# Placeholder macro written by tools/chip_assembly/macros.py
# kind: analog_pma; S81 SerDes PMA TX half (modelled analog, ot_s81_pma_bm LAT 4 behaviour)
VERSION 5.7 ;
BUSBITCHARS "[]" ;
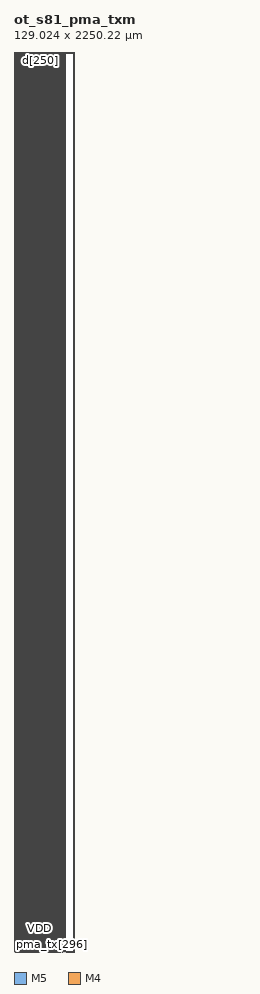
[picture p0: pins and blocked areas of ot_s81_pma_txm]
MACRO ot_s81_pma_txm
  FOREIGN ot_s81_pma_txm 0 0 ;
  SYMMETRY X Y R90 ;
  SIZE 129.024 BY 2250.216 ;
  CLASS BLOCK ;
  PIN ck
    DIRECTION INPUT ;
    USE SIGNAL ;
    SHAPE ABUTMENT ;
    PORT
      LAYER M5 ;
      RECT 5.472 2250.024 5.496 2250.216 ;
    END
  END ck
  PIN d_v
    DIRECTION INPUT ;
    USE SIGNAL ;
    SHAPE ABUTMENT ;
    PORT
      LAYER M5 ;
      RECT 9.984 2250.024 10.008 2250.216 ;
    END
  END d_v
  PIN d[0]
    DIRECTION INPUT ;
    USE SIGNAL ;
    SHAPE ABUTMENT ;
    PORT
      LAYER M5 ;
      RECT 14.496 2250.024 14.520 2250.216 ;
    END
  END d[0]
  PIN d[1]
    DIRECTION INPUT ;
    USE SIGNAL ;
    SHAPE ABUTMENT ;
    PORT
      LAYER M5 ;
      RECT 14.688 2250.024 14.712 2250.216 ;
    END
  END d[1]
  PIN d[2]
    DIRECTION INPUT ;
    USE SIGNAL ;
    SHAPE ABUTMENT ;
    PORT
      LAYER M5 ;
      RECT 14.880 2250.024 14.904 2250.216 ;
    END
  END d[2]
  PIN d[3]
    DIRECTION INPUT ;
    USE SIGNAL ;
    SHAPE ABUTMENT ;
    PORT
      LAYER M5 ;
      RECT 15.072 2250.024 15.096 2250.216 ;
    END
  END d[3]
  PIN d[4]
    DIRECTION INPUT ;
    USE SIGNAL ;
    SHAPE ABUTMENT ;
    PORT
      LAYER M5 ;
      RECT 15.264 2250.024 15.288 2250.216 ;
    END
  END d[4]
  PIN d[5]
    DIRECTION INPUT ;
    USE SIGNAL ;
    SHAPE ABUTMENT ;
    PORT
      LAYER M5 ;
      RECT 15.504 2250.024 15.528 2250.216 ;
    END
  END d[5]
  PIN d[6]
    DIRECTION INPUT ;
    USE SIGNAL ;
    SHAPE ABUTMENT ;
    PORT
      LAYER M5 ;
      RECT 15.696 2250.024 15.720 2250.216 ;
    END
  END d[6]
  PIN d[7]
    DIRECTION INPUT ;
    USE SIGNAL ;
    SHAPE ABUTMENT ;
    PORT
      LAYER M5 ;
      RECT 15.888 2250.024 15.912 2250.216 ;
    END
  END d[7]
  PIN d[8]
    DIRECTION INPUT ;
    USE SIGNAL ;
    SHAPE ABUTMENT ;
    PORT
      LAYER M5 ;
      RECT 16.080 2250.024 16.104 2250.216 ;
    END
  END d[8]
  PIN d[9]
    DIRECTION INPUT ;
    USE SIGNAL ;
    SHAPE ABUTMENT ;
    PORT
      LAYER M5 ;
      RECT 16.272 2250.024 16.296 2250.216 ;
    END
  END d[9]
  PIN d[10]
    DIRECTION INPUT ;
    USE SIGNAL ;
    SHAPE ABUTMENT ;
    PORT
      LAYER M5 ;
      RECT 16.512 2250.024 16.536 2250.216 ;
    END
  END d[10]
  PIN d[11]
    DIRECTION INPUT ;
    USE SIGNAL ;
    SHAPE ABUTMENT ;
    PORT
      LAYER M5 ;
      RECT 16.704 2250.024 16.728 2250.216 ;
    END
  END d[11]
  PIN d[12]
    DIRECTION INPUT ;
    USE SIGNAL ;
    SHAPE ABUTMENT ;
    PORT
      LAYER M5 ;
      RECT 16.896 2250.024 16.920 2250.216 ;
    END
  END d[12]
  PIN d[13]
    DIRECTION INPUT ;
    USE SIGNAL ;
    SHAPE ABUTMENT ;
    PORT
      LAYER M5 ;
      RECT 17.088 2250.024 17.112 2250.216 ;
    END
  END d[13]
  PIN d[14]
    DIRECTION INPUT ;
    USE SIGNAL ;
    SHAPE ABUTMENT ;
    PORT
      LAYER M5 ;
      RECT 17.280 2250.024 17.304 2250.216 ;
    END
  END d[14]
  PIN d[15]
    DIRECTION INPUT ;
    USE SIGNAL ;
    SHAPE ABUTMENT ;
    PORT
      LAYER M5 ;
      RECT 17.520 2250.024 17.544 2250.216 ;
    END
  END d[15]
  PIN d[16]
    DIRECTION INPUT ;
    USE SIGNAL ;
    SHAPE ABUTMENT ;
    PORT
      LAYER M5 ;
      RECT 17.712 2250.024 17.736 2250.216 ;
    END
  END d[16]
  PIN d[17]
    DIRECTION INPUT ;
    USE SIGNAL ;
    SHAPE ABUTMENT ;
    PORT
      LAYER M5 ;
      RECT 17.904 2250.024 17.928 2250.216 ;
    END
  END d[17]
  PIN d[18]
    DIRECTION INPUT ;
    USE SIGNAL ;
    SHAPE ABUTMENT ;
    PORT
      LAYER M5 ;
      RECT 18.096 2250.024 18.120 2250.216 ;
    END
  END d[18]
  PIN d[19]
    DIRECTION INPUT ;
    USE SIGNAL ;
    SHAPE ABUTMENT ;
    PORT
      LAYER M5 ;
      RECT 18.336 2250.024 18.360 2250.216 ;
    END
  END d[19]
  PIN d[20]
    DIRECTION INPUT ;
    USE SIGNAL ;
    SHAPE ABUTMENT ;
    PORT
      LAYER M5 ;
      RECT 18.528 2250.024 18.552 2250.216 ;
    END
  END d[20]
  PIN d[21]
    DIRECTION INPUT ;
    USE SIGNAL ;
    SHAPE ABUTMENT ;
    PORT
      LAYER M5 ;
      RECT 18.720 2250.024 18.744 2250.216 ;
    END
  END d[21]
  PIN d[22]
    DIRECTION INPUT ;
    USE SIGNAL ;
    SHAPE ABUTMENT ;
    PORT
      LAYER M5 ;
      RECT 18.912 2250.024 18.936 2250.216 ;
    END
  END d[22]
  PIN d[23]
    DIRECTION INPUT ;
    USE SIGNAL ;
    SHAPE ABUTMENT ;
    PORT
      LAYER M5 ;
      RECT 19.104 2250.024 19.128 2250.216 ;
    END
  END d[23]
  PIN d[24]
    DIRECTION INPUT ;
    USE SIGNAL ;
    SHAPE ABUTMENT ;
    PORT
      LAYER M5 ;
      RECT 19.344 2250.024 19.368 2250.216 ;
    END
  END d[24]
  PIN d[25]
    DIRECTION INPUT ;
    USE SIGNAL ;
    SHAPE ABUTMENT ;
    PORT
      LAYER M5 ;
      RECT 19.536 2250.024 19.560 2250.216 ;
    END
  END d[25]
  PIN d[26]
    DIRECTION INPUT ;
    USE SIGNAL ;
    SHAPE ABUTMENT ;
    PORT
      LAYER M5 ;
      RECT 19.728 2250.024 19.752 2250.216 ;
    END
  END d[26]
  PIN d[27]
    DIRECTION INPUT ;
    USE SIGNAL ;
    SHAPE ABUTMENT ;
    PORT
      LAYER M5 ;
      RECT 19.920 2250.024 19.944 2250.216 ;
    END
  END d[27]
  PIN d[28]
    DIRECTION INPUT ;
    USE SIGNAL ;
    SHAPE ABUTMENT ;
    PORT
      LAYER M5 ;
      RECT 20.112 2250.024 20.136 2250.216 ;
    END
  END d[28]
  PIN d[29]
    DIRECTION INPUT ;
    USE SIGNAL ;
    SHAPE ABUTMENT ;
    PORT
      LAYER M5 ;
      RECT 20.352 2250.024 20.376 2250.216 ;
    END
  END d[29]
  PIN d[30]
    DIRECTION INPUT ;
    USE SIGNAL ;
    SHAPE ABUTMENT ;
    PORT
      LAYER M5 ;
      RECT 20.544 2250.024 20.568 2250.216 ;
    END
  END d[30]
  PIN d[31]
    DIRECTION INPUT ;
    USE SIGNAL ;
    SHAPE ABUTMENT ;
    PORT
      LAYER M5 ;
      RECT 20.736 2250.024 20.760 2250.216 ;
    END
  END d[31]
  PIN d[32]
    DIRECTION INPUT ;
    USE SIGNAL ;
    SHAPE ABUTMENT ;
    PORT
      LAYER M5 ;
      RECT 20.928 2250.024 20.952 2250.216 ;
    END
  END d[32]
  PIN d[33]
    DIRECTION INPUT ;
    USE SIGNAL ;
    SHAPE ABUTMENT ;
    PORT
      LAYER M5 ;
      RECT 21.168 2250.024 21.192 2250.216 ;
    END
  END d[33]
  PIN d[34]
    DIRECTION INPUT ;
    USE SIGNAL ;
    SHAPE ABUTMENT ;
    PORT
      LAYER M5 ;
      RECT 21.360 2250.024 21.384 2250.216 ;
    END
  END d[34]
  PIN d[35]
    DIRECTION INPUT ;
    USE SIGNAL ;
    SHAPE ABUTMENT ;
    PORT
      LAYER M5 ;
      RECT 21.552 2250.024 21.576 2250.216 ;
    END
  END d[35]
  PIN d[36]
    DIRECTION INPUT ;
    USE SIGNAL ;
    SHAPE ABUTMENT ;
    PORT
      LAYER M5 ;
      RECT 21.744 2250.024 21.768 2250.216 ;
    END
  END d[36]
  PIN d[37]
    DIRECTION INPUT ;
    USE SIGNAL ;
    SHAPE ABUTMENT ;
    PORT
      LAYER M5 ;
      RECT 21.936 2250.024 21.960 2250.216 ;
    END
  END d[37]
  PIN d[38]
    DIRECTION INPUT ;
    USE SIGNAL ;
    SHAPE ABUTMENT ;
    PORT
      LAYER M5 ;
      RECT 22.176 2250.024 22.200 2250.216 ;
    END
  END d[38]
  PIN d[39]
    DIRECTION INPUT ;
    USE SIGNAL ;
    SHAPE ABUTMENT ;
    PORT
      LAYER M5 ;
      RECT 22.368 2250.024 22.392 2250.216 ;
    END
  END d[39]
  PIN d[40]
    DIRECTION INPUT ;
    USE SIGNAL ;
    SHAPE ABUTMENT ;
    PORT
      LAYER M5 ;
      RECT 22.560 2250.024 22.584 2250.216 ;
    END
  END d[40]
  PIN d[41]
    DIRECTION INPUT ;
    USE SIGNAL ;
    SHAPE ABUTMENT ;
    PORT
      LAYER M5 ;
      RECT 22.752 2250.024 22.776 2250.216 ;
    END
  END d[41]
  PIN d[42]
    DIRECTION INPUT ;
    USE SIGNAL ;
    SHAPE ABUTMENT ;
    PORT
      LAYER M5 ;
      RECT 22.944 2250.024 22.968 2250.216 ;
    END
  END d[42]
  PIN d[43]
    DIRECTION INPUT ;
    USE SIGNAL ;
    SHAPE ABUTMENT ;
    PORT
      LAYER M5 ;
      RECT 23.184 2250.024 23.208 2250.216 ;
    END
  END d[43]
  PIN d[44]
    DIRECTION INPUT ;
    USE SIGNAL ;
    SHAPE ABUTMENT ;
    PORT
      LAYER M5 ;
      RECT 23.376 2250.024 23.400 2250.216 ;
    END
  END d[44]
  PIN d[45]
    DIRECTION INPUT ;
    USE SIGNAL ;
    SHAPE ABUTMENT ;
    PORT
      LAYER M5 ;
      RECT 23.568 2250.024 23.592 2250.216 ;
    END
  END d[45]
  PIN d[46]
    DIRECTION INPUT ;
    USE SIGNAL ;
    SHAPE ABUTMENT ;
    PORT
      LAYER M5 ;
      RECT 23.760 2250.024 23.784 2250.216 ;
    END
  END d[46]
  PIN d[47]
    DIRECTION INPUT ;
    USE SIGNAL ;
    SHAPE ABUTMENT ;
    PORT
      LAYER M5 ;
      RECT 24.000 2250.024 24.024 2250.216 ;
    END
  END d[47]
  PIN d[48]
    DIRECTION INPUT ;
    USE SIGNAL ;
    SHAPE ABUTMENT ;
    PORT
      LAYER M5 ;
      RECT 24.192 2250.024 24.216 2250.216 ;
    END
  END d[48]
  PIN d[49]
    DIRECTION INPUT ;
    USE SIGNAL ;
    SHAPE ABUTMENT ;
    PORT
      LAYER M5 ;
      RECT 24.384 2250.024 24.408 2250.216 ;
    END
  END d[49]
  PIN d[50]
    DIRECTION INPUT ;
    USE SIGNAL ;
    SHAPE ABUTMENT ;
    PORT
      LAYER M5 ;
      RECT 24.576 2250.024 24.600 2250.216 ;
    END
  END d[50]
  PIN d[51]
    DIRECTION INPUT ;
    USE SIGNAL ;
    SHAPE ABUTMENT ;
    PORT
      LAYER M5 ;
      RECT 24.768 2250.024 24.792 2250.216 ;
    END
  END d[51]
  PIN d[52]
    DIRECTION INPUT ;
    USE SIGNAL ;
    SHAPE ABUTMENT ;
    PORT
      LAYER M5 ;
      RECT 25.008 2250.024 25.032 2250.216 ;
    END
  END d[52]
  PIN d[53]
    DIRECTION INPUT ;
    USE SIGNAL ;
    SHAPE ABUTMENT ;
    PORT
      LAYER M5 ;
      RECT 25.200 2250.024 25.224 2250.216 ;
    END
  END d[53]
  PIN d[54]
    DIRECTION INPUT ;
    USE SIGNAL ;
    SHAPE ABUTMENT ;
    PORT
      LAYER M5 ;
      RECT 25.392 2250.024 25.416 2250.216 ;
    END
  END d[54]
  PIN d[55]
    DIRECTION INPUT ;
    USE SIGNAL ;
    SHAPE ABUTMENT ;
    PORT
      LAYER M5 ;
      RECT 25.584 2250.024 25.608 2250.216 ;
    END
  END d[55]
  PIN d[56]
    DIRECTION INPUT ;
    USE SIGNAL ;
    SHAPE ABUTMENT ;
    PORT
      LAYER M5 ;
      RECT 25.776 2250.024 25.800 2250.216 ;
    END
  END d[56]
  PIN d[57]
    DIRECTION INPUT ;
    USE SIGNAL ;
    SHAPE ABUTMENT ;
    PORT
      LAYER M5 ;
      RECT 26.016 2250.024 26.040 2250.216 ;
    END
  END d[57]
  PIN d[58]
    DIRECTION INPUT ;
    USE SIGNAL ;
    SHAPE ABUTMENT ;
    PORT
      LAYER M5 ;
      RECT 26.208 2250.024 26.232 2250.216 ;
    END
  END d[58]
  PIN d[59]
    DIRECTION INPUT ;
    USE SIGNAL ;
    SHAPE ABUTMENT ;
    PORT
      LAYER M5 ;
      RECT 26.400 2250.024 26.424 2250.216 ;
    END
  END d[59]
  PIN d[60]
    DIRECTION INPUT ;
    USE SIGNAL ;
    SHAPE ABUTMENT ;
    PORT
      LAYER M5 ;
      RECT 26.592 2250.024 26.616 2250.216 ;
    END
  END d[60]
  PIN d[61]
    DIRECTION INPUT ;
    USE SIGNAL ;
    SHAPE ABUTMENT ;
    PORT
      LAYER M5 ;
      RECT 26.832 2250.024 26.856 2250.216 ;
    END
  END d[61]
  PIN d[62]
    DIRECTION INPUT ;
    USE SIGNAL ;
    SHAPE ABUTMENT ;
    PORT
      LAYER M5 ;
      RECT 27.024 2250.024 27.048 2250.216 ;
    END
  END d[62]
  PIN d[63]
    DIRECTION INPUT ;
    USE SIGNAL ;
    SHAPE ABUTMENT ;
    PORT
      LAYER M5 ;
      RECT 27.216 2250.024 27.240 2250.216 ;
    END
  END d[63]
  PIN d[64]
    DIRECTION INPUT ;
    USE SIGNAL ;
    SHAPE ABUTMENT ;
    PORT
      LAYER M5 ;
      RECT 27.408 2250.024 27.432 2250.216 ;
    END
  END d[64]
  PIN d[65]
    DIRECTION INPUT ;
    USE SIGNAL ;
    SHAPE ABUTMENT ;
    PORT
      LAYER M5 ;
      RECT 27.600 2250.024 27.624 2250.216 ;
    END
  END d[65]
  PIN d[66]
    DIRECTION INPUT ;
    USE SIGNAL ;
    SHAPE ABUTMENT ;
    PORT
      LAYER M5 ;
      RECT 27.840 2250.024 27.864 2250.216 ;
    END
  END d[66]
  PIN d[67]
    DIRECTION INPUT ;
    USE SIGNAL ;
    SHAPE ABUTMENT ;
    PORT
      LAYER M5 ;
      RECT 28.032 2250.024 28.056 2250.216 ;
    END
  END d[67]
  PIN d[68]
    DIRECTION INPUT ;
    USE SIGNAL ;
    SHAPE ABUTMENT ;
    PORT
      LAYER M5 ;
      RECT 28.224 2250.024 28.248 2250.216 ;
    END
  END d[68]
  PIN d[69]
    DIRECTION INPUT ;
    USE SIGNAL ;
    SHAPE ABUTMENT ;
    PORT
      LAYER M5 ;
      RECT 28.416 2250.024 28.440 2250.216 ;
    END
  END d[69]
  PIN d[70]
    DIRECTION INPUT ;
    USE SIGNAL ;
    SHAPE ABUTMENT ;
    PORT
      LAYER M5 ;
      RECT 28.608 2250.024 28.632 2250.216 ;
    END
  END d[70]
  PIN d[71]
    DIRECTION INPUT ;
    USE SIGNAL ;
    SHAPE ABUTMENT ;
    PORT
      LAYER M5 ;
      RECT 28.848 2250.024 28.872 2250.216 ;
    END
  END d[71]
  PIN d[72]
    DIRECTION INPUT ;
    USE SIGNAL ;
    SHAPE ABUTMENT ;
    PORT
      LAYER M5 ;
      RECT 29.040 2250.024 29.064 2250.216 ;
    END
  END d[72]
  PIN d[73]
    DIRECTION INPUT ;
    USE SIGNAL ;
    SHAPE ABUTMENT ;
    PORT
      LAYER M5 ;
      RECT 29.232 2250.024 29.256 2250.216 ;
    END
  END d[73]
  PIN d[74]
    DIRECTION INPUT ;
    USE SIGNAL ;
    SHAPE ABUTMENT ;
    PORT
      LAYER M5 ;
      RECT 29.424 2250.024 29.448 2250.216 ;
    END
  END d[74]
  PIN d[75]
    DIRECTION INPUT ;
    USE SIGNAL ;
    SHAPE ABUTMENT ;
    PORT
      LAYER M5 ;
      RECT 29.616 2250.024 29.640 2250.216 ;
    END
  END d[75]
  PIN d[76]
    DIRECTION INPUT ;
    USE SIGNAL ;
    SHAPE ABUTMENT ;
    PORT
      LAYER M5 ;
      RECT 29.856 2250.024 29.880 2250.216 ;
    END
  END d[76]
  PIN d[77]
    DIRECTION INPUT ;
    USE SIGNAL ;
    SHAPE ABUTMENT ;
    PORT
      LAYER M5 ;
      RECT 30.048 2250.024 30.072 2250.216 ;
    END
  END d[77]
  PIN d[78]
    DIRECTION INPUT ;
    USE SIGNAL ;
    SHAPE ABUTMENT ;
    PORT
      LAYER M5 ;
      RECT 30.240 2250.024 30.264 2250.216 ;
    END
  END d[78]
  PIN d[79]
    DIRECTION INPUT ;
    USE SIGNAL ;
    SHAPE ABUTMENT ;
    PORT
      LAYER M5 ;
      RECT 30.432 2250.024 30.456 2250.216 ;
    END
  END d[79]
  PIN d[80]
    DIRECTION INPUT ;
    USE SIGNAL ;
    SHAPE ABUTMENT ;
    PORT
      LAYER M5 ;
      RECT 30.672 2250.024 30.696 2250.216 ;
    END
  END d[80]
  PIN d[81]
    DIRECTION INPUT ;
    USE SIGNAL ;
    SHAPE ABUTMENT ;
    PORT
      LAYER M5 ;
      RECT 30.864 2250.024 30.888 2250.216 ;
    END
  END d[81]
  PIN d[82]
    DIRECTION INPUT ;
    USE SIGNAL ;
    SHAPE ABUTMENT ;
    PORT
      LAYER M5 ;
      RECT 31.056 2250.024 31.080 2250.216 ;
    END
  END d[82]
  PIN d[83]
    DIRECTION INPUT ;
    USE SIGNAL ;
    SHAPE ABUTMENT ;
    PORT
      LAYER M5 ;
      RECT 31.248 2250.024 31.272 2250.216 ;
    END
  END d[83]
  PIN d[84]
    DIRECTION INPUT ;
    USE SIGNAL ;
    SHAPE ABUTMENT ;
    PORT
      LAYER M5 ;
      RECT 31.440 2250.024 31.464 2250.216 ;
    END
  END d[84]
  PIN d[85]
    DIRECTION INPUT ;
    USE SIGNAL ;
    SHAPE ABUTMENT ;
    PORT
      LAYER M5 ;
      RECT 31.680 2250.024 31.704 2250.216 ;
    END
  END d[85]
  PIN d[86]
    DIRECTION INPUT ;
    USE SIGNAL ;
    SHAPE ABUTMENT ;
    PORT
      LAYER M5 ;
      RECT 31.872 2250.024 31.896 2250.216 ;
    END
  END d[86]
  PIN d[87]
    DIRECTION INPUT ;
    USE SIGNAL ;
    SHAPE ABUTMENT ;
    PORT
      LAYER M5 ;
      RECT 32.064 2250.024 32.088 2250.216 ;
    END
  END d[87]
  PIN d[88]
    DIRECTION INPUT ;
    USE SIGNAL ;
    SHAPE ABUTMENT ;
    PORT
      LAYER M5 ;
      RECT 32.256 2250.024 32.280 2250.216 ;
    END
  END d[88]
  PIN d[89]
    DIRECTION INPUT ;
    USE SIGNAL ;
    SHAPE ABUTMENT ;
    PORT
      LAYER M5 ;
      RECT 32.448 2250.024 32.472 2250.216 ;
    END
  END d[89]
  PIN d[90]
    DIRECTION INPUT ;
    USE SIGNAL ;
    SHAPE ABUTMENT ;
    PORT
      LAYER M5 ;
      RECT 32.688 2250.024 32.712 2250.216 ;
    END
  END d[90]
  PIN d[91]
    DIRECTION INPUT ;
    USE SIGNAL ;
    SHAPE ABUTMENT ;
    PORT
      LAYER M5 ;
      RECT 32.880 2250.024 32.904 2250.216 ;
    END
  END d[91]
  PIN d[92]
    DIRECTION INPUT ;
    USE SIGNAL ;
    SHAPE ABUTMENT ;
    PORT
      LAYER M5 ;
      RECT 33.072 2250.024 33.096 2250.216 ;
    END
  END d[92]
  PIN d[93]
    DIRECTION INPUT ;
    USE SIGNAL ;
    SHAPE ABUTMENT ;
    PORT
      LAYER M5 ;
      RECT 33.264 2250.024 33.288 2250.216 ;
    END
  END d[93]
  PIN d[94]
    DIRECTION INPUT ;
    USE SIGNAL ;
    SHAPE ABUTMENT ;
    PORT
      LAYER M5 ;
      RECT 33.504 2250.024 33.528 2250.216 ;
    END
  END d[94]
  PIN d[95]
    DIRECTION INPUT ;
    USE SIGNAL ;
    SHAPE ABUTMENT ;
    PORT
      LAYER M5 ;
      RECT 33.696 2250.024 33.720 2250.216 ;
    END
  END d[95]
  PIN d[96]
    DIRECTION INPUT ;
    USE SIGNAL ;
    SHAPE ABUTMENT ;
    PORT
      LAYER M5 ;
      RECT 33.888 2250.024 33.912 2250.216 ;
    END
  END d[96]
  PIN d[97]
    DIRECTION INPUT ;
    USE SIGNAL ;
    SHAPE ABUTMENT ;
    PORT
      LAYER M5 ;
      RECT 34.080 2250.024 34.104 2250.216 ;
    END
  END d[97]
  PIN d[98]
    DIRECTION INPUT ;
    USE SIGNAL ;
    SHAPE ABUTMENT ;
    PORT
      LAYER M5 ;
      RECT 34.272 2250.024 34.296 2250.216 ;
    END
  END d[98]
  PIN d[99]
    DIRECTION INPUT ;
    USE SIGNAL ;
    SHAPE ABUTMENT ;
    PORT
      LAYER M5 ;
      RECT 34.512 2250.024 34.536 2250.216 ;
    END
  END d[99]
  PIN d[100]
    DIRECTION INPUT ;
    USE SIGNAL ;
    SHAPE ABUTMENT ;
    PORT
      LAYER M5 ;
      RECT 34.704 2250.024 34.728 2250.216 ;
    END
  END d[100]
  PIN d[101]
    DIRECTION INPUT ;
    USE SIGNAL ;
    SHAPE ABUTMENT ;
    PORT
      LAYER M5 ;
      RECT 34.896 2250.024 34.920 2250.216 ;
    END
  END d[101]
  PIN d[102]
    DIRECTION INPUT ;
    USE SIGNAL ;
    SHAPE ABUTMENT ;
    PORT
      LAYER M5 ;
      RECT 35.088 2250.024 35.112 2250.216 ;
    END
  END d[102]
  PIN d[103]
    DIRECTION INPUT ;
    USE SIGNAL ;
    SHAPE ABUTMENT ;
    PORT
      LAYER M5 ;
      RECT 35.280 2250.024 35.304 2250.216 ;
    END
  END d[103]
  PIN d[104]
    DIRECTION INPUT ;
    USE SIGNAL ;
    SHAPE ABUTMENT ;
    PORT
      LAYER M5 ;
      RECT 35.520 2250.024 35.544 2250.216 ;
    END
  END d[104]
  PIN d[105]
    DIRECTION INPUT ;
    USE SIGNAL ;
    SHAPE ABUTMENT ;
    PORT
      LAYER M5 ;
      RECT 35.712 2250.024 35.736 2250.216 ;
    END
  END d[105]
  PIN d[106]
    DIRECTION INPUT ;
    USE SIGNAL ;
    SHAPE ABUTMENT ;
    PORT
      LAYER M5 ;
      RECT 35.904 2250.024 35.928 2250.216 ;
    END
  END d[106]
  PIN d[107]
    DIRECTION INPUT ;
    USE SIGNAL ;
    SHAPE ABUTMENT ;
    PORT
      LAYER M5 ;
      RECT 36.096 2250.024 36.120 2250.216 ;
    END
  END d[107]
  PIN d[108]
    DIRECTION INPUT ;
    USE SIGNAL ;
    SHAPE ABUTMENT ;
    PORT
      LAYER M5 ;
      RECT 36.336 2250.024 36.360 2250.216 ;
    END
  END d[108]
  PIN d[109]
    DIRECTION INPUT ;
    USE SIGNAL ;
    SHAPE ABUTMENT ;
    PORT
      LAYER M5 ;
      RECT 36.528 2250.024 36.552 2250.216 ;
    END
  END d[109]
  PIN d[110]
    DIRECTION INPUT ;
    USE SIGNAL ;
    SHAPE ABUTMENT ;
    PORT
      LAYER M5 ;
      RECT 36.720 2250.024 36.744 2250.216 ;
    END
  END d[110]
  PIN d[111]
    DIRECTION INPUT ;
    USE SIGNAL ;
    SHAPE ABUTMENT ;
    PORT
      LAYER M5 ;
      RECT 36.912 2250.024 36.936 2250.216 ;
    END
  END d[111]
  PIN d[112]
    DIRECTION INPUT ;
    USE SIGNAL ;
    SHAPE ABUTMENT ;
    PORT
      LAYER M5 ;
      RECT 37.104 2250.024 37.128 2250.216 ;
    END
  END d[112]
  PIN d[113]
    DIRECTION INPUT ;
    USE SIGNAL ;
    SHAPE ABUTMENT ;
    PORT
      LAYER M5 ;
      RECT 37.344 2250.024 37.368 2250.216 ;
    END
  END d[113]
  PIN d[114]
    DIRECTION INPUT ;
    USE SIGNAL ;
    SHAPE ABUTMENT ;
    PORT
      LAYER M5 ;
      RECT 37.536 2250.024 37.560 2250.216 ;
    END
  END d[114]
  PIN d[115]
    DIRECTION INPUT ;
    USE SIGNAL ;
    SHAPE ABUTMENT ;
    PORT
      LAYER M5 ;
      RECT 37.728 2250.024 37.752 2250.216 ;
    END
  END d[115]
  PIN d[116]
    DIRECTION INPUT ;
    USE SIGNAL ;
    SHAPE ABUTMENT ;
    PORT
      LAYER M5 ;
      RECT 37.920 2250.024 37.944 2250.216 ;
    END
  END d[116]
  PIN d[117]
    DIRECTION INPUT ;
    USE SIGNAL ;
    SHAPE ABUTMENT ;
    PORT
      LAYER M5 ;
      RECT 38.112 2250.024 38.136 2250.216 ;
    END
  END d[117]
  PIN d[118]
    DIRECTION INPUT ;
    USE SIGNAL ;
    SHAPE ABUTMENT ;
    PORT
      LAYER M5 ;
      RECT 38.352 2250.024 38.376 2250.216 ;
    END
  END d[118]
  PIN d[119]
    DIRECTION INPUT ;
    USE SIGNAL ;
    SHAPE ABUTMENT ;
    PORT
      LAYER M5 ;
      RECT 38.544 2250.024 38.568 2250.216 ;
    END
  END d[119]
  PIN d[120]
    DIRECTION INPUT ;
    USE SIGNAL ;
    SHAPE ABUTMENT ;
    PORT
      LAYER M5 ;
      RECT 38.736 2250.024 38.760 2250.216 ;
    END
  END d[120]
  PIN d[121]
    DIRECTION INPUT ;
    USE SIGNAL ;
    SHAPE ABUTMENT ;
    PORT
      LAYER M5 ;
      RECT 38.928 2250.024 38.952 2250.216 ;
    END
  END d[121]
  PIN d[122]
    DIRECTION INPUT ;
    USE SIGNAL ;
    SHAPE ABUTMENT ;
    PORT
      LAYER M5 ;
      RECT 39.168 2250.024 39.192 2250.216 ;
    END
  END d[122]
  PIN d[123]
    DIRECTION INPUT ;
    USE SIGNAL ;
    SHAPE ABUTMENT ;
    PORT
      LAYER M5 ;
      RECT 39.360 2250.024 39.384 2250.216 ;
    END
  END d[123]
  PIN d[124]
    DIRECTION INPUT ;
    USE SIGNAL ;
    SHAPE ABUTMENT ;
    PORT
      LAYER M5 ;
      RECT 39.552 2250.024 39.576 2250.216 ;
    END
  END d[124]
  PIN d[125]
    DIRECTION INPUT ;
    USE SIGNAL ;
    SHAPE ABUTMENT ;
    PORT
      LAYER M5 ;
      RECT 39.744 2250.024 39.768 2250.216 ;
    END
  END d[125]
  PIN d[126]
    DIRECTION INPUT ;
    USE SIGNAL ;
    SHAPE ABUTMENT ;
    PORT
      LAYER M5 ;
      RECT 39.936 2250.024 39.960 2250.216 ;
    END
  END d[126]
  PIN d[127]
    DIRECTION INPUT ;
    USE SIGNAL ;
    SHAPE ABUTMENT ;
    PORT
      LAYER M5 ;
      RECT 40.176 2250.024 40.200 2250.216 ;
    END
  END d[127]
  PIN d[128]
    DIRECTION INPUT ;
    USE SIGNAL ;
    SHAPE ABUTMENT ;
    PORT
      LAYER M5 ;
      RECT 40.368 2250.024 40.392 2250.216 ;
    END
  END d[128]
  PIN d[129]
    DIRECTION INPUT ;
    USE SIGNAL ;
    SHAPE ABUTMENT ;
    PORT
      LAYER M5 ;
      RECT 40.560 2250.024 40.584 2250.216 ;
    END
  END d[129]
  PIN d[130]
    DIRECTION INPUT ;
    USE SIGNAL ;
    SHAPE ABUTMENT ;
    PORT
      LAYER M5 ;
      RECT 40.752 2250.024 40.776 2250.216 ;
    END
  END d[130]
  PIN d[131]
    DIRECTION INPUT ;
    USE SIGNAL ;
    SHAPE ABUTMENT ;
    PORT
      LAYER M5 ;
      RECT 40.944 2250.024 40.968 2250.216 ;
    END
  END d[131]
  PIN d[132]
    DIRECTION INPUT ;
    USE SIGNAL ;
    SHAPE ABUTMENT ;
    PORT
      LAYER M5 ;
      RECT 41.184 2250.024 41.208 2250.216 ;
    END
  END d[132]
  PIN d[133]
    DIRECTION INPUT ;
    USE SIGNAL ;
    SHAPE ABUTMENT ;
    PORT
      LAYER M5 ;
      RECT 41.376 2250.024 41.400 2250.216 ;
    END
  END d[133]
  PIN d[134]
    DIRECTION INPUT ;
    USE SIGNAL ;
    SHAPE ABUTMENT ;
    PORT
      LAYER M5 ;
      RECT 41.568 2250.024 41.592 2250.216 ;
    END
  END d[134]
  PIN d[135]
    DIRECTION INPUT ;
    USE SIGNAL ;
    SHAPE ABUTMENT ;
    PORT
      LAYER M5 ;
      RECT 41.760 2250.024 41.784 2250.216 ;
    END
  END d[135]
  PIN d[136]
    DIRECTION INPUT ;
    USE SIGNAL ;
    SHAPE ABUTMENT ;
    PORT
      LAYER M5 ;
      RECT 42.000 2250.024 42.024 2250.216 ;
    END
  END d[136]
  PIN d[137]
    DIRECTION INPUT ;
    USE SIGNAL ;
    SHAPE ABUTMENT ;
    PORT
      LAYER M5 ;
      RECT 42.192 2250.024 42.216 2250.216 ;
    END
  END d[137]
  PIN d[138]
    DIRECTION INPUT ;
    USE SIGNAL ;
    SHAPE ABUTMENT ;
    PORT
      LAYER M5 ;
      RECT 42.384 2250.024 42.408 2250.216 ;
    END
  END d[138]
  PIN d[139]
    DIRECTION INPUT ;
    USE SIGNAL ;
    SHAPE ABUTMENT ;
    PORT
      LAYER M5 ;
      RECT 42.576 2250.024 42.600 2250.216 ;
    END
  END d[139]
  PIN d[140]
    DIRECTION INPUT ;
    USE SIGNAL ;
    SHAPE ABUTMENT ;
    PORT
      LAYER M5 ;
      RECT 42.768 2250.024 42.792 2250.216 ;
    END
  END d[140]
  PIN d[141]
    DIRECTION INPUT ;
    USE SIGNAL ;
    SHAPE ABUTMENT ;
    PORT
      LAYER M5 ;
      RECT 43.008 2250.024 43.032 2250.216 ;
    END
  END d[141]
  PIN d[142]
    DIRECTION INPUT ;
    USE SIGNAL ;
    SHAPE ABUTMENT ;
    PORT
      LAYER M5 ;
      RECT 43.200 2250.024 43.224 2250.216 ;
    END
  END d[142]
  PIN d[143]
    DIRECTION INPUT ;
    USE SIGNAL ;
    SHAPE ABUTMENT ;
    PORT
      LAYER M5 ;
      RECT 43.392 2250.024 43.416 2250.216 ;
    END
  END d[143]
  PIN d[144]
    DIRECTION INPUT ;
    USE SIGNAL ;
    SHAPE ABUTMENT ;
    PORT
      LAYER M5 ;
      RECT 43.584 2250.024 43.608 2250.216 ;
    END
  END d[144]
  PIN d[145]
    DIRECTION INPUT ;
    USE SIGNAL ;
    SHAPE ABUTMENT ;
    PORT
      LAYER M5 ;
      RECT 43.776 2250.024 43.800 2250.216 ;
    END
  END d[145]
  PIN d[146]
    DIRECTION INPUT ;
    USE SIGNAL ;
    SHAPE ABUTMENT ;
    PORT
      LAYER M5 ;
      RECT 44.016 2250.024 44.040 2250.216 ;
    END
  END d[146]
  PIN d[147]
    DIRECTION INPUT ;
    USE SIGNAL ;
    SHAPE ABUTMENT ;
    PORT
      LAYER M5 ;
      RECT 44.208 2250.024 44.232 2250.216 ;
    END
  END d[147]
  PIN d[148]
    DIRECTION INPUT ;
    USE SIGNAL ;
    SHAPE ABUTMENT ;
    PORT
      LAYER M5 ;
      RECT 44.400 2250.024 44.424 2250.216 ;
    END
  END d[148]
  PIN d[149]
    DIRECTION INPUT ;
    USE SIGNAL ;
    SHAPE ABUTMENT ;
    PORT
      LAYER M5 ;
      RECT 44.592 2250.024 44.616 2250.216 ;
    END
  END d[149]
  PIN d[150]
    DIRECTION INPUT ;
    USE SIGNAL ;
    SHAPE ABUTMENT ;
    PORT
      LAYER M5 ;
      RECT 44.784 2250.024 44.808 2250.216 ;
    END
  END d[150]
  PIN d[151]
    DIRECTION INPUT ;
    USE SIGNAL ;
    SHAPE ABUTMENT ;
    PORT
      LAYER M5 ;
      RECT 45.024 2250.024 45.048 2250.216 ;
    END
  END d[151]
  PIN d[152]
    DIRECTION INPUT ;
    USE SIGNAL ;
    SHAPE ABUTMENT ;
    PORT
      LAYER M5 ;
      RECT 45.216 2250.024 45.240 2250.216 ;
    END
  END d[152]
  PIN d[153]
    DIRECTION INPUT ;
    USE SIGNAL ;
    SHAPE ABUTMENT ;
    PORT
      LAYER M5 ;
      RECT 45.408 2250.024 45.432 2250.216 ;
    END
  END d[153]
  PIN d[154]
    DIRECTION INPUT ;
    USE SIGNAL ;
    SHAPE ABUTMENT ;
    PORT
      LAYER M5 ;
      RECT 45.600 2250.024 45.624 2250.216 ;
    END
  END d[154]
  PIN d[155]
    DIRECTION INPUT ;
    USE SIGNAL ;
    SHAPE ABUTMENT ;
    PORT
      LAYER M5 ;
      RECT 45.840 2250.024 45.864 2250.216 ;
    END
  END d[155]
  PIN d[156]
    DIRECTION INPUT ;
    USE SIGNAL ;
    SHAPE ABUTMENT ;
    PORT
      LAYER M5 ;
      RECT 46.032 2250.024 46.056 2250.216 ;
    END
  END d[156]
  PIN d[157]
    DIRECTION INPUT ;
    USE SIGNAL ;
    SHAPE ABUTMENT ;
    PORT
      LAYER M5 ;
      RECT 46.224 2250.024 46.248 2250.216 ;
    END
  END d[157]
  PIN d[158]
    DIRECTION INPUT ;
    USE SIGNAL ;
    SHAPE ABUTMENT ;
    PORT
      LAYER M5 ;
      RECT 46.416 2250.024 46.440 2250.216 ;
    END
  END d[158]
  PIN d[159]
    DIRECTION INPUT ;
    USE SIGNAL ;
    SHAPE ABUTMENT ;
    PORT
      LAYER M5 ;
      RECT 46.608 2250.024 46.632 2250.216 ;
    END
  END d[159]
  PIN d[160]
    DIRECTION INPUT ;
    USE SIGNAL ;
    SHAPE ABUTMENT ;
    PORT
      LAYER M5 ;
      RECT 46.848 2250.024 46.872 2250.216 ;
    END
  END d[160]
  PIN d[161]
    DIRECTION INPUT ;
    USE SIGNAL ;
    SHAPE ABUTMENT ;
    PORT
      LAYER M5 ;
      RECT 47.040 2250.024 47.064 2250.216 ;
    END
  END d[161]
  PIN d[162]
    DIRECTION INPUT ;
    USE SIGNAL ;
    SHAPE ABUTMENT ;
    PORT
      LAYER M5 ;
      RECT 47.232 2250.024 47.256 2250.216 ;
    END
  END d[162]
  PIN d[163]
    DIRECTION INPUT ;
    USE SIGNAL ;
    SHAPE ABUTMENT ;
    PORT
      LAYER M5 ;
      RECT 47.424 2250.024 47.448 2250.216 ;
    END
  END d[163]
  PIN d[164]
    DIRECTION INPUT ;
    USE SIGNAL ;
    SHAPE ABUTMENT ;
    PORT
      LAYER M5 ;
      RECT 47.616 2250.024 47.640 2250.216 ;
    END
  END d[164]
  PIN d[165]
    DIRECTION INPUT ;
    USE SIGNAL ;
    SHAPE ABUTMENT ;
    PORT
      LAYER M5 ;
      RECT 47.856 2250.024 47.880 2250.216 ;
    END
  END d[165]
  PIN d[166]
    DIRECTION INPUT ;
    USE SIGNAL ;
    SHAPE ABUTMENT ;
    PORT
      LAYER M5 ;
      RECT 48.048 2250.024 48.072 2250.216 ;
    END
  END d[166]
  PIN d[167]
    DIRECTION INPUT ;
    USE SIGNAL ;
    SHAPE ABUTMENT ;
    PORT
      LAYER M5 ;
      RECT 48.240 2250.024 48.264 2250.216 ;
    END
  END d[167]
  PIN d[168]
    DIRECTION INPUT ;
    USE SIGNAL ;
    SHAPE ABUTMENT ;
    PORT
      LAYER M5 ;
      RECT 48.432 2250.024 48.456 2250.216 ;
    END
  END d[168]
  PIN d[169]
    DIRECTION INPUT ;
    USE SIGNAL ;
    SHAPE ABUTMENT ;
    PORT
      LAYER M5 ;
      RECT 48.672 2250.024 48.696 2250.216 ;
    END
  END d[169]
  PIN d[170]
    DIRECTION INPUT ;
    USE SIGNAL ;
    SHAPE ABUTMENT ;
    PORT
      LAYER M5 ;
      RECT 48.864 2250.024 48.888 2250.216 ;
    END
  END d[170]
  PIN d[171]
    DIRECTION INPUT ;
    USE SIGNAL ;
    SHAPE ABUTMENT ;
    PORT
      LAYER M5 ;
      RECT 49.056 2250.024 49.080 2250.216 ;
    END
  END d[171]
  PIN d[172]
    DIRECTION INPUT ;
    USE SIGNAL ;
    SHAPE ABUTMENT ;
    PORT
      LAYER M5 ;
      RECT 49.248 2250.024 49.272 2250.216 ;
    END
  END d[172]
  PIN d[173]
    DIRECTION INPUT ;
    USE SIGNAL ;
    SHAPE ABUTMENT ;
    PORT
      LAYER M5 ;
      RECT 49.440 2250.024 49.464 2250.216 ;
    END
  END d[173]
  PIN d[174]
    DIRECTION INPUT ;
    USE SIGNAL ;
    SHAPE ABUTMENT ;
    PORT
      LAYER M5 ;
      RECT 49.680 2250.024 49.704 2250.216 ;
    END
  END d[174]
  PIN d[175]
    DIRECTION INPUT ;
    USE SIGNAL ;
    SHAPE ABUTMENT ;
    PORT
      LAYER M5 ;
      RECT 49.872 2250.024 49.896 2250.216 ;
    END
  END d[175]
  PIN d[176]
    DIRECTION INPUT ;
    USE SIGNAL ;
    SHAPE ABUTMENT ;
    PORT
      LAYER M5 ;
      RECT 50.064 2250.024 50.088 2250.216 ;
    END
  END d[176]
  PIN d[177]
    DIRECTION INPUT ;
    USE SIGNAL ;
    SHAPE ABUTMENT ;
    PORT
      LAYER M5 ;
      RECT 50.256 2250.024 50.280 2250.216 ;
    END
  END d[177]
  PIN d[178]
    DIRECTION INPUT ;
    USE SIGNAL ;
    SHAPE ABUTMENT ;
    PORT
      LAYER M5 ;
      RECT 50.448 2250.024 50.472 2250.216 ;
    END
  END d[178]
  PIN d[179]
    DIRECTION INPUT ;
    USE SIGNAL ;
    SHAPE ABUTMENT ;
    PORT
      LAYER M5 ;
      RECT 50.688 2250.024 50.712 2250.216 ;
    END
  END d[179]
  PIN d[180]
    DIRECTION INPUT ;
    USE SIGNAL ;
    SHAPE ABUTMENT ;
    PORT
      LAYER M5 ;
      RECT 50.880 2250.024 50.904 2250.216 ;
    END
  END d[180]
  PIN d[181]
    DIRECTION INPUT ;
    USE SIGNAL ;
    SHAPE ABUTMENT ;
    PORT
      LAYER M5 ;
      RECT 51.072 2250.024 51.096 2250.216 ;
    END
  END d[181]
  PIN d[182]
    DIRECTION INPUT ;
    USE SIGNAL ;
    SHAPE ABUTMENT ;
    PORT
      LAYER M5 ;
      RECT 51.264 2250.024 51.288 2250.216 ;
    END
  END d[182]
  PIN d[183]
    DIRECTION INPUT ;
    USE SIGNAL ;
    SHAPE ABUTMENT ;
    PORT
      LAYER M5 ;
      RECT 51.504 2250.024 51.528 2250.216 ;
    END
  END d[183]
  PIN d[184]
    DIRECTION INPUT ;
    USE SIGNAL ;
    SHAPE ABUTMENT ;
    PORT
      LAYER M5 ;
      RECT 51.696 2250.024 51.720 2250.216 ;
    END
  END d[184]
  PIN d[185]
    DIRECTION INPUT ;
    USE SIGNAL ;
    SHAPE ABUTMENT ;
    PORT
      LAYER M5 ;
      RECT 51.888 2250.024 51.912 2250.216 ;
    END
  END d[185]
  PIN d[186]
    DIRECTION INPUT ;
    USE SIGNAL ;
    SHAPE ABUTMENT ;
    PORT
      LAYER M5 ;
      RECT 52.080 2250.024 52.104 2250.216 ;
    END
  END d[186]
  PIN d[187]
    DIRECTION INPUT ;
    USE SIGNAL ;
    SHAPE ABUTMENT ;
    PORT
      LAYER M5 ;
      RECT 52.272 2250.024 52.296 2250.216 ;
    END
  END d[187]
  PIN d[188]
    DIRECTION INPUT ;
    USE SIGNAL ;
    SHAPE ABUTMENT ;
    PORT
      LAYER M5 ;
      RECT 52.512 2250.024 52.536 2250.216 ;
    END
  END d[188]
  PIN d[189]
    DIRECTION INPUT ;
    USE SIGNAL ;
    SHAPE ABUTMENT ;
    PORT
      LAYER M5 ;
      RECT 52.704 2250.024 52.728 2250.216 ;
    END
  END d[189]
  PIN d[190]
    DIRECTION INPUT ;
    USE SIGNAL ;
    SHAPE ABUTMENT ;
    PORT
      LAYER M5 ;
      RECT 52.896 2250.024 52.920 2250.216 ;
    END
  END d[190]
  PIN d[191]
    DIRECTION INPUT ;
    USE SIGNAL ;
    SHAPE ABUTMENT ;
    PORT
      LAYER M5 ;
      RECT 53.088 2250.024 53.112 2250.216 ;
    END
  END d[191]
  PIN d[192]
    DIRECTION INPUT ;
    USE SIGNAL ;
    SHAPE ABUTMENT ;
    PORT
      LAYER M5 ;
      RECT 53.280 2250.024 53.304 2250.216 ;
    END
  END d[192]
  PIN d[193]
    DIRECTION INPUT ;
    USE SIGNAL ;
    SHAPE ABUTMENT ;
    PORT
      LAYER M5 ;
      RECT 53.520 2250.024 53.544 2250.216 ;
    END
  END d[193]
  PIN d[194]
    DIRECTION INPUT ;
    USE SIGNAL ;
    SHAPE ABUTMENT ;
    PORT
      LAYER M5 ;
      RECT 53.712 2250.024 53.736 2250.216 ;
    END
  END d[194]
  PIN d[195]
    DIRECTION INPUT ;
    USE SIGNAL ;
    SHAPE ABUTMENT ;
    PORT
      LAYER M5 ;
      RECT 53.904 2250.024 53.928 2250.216 ;
    END
  END d[195]
  PIN d[196]
    DIRECTION INPUT ;
    USE SIGNAL ;
    SHAPE ABUTMENT ;
    PORT
      LAYER M5 ;
      RECT 54.096 2250.024 54.120 2250.216 ;
    END
  END d[196]
  PIN d[197]
    DIRECTION INPUT ;
    USE SIGNAL ;
    SHAPE ABUTMENT ;
    PORT
      LAYER M5 ;
      RECT 54.336 2250.024 54.360 2250.216 ;
    END
  END d[197]
  PIN d[198]
    DIRECTION INPUT ;
    USE SIGNAL ;
    SHAPE ABUTMENT ;
    PORT
      LAYER M5 ;
      RECT 54.528 2250.024 54.552 2250.216 ;
    END
  END d[198]
  PIN d[199]
    DIRECTION INPUT ;
    USE SIGNAL ;
    SHAPE ABUTMENT ;
    PORT
      LAYER M5 ;
      RECT 54.720 2250.024 54.744 2250.216 ;
    END
  END d[199]
  PIN d[200]
    DIRECTION INPUT ;
    USE SIGNAL ;
    SHAPE ABUTMENT ;
    PORT
      LAYER M5 ;
      RECT 54.912 2250.024 54.936 2250.216 ;
    END
  END d[200]
  PIN d[201]
    DIRECTION INPUT ;
    USE SIGNAL ;
    SHAPE ABUTMENT ;
    PORT
      LAYER M5 ;
      RECT 55.104 2250.024 55.128 2250.216 ;
    END
  END d[201]
  PIN d[202]
    DIRECTION INPUT ;
    USE SIGNAL ;
    SHAPE ABUTMENT ;
    PORT
      LAYER M5 ;
      RECT 55.344 2250.024 55.368 2250.216 ;
    END
  END d[202]
  PIN d[203]
    DIRECTION INPUT ;
    USE SIGNAL ;
    SHAPE ABUTMENT ;
    PORT
      LAYER M5 ;
      RECT 55.536 2250.024 55.560 2250.216 ;
    END
  END d[203]
  PIN d[204]
    DIRECTION INPUT ;
    USE SIGNAL ;
    SHAPE ABUTMENT ;
    PORT
      LAYER M5 ;
      RECT 55.728 2250.024 55.752 2250.216 ;
    END
  END d[204]
  PIN d[205]
    DIRECTION INPUT ;
    USE SIGNAL ;
    SHAPE ABUTMENT ;
    PORT
      LAYER M5 ;
      RECT 55.920 2250.024 55.944 2250.216 ;
    END
  END d[205]
  PIN d[206]
    DIRECTION INPUT ;
    USE SIGNAL ;
    SHAPE ABUTMENT ;
    PORT
      LAYER M5 ;
      RECT 56.112 2250.024 56.136 2250.216 ;
    END
  END d[206]
  PIN d[207]
    DIRECTION INPUT ;
    USE SIGNAL ;
    SHAPE ABUTMENT ;
    PORT
      LAYER M5 ;
      RECT 56.352 2250.024 56.376 2250.216 ;
    END
  END d[207]
  PIN d[208]
    DIRECTION INPUT ;
    USE SIGNAL ;
    SHAPE ABUTMENT ;
    PORT
      LAYER M5 ;
      RECT 56.544 2250.024 56.568 2250.216 ;
    END
  END d[208]
  PIN d[209]
    DIRECTION INPUT ;
    USE SIGNAL ;
    SHAPE ABUTMENT ;
    PORT
      LAYER M5 ;
      RECT 56.736 2250.024 56.760 2250.216 ;
    END
  END d[209]
  PIN d[210]
    DIRECTION INPUT ;
    USE SIGNAL ;
    SHAPE ABUTMENT ;
    PORT
      LAYER M5 ;
      RECT 56.928 2250.024 56.952 2250.216 ;
    END
  END d[210]
  PIN d[211]
    DIRECTION INPUT ;
    USE SIGNAL ;
    SHAPE ABUTMENT ;
    PORT
      LAYER M5 ;
      RECT 57.120 2250.024 57.144 2250.216 ;
    END
  END d[211]
  PIN d[212]
    DIRECTION INPUT ;
    USE SIGNAL ;
    SHAPE ABUTMENT ;
    PORT
      LAYER M5 ;
      RECT 57.360 2250.024 57.384 2250.216 ;
    END
  END d[212]
  PIN d[213]
    DIRECTION INPUT ;
    USE SIGNAL ;
    SHAPE ABUTMENT ;
    PORT
      LAYER M5 ;
      RECT 57.552 2250.024 57.576 2250.216 ;
    END
  END d[213]
  PIN d[214]
    DIRECTION INPUT ;
    USE SIGNAL ;
    SHAPE ABUTMENT ;
    PORT
      LAYER M5 ;
      RECT 57.744 2250.024 57.768 2250.216 ;
    END
  END d[214]
  PIN d[215]
    DIRECTION INPUT ;
    USE SIGNAL ;
    SHAPE ABUTMENT ;
    PORT
      LAYER M5 ;
      RECT 57.936 2250.024 57.960 2250.216 ;
    END
  END d[215]
  PIN d[216]
    DIRECTION INPUT ;
    USE SIGNAL ;
    SHAPE ABUTMENT ;
    PORT
      LAYER M5 ;
      RECT 58.176 2250.024 58.200 2250.216 ;
    END
  END d[216]
  PIN d[217]
    DIRECTION INPUT ;
    USE SIGNAL ;
    SHAPE ABUTMENT ;
    PORT
      LAYER M5 ;
      RECT 58.368 2250.024 58.392 2250.216 ;
    END
  END d[217]
  PIN d[218]
    DIRECTION INPUT ;
    USE SIGNAL ;
    SHAPE ABUTMENT ;
    PORT
      LAYER M5 ;
      RECT 58.560 2250.024 58.584 2250.216 ;
    END
  END d[218]
  PIN d[219]
    DIRECTION INPUT ;
    USE SIGNAL ;
    SHAPE ABUTMENT ;
    PORT
      LAYER M5 ;
      RECT 58.752 2250.024 58.776 2250.216 ;
    END
  END d[219]
  PIN d[220]
    DIRECTION INPUT ;
    USE SIGNAL ;
    SHAPE ABUTMENT ;
    PORT
      LAYER M5 ;
      RECT 58.944 2250.024 58.968 2250.216 ;
    END
  END d[220]
  PIN d[221]
    DIRECTION INPUT ;
    USE SIGNAL ;
    SHAPE ABUTMENT ;
    PORT
      LAYER M5 ;
      RECT 59.184 2250.024 59.208 2250.216 ;
    END
  END d[221]
  PIN d[222]
    DIRECTION INPUT ;
    USE SIGNAL ;
    SHAPE ABUTMENT ;
    PORT
      LAYER M5 ;
      RECT 59.376 2250.024 59.400 2250.216 ;
    END
  END d[222]
  PIN d[223]
    DIRECTION INPUT ;
    USE SIGNAL ;
    SHAPE ABUTMENT ;
    PORT
      LAYER M5 ;
      RECT 59.568 2250.024 59.592 2250.216 ;
    END
  END d[223]
  PIN d[224]
    DIRECTION INPUT ;
    USE SIGNAL ;
    SHAPE ABUTMENT ;
    PORT
      LAYER M5 ;
      RECT 59.760 2250.024 59.784 2250.216 ;
    END
  END d[224]
  PIN d[225]
    DIRECTION INPUT ;
    USE SIGNAL ;
    SHAPE ABUTMENT ;
    PORT
      LAYER M5 ;
      RECT 59.952 2250.024 59.976 2250.216 ;
    END
  END d[225]
  PIN d[226]
    DIRECTION INPUT ;
    USE SIGNAL ;
    SHAPE ABUTMENT ;
    PORT
      LAYER M5 ;
      RECT 60.192 2250.024 60.216 2250.216 ;
    END
  END d[226]
  PIN d[227]
    DIRECTION INPUT ;
    USE SIGNAL ;
    SHAPE ABUTMENT ;
    PORT
      LAYER M5 ;
      RECT 60.384 2250.024 60.408 2250.216 ;
    END
  END d[227]
  PIN d[228]
    DIRECTION INPUT ;
    USE SIGNAL ;
    SHAPE ABUTMENT ;
    PORT
      LAYER M5 ;
      RECT 60.576 2250.024 60.600 2250.216 ;
    END
  END d[228]
  PIN d[229]
    DIRECTION INPUT ;
    USE SIGNAL ;
    SHAPE ABUTMENT ;
    PORT
      LAYER M5 ;
      RECT 60.768 2250.024 60.792 2250.216 ;
    END
  END d[229]
  PIN d[230]
    DIRECTION INPUT ;
    USE SIGNAL ;
    SHAPE ABUTMENT ;
    PORT
      LAYER M5 ;
      RECT 61.008 2250.024 61.032 2250.216 ;
    END
  END d[230]
  PIN d[231]
    DIRECTION INPUT ;
    USE SIGNAL ;
    SHAPE ABUTMENT ;
    PORT
      LAYER M5 ;
      RECT 61.200 2250.024 61.224 2250.216 ;
    END
  END d[231]
  PIN d[232]
    DIRECTION INPUT ;
    USE SIGNAL ;
    SHAPE ABUTMENT ;
    PORT
      LAYER M5 ;
      RECT 61.392 2250.024 61.416 2250.216 ;
    END
  END d[232]
  PIN d[233]
    DIRECTION INPUT ;
    USE SIGNAL ;
    SHAPE ABUTMENT ;
    PORT
      LAYER M5 ;
      RECT 61.584 2250.024 61.608 2250.216 ;
    END
  END d[233]
  PIN d[234]
    DIRECTION INPUT ;
    USE SIGNAL ;
    SHAPE ABUTMENT ;
    PORT
      LAYER M5 ;
      RECT 61.776 2250.024 61.800 2250.216 ;
    END
  END d[234]
  PIN d[235]
    DIRECTION INPUT ;
    USE SIGNAL ;
    SHAPE ABUTMENT ;
    PORT
      LAYER M5 ;
      RECT 62.016 2250.024 62.040 2250.216 ;
    END
  END d[235]
  PIN d[236]
    DIRECTION INPUT ;
    USE SIGNAL ;
    SHAPE ABUTMENT ;
    PORT
      LAYER M5 ;
      RECT 62.208 2250.024 62.232 2250.216 ;
    END
  END d[236]
  PIN d[237]
    DIRECTION INPUT ;
    USE SIGNAL ;
    SHAPE ABUTMENT ;
    PORT
      LAYER M5 ;
      RECT 62.400 2250.024 62.424 2250.216 ;
    END
  END d[237]
  PIN d[238]
    DIRECTION INPUT ;
    USE SIGNAL ;
    SHAPE ABUTMENT ;
    PORT
      LAYER M5 ;
      RECT 62.592 2250.024 62.616 2250.216 ;
    END
  END d[238]
  PIN d[239]
    DIRECTION INPUT ;
    USE SIGNAL ;
    SHAPE ABUTMENT ;
    PORT
      LAYER M5 ;
      RECT 62.784 2250.024 62.808 2250.216 ;
    END
  END d[239]
  PIN d[240]
    DIRECTION INPUT ;
    USE SIGNAL ;
    SHAPE ABUTMENT ;
    PORT
      LAYER M5 ;
      RECT 63.024 2250.024 63.048 2250.216 ;
    END
  END d[240]
  PIN d[241]
    DIRECTION INPUT ;
    USE SIGNAL ;
    SHAPE ABUTMENT ;
    PORT
      LAYER M5 ;
      RECT 63.216 2250.024 63.240 2250.216 ;
    END
  END d[241]
  PIN d[242]
    DIRECTION INPUT ;
    USE SIGNAL ;
    SHAPE ABUTMENT ;
    PORT
      LAYER M5 ;
      RECT 63.408 2250.024 63.432 2250.216 ;
    END
  END d[242]
  PIN d[243]
    DIRECTION INPUT ;
    USE SIGNAL ;
    SHAPE ABUTMENT ;
    PORT
      LAYER M5 ;
      RECT 63.600 2250.024 63.624 2250.216 ;
    END
  END d[243]
  PIN d[244]
    DIRECTION INPUT ;
    USE SIGNAL ;
    SHAPE ABUTMENT ;
    PORT
      LAYER M5 ;
      RECT 63.840 2250.024 63.864 2250.216 ;
    END
  END d[244]
  PIN d[245]
    DIRECTION INPUT ;
    USE SIGNAL ;
    SHAPE ABUTMENT ;
    PORT
      LAYER M5 ;
      RECT 64.032 2250.024 64.056 2250.216 ;
    END
  END d[245]
  PIN d[246]
    DIRECTION INPUT ;
    USE SIGNAL ;
    SHAPE ABUTMENT ;
    PORT
      LAYER M5 ;
      RECT 64.224 2250.024 64.248 2250.216 ;
    END
  END d[246]
  PIN d[247]
    DIRECTION INPUT ;
    USE SIGNAL ;
    SHAPE ABUTMENT ;
    PORT
      LAYER M5 ;
      RECT 64.416 2250.024 64.440 2250.216 ;
    END
  END d[247]
  PIN d[248]
    DIRECTION INPUT ;
    USE SIGNAL ;
    SHAPE ABUTMENT ;
    PORT
      LAYER M5 ;
      RECT 64.608 2250.024 64.632 2250.216 ;
    END
  END d[248]
  PIN d[249]
    DIRECTION INPUT ;
    USE SIGNAL ;
    SHAPE ABUTMENT ;
    PORT
      LAYER M5 ;
      RECT 64.848 2250.024 64.872 2250.216 ;
    END
  END d[249]
  PIN d[250]
    DIRECTION INPUT ;
    USE SIGNAL ;
    SHAPE ABUTMENT ;
    PORT
      LAYER M5 ;
      RECT 65.040 2250.024 65.064 2250.216 ;
    END
  END d[250]
  PIN d[251]
    DIRECTION INPUT ;
    USE SIGNAL ;
    SHAPE ABUTMENT ;
    PORT
      LAYER M5 ;
      RECT 65.232 2250.024 65.256 2250.216 ;
    END
  END d[251]
  PIN d[252]
    DIRECTION INPUT ;
    USE SIGNAL ;
    SHAPE ABUTMENT ;
    PORT
      LAYER M5 ;
      RECT 65.424 2250.024 65.448 2250.216 ;
    END
  END d[252]
  PIN d[253]
    DIRECTION INPUT ;
    USE SIGNAL ;
    SHAPE ABUTMENT ;
    PORT
      LAYER M5 ;
      RECT 65.616 2250.024 65.640 2250.216 ;
    END
  END d[253]
  PIN d[254]
    DIRECTION INPUT ;
    USE SIGNAL ;
    SHAPE ABUTMENT ;
    PORT
      LAYER M5 ;
      RECT 65.856 2250.024 65.880 2250.216 ;
    END
  END d[254]
  PIN d[255]
    DIRECTION INPUT ;
    USE SIGNAL ;
    SHAPE ABUTMENT ;
    PORT
      LAYER M5 ;
      RECT 66.048 2250.024 66.072 2250.216 ;
    END
  END d[255]
  PIN d[256]
    DIRECTION INPUT ;
    USE SIGNAL ;
    SHAPE ABUTMENT ;
    PORT
      LAYER M5 ;
      RECT 66.240 2250.024 66.264 2250.216 ;
    END
  END d[256]
  PIN d[257]
    DIRECTION INPUT ;
    USE SIGNAL ;
    SHAPE ABUTMENT ;
    PORT
      LAYER M5 ;
      RECT 66.432 2250.024 66.456 2250.216 ;
    END
  END d[257]
  PIN d[258]
    DIRECTION INPUT ;
    USE SIGNAL ;
    SHAPE ABUTMENT ;
    PORT
      LAYER M5 ;
      RECT 66.672 2250.024 66.696 2250.216 ;
    END
  END d[258]
  PIN d[259]
    DIRECTION INPUT ;
    USE SIGNAL ;
    SHAPE ABUTMENT ;
    PORT
      LAYER M5 ;
      RECT 66.864 2250.024 66.888 2250.216 ;
    END
  END d[259]
  PIN d[260]
    DIRECTION INPUT ;
    USE SIGNAL ;
    SHAPE ABUTMENT ;
    PORT
      LAYER M5 ;
      RECT 67.056 2250.024 67.080 2250.216 ;
    END
  END d[260]
  PIN d[261]
    DIRECTION INPUT ;
    USE SIGNAL ;
    SHAPE ABUTMENT ;
    PORT
      LAYER M5 ;
      RECT 67.248 2250.024 67.272 2250.216 ;
    END
  END d[261]
  PIN d[262]
    DIRECTION INPUT ;
    USE SIGNAL ;
    SHAPE ABUTMENT ;
    PORT
      LAYER M5 ;
      RECT 67.440 2250.024 67.464 2250.216 ;
    END
  END d[262]
  PIN d[263]
    DIRECTION INPUT ;
    USE SIGNAL ;
    SHAPE ABUTMENT ;
    PORT
      LAYER M5 ;
      RECT 67.680 2250.024 67.704 2250.216 ;
    END
  END d[263]
  PIN d[264]
    DIRECTION INPUT ;
    USE SIGNAL ;
    SHAPE ABUTMENT ;
    PORT
      LAYER M5 ;
      RECT 67.872 2250.024 67.896 2250.216 ;
    END
  END d[264]
  PIN d[265]
    DIRECTION INPUT ;
    USE SIGNAL ;
    SHAPE ABUTMENT ;
    PORT
      LAYER M5 ;
      RECT 68.064 2250.024 68.088 2250.216 ;
    END
  END d[265]
  PIN d[266]
    DIRECTION INPUT ;
    USE SIGNAL ;
    SHAPE ABUTMENT ;
    PORT
      LAYER M5 ;
      RECT 68.256 2250.024 68.280 2250.216 ;
    END
  END d[266]
  PIN d[267]
    DIRECTION INPUT ;
    USE SIGNAL ;
    SHAPE ABUTMENT ;
    PORT
      LAYER M5 ;
      RECT 68.448 2250.024 68.472 2250.216 ;
    END
  END d[267]
  PIN d[268]
    DIRECTION INPUT ;
    USE SIGNAL ;
    SHAPE ABUTMENT ;
    PORT
      LAYER M5 ;
      RECT 68.688 2250.024 68.712 2250.216 ;
    END
  END d[268]
  PIN d[269]
    DIRECTION INPUT ;
    USE SIGNAL ;
    SHAPE ABUTMENT ;
    PORT
      LAYER M5 ;
      RECT 68.880 2250.024 68.904 2250.216 ;
    END
  END d[269]
  PIN d[270]
    DIRECTION INPUT ;
    USE SIGNAL ;
    SHAPE ABUTMENT ;
    PORT
      LAYER M5 ;
      RECT 69.072 2250.024 69.096 2250.216 ;
    END
  END d[270]
  PIN d[271]
    DIRECTION INPUT ;
    USE SIGNAL ;
    SHAPE ABUTMENT ;
    PORT
      LAYER M5 ;
      RECT 69.264 2250.024 69.288 2250.216 ;
    END
  END d[271]
  PIN d[272]
    DIRECTION INPUT ;
    USE SIGNAL ;
    SHAPE ABUTMENT ;
    PORT
      LAYER M5 ;
      RECT 69.504 2250.024 69.528 2250.216 ;
    END
  END d[272]
  PIN d[273]
    DIRECTION INPUT ;
    USE SIGNAL ;
    SHAPE ABUTMENT ;
    PORT
      LAYER M5 ;
      RECT 69.696 2250.024 69.720 2250.216 ;
    END
  END d[273]
  PIN d[274]
    DIRECTION INPUT ;
    USE SIGNAL ;
    SHAPE ABUTMENT ;
    PORT
      LAYER M5 ;
      RECT 69.888 2250.024 69.912 2250.216 ;
    END
  END d[274]
  PIN d[275]
    DIRECTION INPUT ;
    USE SIGNAL ;
    SHAPE ABUTMENT ;
    PORT
      LAYER M5 ;
      RECT 70.080 2250.024 70.104 2250.216 ;
    END
  END d[275]
  PIN d[276]
    DIRECTION INPUT ;
    USE SIGNAL ;
    SHAPE ABUTMENT ;
    PORT
      LAYER M5 ;
      RECT 70.272 2250.024 70.296 2250.216 ;
    END
  END d[276]
  PIN d[277]
    DIRECTION INPUT ;
    USE SIGNAL ;
    SHAPE ABUTMENT ;
    PORT
      LAYER M5 ;
      RECT 70.512 2250.024 70.536 2250.216 ;
    END
  END d[277]
  PIN d[278]
    DIRECTION INPUT ;
    USE SIGNAL ;
    SHAPE ABUTMENT ;
    PORT
      LAYER M5 ;
      RECT 70.704 2250.024 70.728 2250.216 ;
    END
  END d[278]
  PIN d[279]
    DIRECTION INPUT ;
    USE SIGNAL ;
    SHAPE ABUTMENT ;
    PORT
      LAYER M5 ;
      RECT 70.896 2250.024 70.920 2250.216 ;
    END
  END d[279]
  PIN d[280]
    DIRECTION INPUT ;
    USE SIGNAL ;
    SHAPE ABUTMENT ;
    PORT
      LAYER M5 ;
      RECT 71.088 2250.024 71.112 2250.216 ;
    END
  END d[280]
  PIN d[281]
    DIRECTION INPUT ;
    USE SIGNAL ;
    SHAPE ABUTMENT ;
    PORT
      LAYER M5 ;
      RECT 71.280 2250.024 71.304 2250.216 ;
    END
  END d[281]
  PIN d[282]
    DIRECTION INPUT ;
    USE SIGNAL ;
    SHAPE ABUTMENT ;
    PORT
      LAYER M5 ;
      RECT 71.520 2250.024 71.544 2250.216 ;
    END
  END d[282]
  PIN d[283]
    DIRECTION INPUT ;
    USE SIGNAL ;
    SHAPE ABUTMENT ;
    PORT
      LAYER M5 ;
      RECT 71.712 2250.024 71.736 2250.216 ;
    END
  END d[283]
  PIN d[284]
    DIRECTION INPUT ;
    USE SIGNAL ;
    SHAPE ABUTMENT ;
    PORT
      LAYER M5 ;
      RECT 71.904 2250.024 71.928 2250.216 ;
    END
  END d[284]
  PIN d[285]
    DIRECTION INPUT ;
    USE SIGNAL ;
    SHAPE ABUTMENT ;
    PORT
      LAYER M5 ;
      RECT 72.096 2250.024 72.120 2250.216 ;
    END
  END d[285]
  PIN d[286]
    DIRECTION INPUT ;
    USE SIGNAL ;
    SHAPE ABUTMENT ;
    PORT
      LAYER M5 ;
      RECT 72.288 2250.024 72.312 2250.216 ;
    END
  END d[286]
  PIN d[287]
    DIRECTION INPUT ;
    USE SIGNAL ;
    SHAPE ABUTMENT ;
    PORT
      LAYER M5 ;
      RECT 72.528 2250.024 72.552 2250.216 ;
    END
  END d[287]
  PIN d[288]
    DIRECTION INPUT ;
    USE SIGNAL ;
    SHAPE ABUTMENT ;
    PORT
      LAYER M5 ;
      RECT 72.720 2250.024 72.744 2250.216 ;
    END
  END d[288]
  PIN d[289]
    DIRECTION INPUT ;
    USE SIGNAL ;
    SHAPE ABUTMENT ;
    PORT
      LAYER M5 ;
      RECT 72.912 2250.024 72.936 2250.216 ;
    END
  END d[289]
  PIN d[290]
    DIRECTION INPUT ;
    USE SIGNAL ;
    SHAPE ABUTMENT ;
    PORT
      LAYER M5 ;
      RECT 73.104 2250.024 73.128 2250.216 ;
    END
  END d[290]
  PIN d[291]
    DIRECTION INPUT ;
    USE SIGNAL ;
    SHAPE ABUTMENT ;
    PORT
      LAYER M5 ;
      RECT 73.344 2250.024 73.368 2250.216 ;
    END
  END d[291]
  PIN d[292]
    DIRECTION INPUT ;
    USE SIGNAL ;
    SHAPE ABUTMENT ;
    PORT
      LAYER M5 ;
      RECT 73.536 2250.024 73.560 2250.216 ;
    END
  END d[292]
  PIN d[293]
    DIRECTION INPUT ;
    USE SIGNAL ;
    SHAPE ABUTMENT ;
    PORT
      LAYER M5 ;
      RECT 73.728 2250.024 73.752 2250.216 ;
    END
  END d[293]
  PIN d[294]
    DIRECTION INPUT ;
    USE SIGNAL ;
    SHAPE ABUTMENT ;
    PORT
      LAYER M5 ;
      RECT 73.920 2250.024 73.944 2250.216 ;
    END
  END d[294]
  PIN d[295]
    DIRECTION INPUT ;
    USE SIGNAL ;
    SHAPE ABUTMENT ;
    PORT
      LAYER M5 ;
      RECT 74.112 2250.024 74.136 2250.216 ;
    END
  END d[295]
  PIN d[296]
    DIRECTION INPUT ;
    USE SIGNAL ;
    SHAPE ABUTMENT ;
    PORT
      LAYER M5 ;
      RECT 74.352 2250.024 74.376 2250.216 ;
    END
  END d[296]
  PIN d[297]
    DIRECTION INPUT ;
    USE SIGNAL ;
    SHAPE ABUTMENT ;
    PORT
      LAYER M5 ;
      RECT 74.544 2250.024 74.568 2250.216 ;
    END
  END d[297]
  PIN d[298]
    DIRECTION INPUT ;
    USE SIGNAL ;
    SHAPE ABUTMENT ;
    PORT
      LAYER M5 ;
      RECT 74.736 2250.024 74.760 2250.216 ;
    END
  END d[298]
  PIN d[299]
    DIRECTION INPUT ;
    USE SIGNAL ;
    SHAPE ABUTMENT ;
    PORT
      LAYER M5 ;
      RECT 74.928 2250.024 74.952 2250.216 ;
    END
  END d[299]
  PIN d[300]
    DIRECTION INPUT ;
    USE SIGNAL ;
    SHAPE ABUTMENT ;
    PORT
      LAYER M5 ;
      RECT 75.120 2250.024 75.144 2250.216 ;
    END
  END d[300]
  PIN d[301]
    DIRECTION INPUT ;
    USE SIGNAL ;
    SHAPE ABUTMENT ;
    PORT
      LAYER M5 ;
      RECT 75.360 2250.024 75.384 2250.216 ;
    END
  END d[301]
  PIN d[302]
    DIRECTION INPUT ;
    USE SIGNAL ;
    SHAPE ABUTMENT ;
    PORT
      LAYER M5 ;
      RECT 75.552 2250.024 75.576 2250.216 ;
    END
  END d[302]
  PIN d[303]
    DIRECTION INPUT ;
    USE SIGNAL ;
    SHAPE ABUTMENT ;
    PORT
      LAYER M5 ;
      RECT 75.744 2250.024 75.768 2250.216 ;
    END
  END d[303]
  PIN d[304]
    DIRECTION INPUT ;
    USE SIGNAL ;
    SHAPE ABUTMENT ;
    PORT
      LAYER M5 ;
      RECT 75.936 2250.024 75.960 2250.216 ;
    END
  END d[304]
  PIN d[305]
    DIRECTION INPUT ;
    USE SIGNAL ;
    SHAPE ABUTMENT ;
    PORT
      LAYER M5 ;
      RECT 76.176 2250.024 76.200 2250.216 ;
    END
  END d[305]
  PIN d[306]
    DIRECTION INPUT ;
    USE SIGNAL ;
    SHAPE ABUTMENT ;
    PORT
      LAYER M5 ;
      RECT 76.368 2250.024 76.392 2250.216 ;
    END
  END d[306]
  PIN d[307]
    DIRECTION INPUT ;
    USE SIGNAL ;
    SHAPE ABUTMENT ;
    PORT
      LAYER M5 ;
      RECT 76.560 2250.024 76.584 2250.216 ;
    END
  END d[307]
  PIN d[308]
    DIRECTION INPUT ;
    USE SIGNAL ;
    SHAPE ABUTMENT ;
    PORT
      LAYER M5 ;
      RECT 76.752 2250.024 76.776 2250.216 ;
    END
  END d[308]
  PIN d[309]
    DIRECTION INPUT ;
    USE SIGNAL ;
    SHAPE ABUTMENT ;
    PORT
      LAYER M5 ;
      RECT 76.944 2250.024 76.968 2250.216 ;
    END
  END d[309]
  PIN d[310]
    DIRECTION INPUT ;
    USE SIGNAL ;
    SHAPE ABUTMENT ;
    PORT
      LAYER M5 ;
      RECT 77.184 2250.024 77.208 2250.216 ;
    END
  END d[310]
  PIN d[311]
    DIRECTION INPUT ;
    USE SIGNAL ;
    SHAPE ABUTMENT ;
    PORT
      LAYER M5 ;
      RECT 77.376 2250.024 77.400 2250.216 ;
    END
  END d[311]
  PIN d[312]
    DIRECTION INPUT ;
    USE SIGNAL ;
    SHAPE ABUTMENT ;
    PORT
      LAYER M5 ;
      RECT 77.568 2250.024 77.592 2250.216 ;
    END
  END d[312]
  PIN d[313]
    DIRECTION INPUT ;
    USE SIGNAL ;
    SHAPE ABUTMENT ;
    PORT
      LAYER M5 ;
      RECT 77.760 2250.024 77.784 2250.216 ;
    END
  END d[313]
  PIN d[314]
    DIRECTION INPUT ;
    USE SIGNAL ;
    SHAPE ABUTMENT ;
    PORT
      LAYER M5 ;
      RECT 77.952 2250.024 77.976 2250.216 ;
    END
  END d[314]
  PIN d[315]
    DIRECTION INPUT ;
    USE SIGNAL ;
    SHAPE ABUTMENT ;
    PORT
      LAYER M5 ;
      RECT 78.192 2250.024 78.216 2250.216 ;
    END
  END d[315]
  PIN d[316]
    DIRECTION INPUT ;
    USE SIGNAL ;
    SHAPE ABUTMENT ;
    PORT
      LAYER M5 ;
      RECT 78.384 2250.024 78.408 2250.216 ;
    END
  END d[316]
  PIN d[317]
    DIRECTION INPUT ;
    USE SIGNAL ;
    SHAPE ABUTMENT ;
    PORT
      LAYER M5 ;
      RECT 78.576 2250.024 78.600 2250.216 ;
    END
  END d[317]
  PIN d[318]
    DIRECTION INPUT ;
    USE SIGNAL ;
    SHAPE ABUTMENT ;
    PORT
      LAYER M5 ;
      RECT 78.768 2250.024 78.792 2250.216 ;
    END
  END d[318]
  PIN d[319]
    DIRECTION INPUT ;
    USE SIGNAL ;
    SHAPE ABUTMENT ;
    PORT
      LAYER M5 ;
      RECT 79.008 2250.024 79.032 2250.216 ;
    END
  END d[319]
  PIN d[320]
    DIRECTION INPUT ;
    USE SIGNAL ;
    SHAPE ABUTMENT ;
    PORT
      LAYER M5 ;
      RECT 79.200 2250.024 79.224 2250.216 ;
    END
  END d[320]
  PIN d[321]
    DIRECTION INPUT ;
    USE SIGNAL ;
    SHAPE ABUTMENT ;
    PORT
      LAYER M5 ;
      RECT 79.392 2250.024 79.416 2250.216 ;
    END
  END d[321]
  PIN d[322]
    DIRECTION INPUT ;
    USE SIGNAL ;
    SHAPE ABUTMENT ;
    PORT
      LAYER M5 ;
      RECT 79.584 2250.024 79.608 2250.216 ;
    END
  END d[322]
  PIN d[323]
    DIRECTION INPUT ;
    USE SIGNAL ;
    SHAPE ABUTMENT ;
    PORT
      LAYER M5 ;
      RECT 79.776 2250.024 79.800 2250.216 ;
    END
  END d[323]
  PIN d[324]
    DIRECTION INPUT ;
    USE SIGNAL ;
    SHAPE ABUTMENT ;
    PORT
      LAYER M5 ;
      RECT 80.016 2250.024 80.040 2250.216 ;
    END
  END d[324]
  PIN d[325]
    DIRECTION INPUT ;
    USE SIGNAL ;
    SHAPE ABUTMENT ;
    PORT
      LAYER M5 ;
      RECT 80.208 2250.024 80.232 2250.216 ;
    END
  END d[325]
  PIN d[326]
    DIRECTION INPUT ;
    USE SIGNAL ;
    SHAPE ABUTMENT ;
    PORT
      LAYER M5 ;
      RECT 80.400 2250.024 80.424 2250.216 ;
    END
  END d[326]
  PIN d[327]
    DIRECTION INPUT ;
    USE SIGNAL ;
    SHAPE ABUTMENT ;
    PORT
      LAYER M5 ;
      RECT 80.592 2250.024 80.616 2250.216 ;
    END
  END d[327]
  PIN d[328]
    DIRECTION INPUT ;
    USE SIGNAL ;
    SHAPE ABUTMENT ;
    PORT
      LAYER M5 ;
      RECT 80.784 2250.024 80.808 2250.216 ;
    END
  END d[328]
  PIN d[329]
    DIRECTION INPUT ;
    USE SIGNAL ;
    SHAPE ABUTMENT ;
    PORT
      LAYER M5 ;
      RECT 81.024 2250.024 81.048 2250.216 ;
    END
  END d[329]
  PIN d[330]
    DIRECTION INPUT ;
    USE SIGNAL ;
    SHAPE ABUTMENT ;
    PORT
      LAYER M5 ;
      RECT 81.216 2250.024 81.240 2250.216 ;
    END
  END d[330]
  PIN d[331]
    DIRECTION INPUT ;
    USE SIGNAL ;
    SHAPE ABUTMENT ;
    PORT
      LAYER M5 ;
      RECT 81.408 2250.024 81.432 2250.216 ;
    END
  END d[331]
  PIN d[332]
    DIRECTION INPUT ;
    USE SIGNAL ;
    SHAPE ABUTMENT ;
    PORT
      LAYER M5 ;
      RECT 81.600 2250.024 81.624 2250.216 ;
    END
  END d[332]
  PIN d[333]
    DIRECTION INPUT ;
    USE SIGNAL ;
    SHAPE ABUTMENT ;
    PORT
      LAYER M5 ;
      RECT 81.840 2250.024 81.864 2250.216 ;
    END
  END d[333]
  PIN d[334]
    DIRECTION INPUT ;
    USE SIGNAL ;
    SHAPE ABUTMENT ;
    PORT
      LAYER M5 ;
      RECT 82.032 2250.024 82.056 2250.216 ;
    END
  END d[334]
  PIN d[335]
    DIRECTION INPUT ;
    USE SIGNAL ;
    SHAPE ABUTMENT ;
    PORT
      LAYER M5 ;
      RECT 82.224 2250.024 82.248 2250.216 ;
    END
  END d[335]
  PIN d[336]
    DIRECTION INPUT ;
    USE SIGNAL ;
    SHAPE ABUTMENT ;
    PORT
      LAYER M5 ;
      RECT 82.416 2250.024 82.440 2250.216 ;
    END
  END d[336]
  PIN d[337]
    DIRECTION INPUT ;
    USE SIGNAL ;
    SHAPE ABUTMENT ;
    PORT
      LAYER M5 ;
      RECT 82.608 2250.024 82.632 2250.216 ;
    END
  END d[337]
  PIN d[338]
    DIRECTION INPUT ;
    USE SIGNAL ;
    SHAPE ABUTMENT ;
    PORT
      LAYER M5 ;
      RECT 82.848 2250.024 82.872 2250.216 ;
    END
  END d[338]
  PIN d[339]
    DIRECTION INPUT ;
    USE SIGNAL ;
    SHAPE ABUTMENT ;
    PORT
      LAYER M5 ;
      RECT 83.040 2250.024 83.064 2250.216 ;
    END
  END d[339]
  PIN d[340]
    DIRECTION INPUT ;
    USE SIGNAL ;
    SHAPE ABUTMENT ;
    PORT
      LAYER M5 ;
      RECT 83.232 2250.024 83.256 2250.216 ;
    END
  END d[340]
  PIN d[341]
    DIRECTION INPUT ;
    USE SIGNAL ;
    SHAPE ABUTMENT ;
    PORT
      LAYER M5 ;
      RECT 83.424 2250.024 83.448 2250.216 ;
    END
  END d[341]
  PIN d[342]
    DIRECTION INPUT ;
    USE SIGNAL ;
    SHAPE ABUTMENT ;
    PORT
      LAYER M5 ;
      RECT 83.616 2250.024 83.640 2250.216 ;
    END
  END d[342]
  PIN d[343]
    DIRECTION INPUT ;
    USE SIGNAL ;
    SHAPE ABUTMENT ;
    PORT
      LAYER M5 ;
      RECT 83.856 2250.024 83.880 2250.216 ;
    END
  END d[343]
  PIN d[344]
    DIRECTION INPUT ;
    USE SIGNAL ;
    SHAPE ABUTMENT ;
    PORT
      LAYER M5 ;
      RECT 84.048 2250.024 84.072 2250.216 ;
    END
  END d[344]
  PIN d[345]
    DIRECTION INPUT ;
    USE SIGNAL ;
    SHAPE ABUTMENT ;
    PORT
      LAYER M5 ;
      RECT 84.240 2250.024 84.264 2250.216 ;
    END
  END d[345]
  PIN d[346]
    DIRECTION INPUT ;
    USE SIGNAL ;
    SHAPE ABUTMENT ;
    PORT
      LAYER M5 ;
      RECT 84.432 2250.024 84.456 2250.216 ;
    END
  END d[346]
  PIN d[347]
    DIRECTION INPUT ;
    USE SIGNAL ;
    SHAPE ABUTMENT ;
    PORT
      LAYER M5 ;
      RECT 84.624 2250.024 84.648 2250.216 ;
    END
  END d[347]
  PIN d[348]
    DIRECTION INPUT ;
    USE SIGNAL ;
    SHAPE ABUTMENT ;
    PORT
      LAYER M5 ;
      RECT 84.864 2250.024 84.888 2250.216 ;
    END
  END d[348]
  PIN d[349]
    DIRECTION INPUT ;
    USE SIGNAL ;
    SHAPE ABUTMENT ;
    PORT
      LAYER M5 ;
      RECT 85.056 2250.024 85.080 2250.216 ;
    END
  END d[349]
  PIN d[350]
    DIRECTION INPUT ;
    USE SIGNAL ;
    SHAPE ABUTMENT ;
    PORT
      LAYER M5 ;
      RECT 85.248 2250.024 85.272 2250.216 ;
    END
  END d[350]
  PIN d[351]
    DIRECTION INPUT ;
    USE SIGNAL ;
    SHAPE ABUTMENT ;
    PORT
      LAYER M5 ;
      RECT 85.440 2250.024 85.464 2250.216 ;
    END
  END d[351]
  PIN d[352]
    DIRECTION INPUT ;
    USE SIGNAL ;
    SHAPE ABUTMENT ;
    PORT
      LAYER M5 ;
      RECT 85.680 2250.024 85.704 2250.216 ;
    END
  END d[352]
  PIN d[353]
    DIRECTION INPUT ;
    USE SIGNAL ;
    SHAPE ABUTMENT ;
    PORT
      LAYER M5 ;
      RECT 85.872 2250.024 85.896 2250.216 ;
    END
  END d[353]
  PIN d[354]
    DIRECTION INPUT ;
    USE SIGNAL ;
    SHAPE ABUTMENT ;
    PORT
      LAYER M5 ;
      RECT 86.064 2250.024 86.088 2250.216 ;
    END
  END d[354]
  PIN d[355]
    DIRECTION INPUT ;
    USE SIGNAL ;
    SHAPE ABUTMENT ;
    PORT
      LAYER M5 ;
      RECT 86.256 2250.024 86.280 2250.216 ;
    END
  END d[355]
  PIN d[356]
    DIRECTION INPUT ;
    USE SIGNAL ;
    SHAPE ABUTMENT ;
    PORT
      LAYER M5 ;
      RECT 86.448 2250.024 86.472 2250.216 ;
    END
  END d[356]
  PIN d[357]
    DIRECTION INPUT ;
    USE SIGNAL ;
    SHAPE ABUTMENT ;
    PORT
      LAYER M5 ;
      RECT 86.688 2250.024 86.712 2250.216 ;
    END
  END d[357]
  PIN d[358]
    DIRECTION INPUT ;
    USE SIGNAL ;
    SHAPE ABUTMENT ;
    PORT
      LAYER M5 ;
      RECT 86.880 2250.024 86.904 2250.216 ;
    END
  END d[358]
  PIN d[359]
    DIRECTION INPUT ;
    USE SIGNAL ;
    SHAPE ABUTMENT ;
    PORT
      LAYER M5 ;
      RECT 87.072 2250.024 87.096 2250.216 ;
    END
  END d[359]
  PIN d[360]
    DIRECTION INPUT ;
    USE SIGNAL ;
    SHAPE ABUTMENT ;
    PORT
      LAYER M5 ;
      RECT 87.264 2250.024 87.288 2250.216 ;
    END
  END d[360]
  PIN d[361]
    DIRECTION INPUT ;
    USE SIGNAL ;
    SHAPE ABUTMENT ;
    PORT
      LAYER M5 ;
      RECT 87.456 2250.024 87.480 2250.216 ;
    END
  END d[361]
  PIN d[362]
    DIRECTION INPUT ;
    USE SIGNAL ;
    SHAPE ABUTMENT ;
    PORT
      LAYER M5 ;
      RECT 87.696 2250.024 87.720 2250.216 ;
    END
  END d[362]
  PIN d[363]
    DIRECTION INPUT ;
    USE SIGNAL ;
    SHAPE ABUTMENT ;
    PORT
      LAYER M5 ;
      RECT 87.888 2250.024 87.912 2250.216 ;
    END
  END d[363]
  PIN d[364]
    DIRECTION INPUT ;
    USE SIGNAL ;
    SHAPE ABUTMENT ;
    PORT
      LAYER M5 ;
      RECT 88.080 2250.024 88.104 2250.216 ;
    END
  END d[364]
  PIN d[365]
    DIRECTION INPUT ;
    USE SIGNAL ;
    SHAPE ABUTMENT ;
    PORT
      LAYER M5 ;
      RECT 88.272 2250.024 88.296 2250.216 ;
    END
  END d[365]
  PIN d[366]
    DIRECTION INPUT ;
    USE SIGNAL ;
    SHAPE ABUTMENT ;
    PORT
      LAYER M5 ;
      RECT 88.512 2250.024 88.536 2250.216 ;
    END
  END d[366]
  PIN d[367]
    DIRECTION INPUT ;
    USE SIGNAL ;
    SHAPE ABUTMENT ;
    PORT
      LAYER M5 ;
      RECT 88.704 2250.024 88.728 2250.216 ;
    END
  END d[367]
  PIN d[368]
    DIRECTION INPUT ;
    USE SIGNAL ;
    SHAPE ABUTMENT ;
    PORT
      LAYER M5 ;
      RECT 88.896 2250.024 88.920 2250.216 ;
    END
  END d[368]
  PIN d[369]
    DIRECTION INPUT ;
    USE SIGNAL ;
    SHAPE ABUTMENT ;
    PORT
      LAYER M5 ;
      RECT 89.088 2250.024 89.112 2250.216 ;
    END
  END d[369]
  PIN d[370]
    DIRECTION INPUT ;
    USE SIGNAL ;
    SHAPE ABUTMENT ;
    PORT
      LAYER M5 ;
      RECT 89.280 2250.024 89.304 2250.216 ;
    END
  END d[370]
  PIN d[371]
    DIRECTION INPUT ;
    USE SIGNAL ;
    SHAPE ABUTMENT ;
    PORT
      LAYER M5 ;
      RECT 89.520 2250.024 89.544 2250.216 ;
    END
  END d[371]
  PIN d[372]
    DIRECTION INPUT ;
    USE SIGNAL ;
    SHAPE ABUTMENT ;
    PORT
      LAYER M5 ;
      RECT 89.712 2250.024 89.736 2250.216 ;
    END
  END d[372]
  PIN d[373]
    DIRECTION INPUT ;
    USE SIGNAL ;
    SHAPE ABUTMENT ;
    PORT
      LAYER M5 ;
      RECT 89.904 2250.024 89.928 2250.216 ;
    END
  END d[373]
  PIN d[374]
    DIRECTION INPUT ;
    USE SIGNAL ;
    SHAPE ABUTMENT ;
    PORT
      LAYER M5 ;
      RECT 90.096 2250.024 90.120 2250.216 ;
    END
  END d[374]
  PIN d[375]
    DIRECTION INPUT ;
    USE SIGNAL ;
    SHAPE ABUTMENT ;
    PORT
      LAYER M5 ;
      RECT 90.288 2250.024 90.312 2250.216 ;
    END
  END d[375]
  PIN d[376]
    DIRECTION INPUT ;
    USE SIGNAL ;
    SHAPE ABUTMENT ;
    PORT
      LAYER M5 ;
      RECT 90.528 2250.024 90.552 2250.216 ;
    END
  END d[376]
  PIN d[377]
    DIRECTION INPUT ;
    USE SIGNAL ;
    SHAPE ABUTMENT ;
    PORT
      LAYER M5 ;
      RECT 90.720 2250.024 90.744 2250.216 ;
    END
  END d[377]
  PIN d[378]
    DIRECTION INPUT ;
    USE SIGNAL ;
    SHAPE ABUTMENT ;
    PORT
      LAYER M5 ;
      RECT 90.912 2250.024 90.936 2250.216 ;
    END
  END d[378]
  PIN d[379]
    DIRECTION INPUT ;
    USE SIGNAL ;
    SHAPE ABUTMENT ;
    PORT
      LAYER M5 ;
      RECT 91.104 2250.024 91.128 2250.216 ;
    END
  END d[379]
  PIN d[380]
    DIRECTION INPUT ;
    USE SIGNAL ;
    SHAPE ABUTMENT ;
    PORT
      LAYER M5 ;
      RECT 91.344 2250.024 91.368 2250.216 ;
    END
  END d[380]
  PIN d[381]
    DIRECTION INPUT ;
    USE SIGNAL ;
    SHAPE ABUTMENT ;
    PORT
      LAYER M5 ;
      RECT 91.536 2250.024 91.560 2250.216 ;
    END
  END d[381]
  PIN d[382]
    DIRECTION INPUT ;
    USE SIGNAL ;
    SHAPE ABUTMENT ;
    PORT
      LAYER M5 ;
      RECT 91.728 2250.024 91.752 2250.216 ;
    END
  END d[382]
  PIN d[383]
    DIRECTION INPUT ;
    USE SIGNAL ;
    SHAPE ABUTMENT ;
    PORT
      LAYER M5 ;
      RECT 91.920 2250.024 91.944 2250.216 ;
    END
  END d[383]
  PIN d[384]
    DIRECTION INPUT ;
    USE SIGNAL ;
    SHAPE ABUTMENT ;
    PORT
      LAYER M5 ;
      RECT 92.112 2250.024 92.136 2250.216 ;
    END
  END d[384]
  PIN d[385]
    DIRECTION INPUT ;
    USE SIGNAL ;
    SHAPE ABUTMENT ;
    PORT
      LAYER M5 ;
      RECT 92.352 2250.024 92.376 2250.216 ;
    END
  END d[385]
  PIN d[386]
    DIRECTION INPUT ;
    USE SIGNAL ;
    SHAPE ABUTMENT ;
    PORT
      LAYER M5 ;
      RECT 92.544 2250.024 92.568 2250.216 ;
    END
  END d[386]
  PIN d[387]
    DIRECTION INPUT ;
    USE SIGNAL ;
    SHAPE ABUTMENT ;
    PORT
      LAYER M5 ;
      RECT 92.736 2250.024 92.760 2250.216 ;
    END
  END d[387]
  PIN d[388]
    DIRECTION INPUT ;
    USE SIGNAL ;
    SHAPE ABUTMENT ;
    PORT
      LAYER M5 ;
      RECT 92.928 2250.024 92.952 2250.216 ;
    END
  END d[388]
  PIN d[389]
    DIRECTION INPUT ;
    USE SIGNAL ;
    SHAPE ABUTMENT ;
    PORT
      LAYER M5 ;
      RECT 93.120 2250.024 93.144 2250.216 ;
    END
  END d[389]
  PIN d[390]
    DIRECTION INPUT ;
    USE SIGNAL ;
    SHAPE ABUTMENT ;
    PORT
      LAYER M5 ;
      RECT 93.360 2250.024 93.384 2250.216 ;
    END
  END d[390]
  PIN d[391]
    DIRECTION INPUT ;
    USE SIGNAL ;
    SHAPE ABUTMENT ;
    PORT
      LAYER M5 ;
      RECT 93.552 2250.024 93.576 2250.216 ;
    END
  END d[391]
  PIN d[392]
    DIRECTION INPUT ;
    USE SIGNAL ;
    SHAPE ABUTMENT ;
    PORT
      LAYER M5 ;
      RECT 93.744 2250.024 93.768 2250.216 ;
    END
  END d[392]
  PIN d[393]
    DIRECTION INPUT ;
    USE SIGNAL ;
    SHAPE ABUTMENT ;
    PORT
      LAYER M5 ;
      RECT 93.936 2250.024 93.960 2250.216 ;
    END
  END d[393]
  PIN d[394]
    DIRECTION INPUT ;
    USE SIGNAL ;
    SHAPE ABUTMENT ;
    PORT
      LAYER M5 ;
      RECT 94.176 2250.024 94.200 2250.216 ;
    END
  END d[394]
  PIN d[395]
    DIRECTION INPUT ;
    USE SIGNAL ;
    SHAPE ABUTMENT ;
    PORT
      LAYER M5 ;
      RECT 94.368 2250.024 94.392 2250.216 ;
    END
  END d[395]
  PIN d[396]
    DIRECTION INPUT ;
    USE SIGNAL ;
    SHAPE ABUTMENT ;
    PORT
      LAYER M5 ;
      RECT 94.560 2250.024 94.584 2250.216 ;
    END
  END d[396]
  PIN d[397]
    DIRECTION INPUT ;
    USE SIGNAL ;
    SHAPE ABUTMENT ;
    PORT
      LAYER M5 ;
      RECT 94.752 2250.024 94.776 2250.216 ;
    END
  END d[397]
  PIN d[398]
    DIRECTION INPUT ;
    USE SIGNAL ;
    SHAPE ABUTMENT ;
    PORT
      LAYER M5 ;
      RECT 94.944 2250.024 94.968 2250.216 ;
    END
  END d[398]
  PIN d[399]
    DIRECTION INPUT ;
    USE SIGNAL ;
    SHAPE ABUTMENT ;
    PORT
      LAYER M5 ;
      RECT 95.184 2250.024 95.208 2250.216 ;
    END
  END d[399]
  PIN d[400]
    DIRECTION INPUT ;
    USE SIGNAL ;
    SHAPE ABUTMENT ;
    PORT
      LAYER M5 ;
      RECT 95.376 2250.024 95.400 2250.216 ;
    END
  END d[400]
  PIN d[401]
    DIRECTION INPUT ;
    USE SIGNAL ;
    SHAPE ABUTMENT ;
    PORT
      LAYER M5 ;
      RECT 95.568 2250.024 95.592 2250.216 ;
    END
  END d[401]
  PIN d[402]
    DIRECTION INPUT ;
    USE SIGNAL ;
    SHAPE ABUTMENT ;
    PORT
      LAYER M5 ;
      RECT 95.760 2250.024 95.784 2250.216 ;
    END
  END d[402]
  PIN d[403]
    DIRECTION INPUT ;
    USE SIGNAL ;
    SHAPE ABUTMENT ;
    PORT
      LAYER M5 ;
      RECT 95.952 2250.024 95.976 2250.216 ;
    END
  END d[403]
  PIN d[404]
    DIRECTION INPUT ;
    USE SIGNAL ;
    SHAPE ABUTMENT ;
    PORT
      LAYER M5 ;
      RECT 96.192 2250.024 96.216 2250.216 ;
    END
  END d[404]
  PIN d[405]
    DIRECTION INPUT ;
    USE SIGNAL ;
    SHAPE ABUTMENT ;
    PORT
      LAYER M5 ;
      RECT 96.384 2250.024 96.408 2250.216 ;
    END
  END d[405]
  PIN d[406]
    DIRECTION INPUT ;
    USE SIGNAL ;
    SHAPE ABUTMENT ;
    PORT
      LAYER M5 ;
      RECT 96.576 2250.024 96.600 2250.216 ;
    END
  END d[406]
  PIN d[407]
    DIRECTION INPUT ;
    USE SIGNAL ;
    SHAPE ABUTMENT ;
    PORT
      LAYER M5 ;
      RECT 96.768 2250.024 96.792 2250.216 ;
    END
  END d[407]
  PIN d[408]
    DIRECTION INPUT ;
    USE SIGNAL ;
    SHAPE ABUTMENT ;
    PORT
      LAYER M5 ;
      RECT 96.960 2250.024 96.984 2250.216 ;
    END
  END d[408]
  PIN d[409]
    DIRECTION INPUT ;
    USE SIGNAL ;
    SHAPE ABUTMENT ;
    PORT
      LAYER M5 ;
      RECT 97.200 2250.024 97.224 2250.216 ;
    END
  END d[409]
  PIN d[410]
    DIRECTION INPUT ;
    USE SIGNAL ;
    SHAPE ABUTMENT ;
    PORT
      LAYER M5 ;
      RECT 97.392 2250.024 97.416 2250.216 ;
    END
  END d[410]
  PIN d[411]
    DIRECTION INPUT ;
    USE SIGNAL ;
    SHAPE ABUTMENT ;
    PORT
      LAYER M5 ;
      RECT 97.584 2250.024 97.608 2250.216 ;
    END
  END d[411]
  PIN d[412]
    DIRECTION INPUT ;
    USE SIGNAL ;
    SHAPE ABUTMENT ;
    PORT
      LAYER M5 ;
      RECT 97.776 2250.024 97.800 2250.216 ;
    END
  END d[412]
  PIN d[413]
    DIRECTION INPUT ;
    USE SIGNAL ;
    SHAPE ABUTMENT ;
    PORT
      LAYER M5 ;
      RECT 98.016 2250.024 98.040 2250.216 ;
    END
  END d[413]
  PIN d[414]
    DIRECTION INPUT ;
    USE SIGNAL ;
    SHAPE ABUTMENT ;
    PORT
      LAYER M5 ;
      RECT 98.208 2250.024 98.232 2250.216 ;
    END
  END d[414]
  PIN d[415]
    DIRECTION INPUT ;
    USE SIGNAL ;
    SHAPE ABUTMENT ;
    PORT
      LAYER M5 ;
      RECT 98.400 2250.024 98.424 2250.216 ;
    END
  END d[415]
  PIN d[416]
    DIRECTION INPUT ;
    USE SIGNAL ;
    SHAPE ABUTMENT ;
    PORT
      LAYER M5 ;
      RECT 98.592 2250.024 98.616 2250.216 ;
    END
  END d[416]
  PIN d[417]
    DIRECTION INPUT ;
    USE SIGNAL ;
    SHAPE ABUTMENT ;
    PORT
      LAYER M5 ;
      RECT 98.784 2250.024 98.808 2250.216 ;
    END
  END d[417]
  PIN d[418]
    DIRECTION INPUT ;
    USE SIGNAL ;
    SHAPE ABUTMENT ;
    PORT
      LAYER M5 ;
      RECT 99.024 2250.024 99.048 2250.216 ;
    END
  END d[418]
  PIN d[419]
    DIRECTION INPUT ;
    USE SIGNAL ;
    SHAPE ABUTMENT ;
    PORT
      LAYER M5 ;
      RECT 99.216 2250.024 99.240 2250.216 ;
    END
  END d[419]
  PIN d[420]
    DIRECTION INPUT ;
    USE SIGNAL ;
    SHAPE ABUTMENT ;
    PORT
      LAYER M5 ;
      RECT 99.408 2250.024 99.432 2250.216 ;
    END
  END d[420]
  PIN d[421]
    DIRECTION INPUT ;
    USE SIGNAL ;
    SHAPE ABUTMENT ;
    PORT
      LAYER M5 ;
      RECT 99.600 2250.024 99.624 2250.216 ;
    END
  END d[421]
  PIN d[422]
    DIRECTION INPUT ;
    USE SIGNAL ;
    SHAPE ABUTMENT ;
    PORT
      LAYER M5 ;
      RECT 99.792 2250.024 99.816 2250.216 ;
    END
  END d[422]
  PIN d[423]
    DIRECTION INPUT ;
    USE SIGNAL ;
    SHAPE ABUTMENT ;
    PORT
      LAYER M5 ;
      RECT 100.032 2250.024 100.056 2250.216 ;
    END
  END d[423]
  PIN d[424]
    DIRECTION INPUT ;
    USE SIGNAL ;
    SHAPE ABUTMENT ;
    PORT
      LAYER M5 ;
      RECT 100.224 2250.024 100.248 2250.216 ;
    END
  END d[424]
  PIN d[425]
    DIRECTION INPUT ;
    USE SIGNAL ;
    SHAPE ABUTMENT ;
    PORT
      LAYER M5 ;
      RECT 100.416 2250.024 100.440 2250.216 ;
    END
  END d[425]
  PIN d[426]
    DIRECTION INPUT ;
    USE SIGNAL ;
    SHAPE ABUTMENT ;
    PORT
      LAYER M5 ;
      RECT 100.608 2250.024 100.632 2250.216 ;
    END
  END d[426]
  PIN d[427]
    DIRECTION INPUT ;
    USE SIGNAL ;
    SHAPE ABUTMENT ;
    PORT
      LAYER M5 ;
      RECT 100.848 2250.024 100.872 2250.216 ;
    END
  END d[427]
  PIN d[428]
    DIRECTION INPUT ;
    USE SIGNAL ;
    SHAPE ABUTMENT ;
    PORT
      LAYER M5 ;
      RECT 101.040 2250.024 101.064 2250.216 ;
    END
  END d[428]
  PIN d[429]
    DIRECTION INPUT ;
    USE SIGNAL ;
    SHAPE ABUTMENT ;
    PORT
      LAYER M5 ;
      RECT 101.232 2250.024 101.256 2250.216 ;
    END
  END d[429]
  PIN d[430]
    DIRECTION INPUT ;
    USE SIGNAL ;
    SHAPE ABUTMENT ;
    PORT
      LAYER M5 ;
      RECT 101.424 2250.024 101.448 2250.216 ;
    END
  END d[430]
  PIN d[431]
    DIRECTION INPUT ;
    USE SIGNAL ;
    SHAPE ABUTMENT ;
    PORT
      LAYER M5 ;
      RECT 101.616 2250.024 101.640 2250.216 ;
    END
  END d[431]
  PIN d[432]
    DIRECTION INPUT ;
    USE SIGNAL ;
    SHAPE ABUTMENT ;
    PORT
      LAYER M5 ;
      RECT 101.856 2250.024 101.880 2250.216 ;
    END
  END d[432]
  PIN d[433]
    DIRECTION INPUT ;
    USE SIGNAL ;
    SHAPE ABUTMENT ;
    PORT
      LAYER M5 ;
      RECT 102.048 2250.024 102.072 2250.216 ;
    END
  END d[433]
  PIN d[434]
    DIRECTION INPUT ;
    USE SIGNAL ;
    SHAPE ABUTMENT ;
    PORT
      LAYER M5 ;
      RECT 102.240 2250.024 102.264 2250.216 ;
    END
  END d[434]
  PIN d[435]
    DIRECTION INPUT ;
    USE SIGNAL ;
    SHAPE ABUTMENT ;
    PORT
      LAYER M5 ;
      RECT 102.432 2250.024 102.456 2250.216 ;
    END
  END d[435]
  PIN d[436]
    DIRECTION INPUT ;
    USE SIGNAL ;
    SHAPE ABUTMENT ;
    PORT
      LAYER M5 ;
      RECT 102.624 2250.024 102.648 2250.216 ;
    END
  END d[436]
  PIN d[437]
    DIRECTION INPUT ;
    USE SIGNAL ;
    SHAPE ABUTMENT ;
    PORT
      LAYER M5 ;
      RECT 102.864 2250.024 102.888 2250.216 ;
    END
  END d[437]
  PIN d[438]
    DIRECTION INPUT ;
    USE SIGNAL ;
    SHAPE ABUTMENT ;
    PORT
      LAYER M5 ;
      RECT 103.056 2250.024 103.080 2250.216 ;
    END
  END d[438]
  PIN d[439]
    DIRECTION INPUT ;
    USE SIGNAL ;
    SHAPE ABUTMENT ;
    PORT
      LAYER M5 ;
      RECT 103.248 2250.024 103.272 2250.216 ;
    END
  END d[439]
  PIN d[440]
    DIRECTION INPUT ;
    USE SIGNAL ;
    SHAPE ABUTMENT ;
    PORT
      LAYER M5 ;
      RECT 103.440 2250.024 103.464 2250.216 ;
    END
  END d[440]
  PIN d[441]
    DIRECTION INPUT ;
    USE SIGNAL ;
    SHAPE ABUTMENT ;
    PORT
      LAYER M5 ;
      RECT 103.680 2250.024 103.704 2250.216 ;
    END
  END d[441]
  PIN d[442]
    DIRECTION INPUT ;
    USE SIGNAL ;
    SHAPE ABUTMENT ;
    PORT
      LAYER M5 ;
      RECT 103.872 2250.024 103.896 2250.216 ;
    END
  END d[442]
  PIN d[443]
    DIRECTION INPUT ;
    USE SIGNAL ;
    SHAPE ABUTMENT ;
    PORT
      LAYER M5 ;
      RECT 104.064 2250.024 104.088 2250.216 ;
    END
  END d[443]
  PIN d[444]
    DIRECTION INPUT ;
    USE SIGNAL ;
    SHAPE ABUTMENT ;
    PORT
      LAYER M5 ;
      RECT 104.256 2250.024 104.280 2250.216 ;
    END
  END d[444]
  PIN d[445]
    DIRECTION INPUT ;
    USE SIGNAL ;
    SHAPE ABUTMENT ;
    PORT
      LAYER M5 ;
      RECT 104.448 2250.024 104.472 2250.216 ;
    END
  END d[445]
  PIN d[446]
    DIRECTION INPUT ;
    USE SIGNAL ;
    SHAPE ABUTMENT ;
    PORT
      LAYER M5 ;
      RECT 104.688 2250.024 104.712 2250.216 ;
    END
  END d[446]
  PIN d[447]
    DIRECTION INPUT ;
    USE SIGNAL ;
    SHAPE ABUTMENT ;
    PORT
      LAYER M5 ;
      RECT 104.880 2250.024 104.904 2250.216 ;
    END
  END d[447]
  PIN d[448]
    DIRECTION INPUT ;
    USE SIGNAL ;
    SHAPE ABUTMENT ;
    PORT
      LAYER M5 ;
      RECT 105.072 2250.024 105.096 2250.216 ;
    END
  END d[448]
  PIN d[449]
    DIRECTION INPUT ;
    USE SIGNAL ;
    SHAPE ABUTMENT ;
    PORT
      LAYER M5 ;
      RECT 105.264 2250.024 105.288 2250.216 ;
    END
  END d[449]
  PIN d[450]
    DIRECTION INPUT ;
    USE SIGNAL ;
    SHAPE ABUTMENT ;
    PORT
      LAYER M5 ;
      RECT 105.456 2250.024 105.480 2250.216 ;
    END
  END d[450]
  PIN d[451]
    DIRECTION INPUT ;
    USE SIGNAL ;
    SHAPE ABUTMENT ;
    PORT
      LAYER M5 ;
      RECT 105.696 2250.024 105.720 2250.216 ;
    END
  END d[451]
  PIN d[452]
    DIRECTION INPUT ;
    USE SIGNAL ;
    SHAPE ABUTMENT ;
    PORT
      LAYER M5 ;
      RECT 105.888 2250.024 105.912 2250.216 ;
    END
  END d[452]
  PIN d[453]
    DIRECTION INPUT ;
    USE SIGNAL ;
    SHAPE ABUTMENT ;
    PORT
      LAYER M5 ;
      RECT 106.080 2250.024 106.104 2250.216 ;
    END
  END d[453]
  PIN d[454]
    DIRECTION INPUT ;
    USE SIGNAL ;
    SHAPE ABUTMENT ;
    PORT
      LAYER M5 ;
      RECT 106.272 2250.024 106.296 2250.216 ;
    END
  END d[454]
  PIN d[455]
    DIRECTION INPUT ;
    USE SIGNAL ;
    SHAPE ABUTMENT ;
    PORT
      LAYER M5 ;
      RECT 106.512 2250.024 106.536 2250.216 ;
    END
  END d[455]
  PIN d[456]
    DIRECTION INPUT ;
    USE SIGNAL ;
    SHAPE ABUTMENT ;
    PORT
      LAYER M5 ;
      RECT 106.704 2250.024 106.728 2250.216 ;
    END
  END d[456]
  PIN d[457]
    DIRECTION INPUT ;
    USE SIGNAL ;
    SHAPE ABUTMENT ;
    PORT
      LAYER M5 ;
      RECT 106.896 2250.024 106.920 2250.216 ;
    END
  END d[457]
  PIN d[458]
    DIRECTION INPUT ;
    USE SIGNAL ;
    SHAPE ABUTMENT ;
    PORT
      LAYER M5 ;
      RECT 107.088 2250.024 107.112 2250.216 ;
    END
  END d[458]
  PIN d[459]
    DIRECTION INPUT ;
    USE SIGNAL ;
    SHAPE ABUTMENT ;
    PORT
      LAYER M5 ;
      RECT 107.280 2250.024 107.304 2250.216 ;
    END
  END d[459]
  PIN d[460]
    DIRECTION INPUT ;
    USE SIGNAL ;
    SHAPE ABUTMENT ;
    PORT
      LAYER M5 ;
      RECT 107.520 2250.024 107.544 2250.216 ;
    END
  END d[460]
  PIN d[461]
    DIRECTION INPUT ;
    USE SIGNAL ;
    SHAPE ABUTMENT ;
    PORT
      LAYER M5 ;
      RECT 107.712 2250.024 107.736 2250.216 ;
    END
  END d[461]
  PIN d[462]
    DIRECTION INPUT ;
    USE SIGNAL ;
    SHAPE ABUTMENT ;
    PORT
      LAYER M5 ;
      RECT 107.904 2250.024 107.928 2250.216 ;
    END
  END d[462]
  PIN d[463]
    DIRECTION INPUT ;
    USE SIGNAL ;
    SHAPE ABUTMENT ;
    PORT
      LAYER M5 ;
      RECT 108.096 2250.024 108.120 2250.216 ;
    END
  END d[463]
  PIN d[464]
    DIRECTION INPUT ;
    USE SIGNAL ;
    SHAPE ABUTMENT ;
    PORT
      LAYER M5 ;
      RECT 108.288 2250.024 108.312 2250.216 ;
    END
  END d[464]
  PIN d[465]
    DIRECTION INPUT ;
    USE SIGNAL ;
    SHAPE ABUTMENT ;
    PORT
      LAYER M5 ;
      RECT 108.528 2250.024 108.552 2250.216 ;
    END
  END d[465]
  PIN d[466]
    DIRECTION INPUT ;
    USE SIGNAL ;
    SHAPE ABUTMENT ;
    PORT
      LAYER M5 ;
      RECT 108.720 2250.024 108.744 2250.216 ;
    END
  END d[466]
  PIN d[467]
    DIRECTION INPUT ;
    USE SIGNAL ;
    SHAPE ABUTMENT ;
    PORT
      LAYER M5 ;
      RECT 108.912 2250.024 108.936 2250.216 ;
    END
  END d[467]
  PIN d[468]
    DIRECTION INPUT ;
    USE SIGNAL ;
    SHAPE ABUTMENT ;
    PORT
      LAYER M5 ;
      RECT 109.104 2250.024 109.128 2250.216 ;
    END
  END d[468]
  PIN d[469]
    DIRECTION INPUT ;
    USE SIGNAL ;
    SHAPE ABUTMENT ;
    PORT
      LAYER M5 ;
      RECT 109.344 2250.024 109.368 2250.216 ;
    END
  END d[469]
  PIN d[470]
    DIRECTION INPUT ;
    USE SIGNAL ;
    SHAPE ABUTMENT ;
    PORT
      LAYER M5 ;
      RECT 109.536 2250.024 109.560 2250.216 ;
    END
  END d[470]
  PIN d[471]
    DIRECTION INPUT ;
    USE SIGNAL ;
    SHAPE ABUTMENT ;
    PORT
      LAYER M5 ;
      RECT 109.728 2250.024 109.752 2250.216 ;
    END
  END d[471]
  PIN d[472]
    DIRECTION INPUT ;
    USE SIGNAL ;
    SHAPE ABUTMENT ;
    PORT
      LAYER M5 ;
      RECT 109.920 2250.024 109.944 2250.216 ;
    END
  END d[472]
  PIN d[473]
    DIRECTION INPUT ;
    USE SIGNAL ;
    SHAPE ABUTMENT ;
    PORT
      LAYER M5 ;
      RECT 110.112 2250.024 110.136 2250.216 ;
    END
  END d[473]
  PIN d[474]
    DIRECTION INPUT ;
    USE SIGNAL ;
    SHAPE ABUTMENT ;
    PORT
      LAYER M5 ;
      RECT 110.352 2250.024 110.376 2250.216 ;
    END
  END d[474]
  PIN d[475]
    DIRECTION INPUT ;
    USE SIGNAL ;
    SHAPE ABUTMENT ;
    PORT
      LAYER M5 ;
      RECT 110.544 2250.024 110.568 2250.216 ;
    END
  END d[475]
  PIN d[476]
    DIRECTION INPUT ;
    USE SIGNAL ;
    SHAPE ABUTMENT ;
    PORT
      LAYER M5 ;
      RECT 110.736 2250.024 110.760 2250.216 ;
    END
  END d[476]
  PIN d[477]
    DIRECTION INPUT ;
    USE SIGNAL ;
    SHAPE ABUTMENT ;
    PORT
      LAYER M5 ;
      RECT 110.928 2250.024 110.952 2250.216 ;
    END
  END d[477]
  PIN d[478]
    DIRECTION INPUT ;
    USE SIGNAL ;
    SHAPE ABUTMENT ;
    PORT
      LAYER M5 ;
      RECT 111.120 2250.024 111.144 2250.216 ;
    END
  END d[478]
  PIN d[479]
    DIRECTION INPUT ;
    USE SIGNAL ;
    SHAPE ABUTMENT ;
    PORT
      LAYER M5 ;
      RECT 111.360 2250.024 111.384 2250.216 ;
    END
  END d[479]
  PIN d[480]
    DIRECTION INPUT ;
    USE SIGNAL ;
    SHAPE ABUTMENT ;
    PORT
      LAYER M5 ;
      RECT 111.552 2250.024 111.576 2250.216 ;
    END
  END d[480]
  PIN d[481]
    DIRECTION INPUT ;
    USE SIGNAL ;
    SHAPE ABUTMENT ;
    PORT
      LAYER M5 ;
      RECT 111.744 2250.024 111.768 2250.216 ;
    END
  END d[481]
  PIN d[482]
    DIRECTION INPUT ;
    USE SIGNAL ;
    SHAPE ABUTMENT ;
    PORT
      LAYER M5 ;
      RECT 111.936 2250.024 111.960 2250.216 ;
    END
  END d[482]
  PIN d[483]
    DIRECTION INPUT ;
    USE SIGNAL ;
    SHAPE ABUTMENT ;
    PORT
      LAYER M5 ;
      RECT 112.128 2250.024 112.152 2250.216 ;
    END
  END d[483]
  PIN d[484]
    DIRECTION INPUT ;
    USE SIGNAL ;
    SHAPE ABUTMENT ;
    PORT
      LAYER M5 ;
      RECT 112.368 2250.024 112.392 2250.216 ;
    END
  END d[484]
  PIN d[485]
    DIRECTION INPUT ;
    USE SIGNAL ;
    SHAPE ABUTMENT ;
    PORT
      LAYER M5 ;
      RECT 112.560 2250.024 112.584 2250.216 ;
    END
  END d[485]
  PIN d[486]
    DIRECTION INPUT ;
    USE SIGNAL ;
    SHAPE ABUTMENT ;
    PORT
      LAYER M5 ;
      RECT 112.752 2250.024 112.776 2250.216 ;
    END
  END d[486]
  PIN d[487]
    DIRECTION INPUT ;
    USE SIGNAL ;
    SHAPE ABUTMENT ;
    PORT
      LAYER M5 ;
      RECT 112.944 2250.024 112.968 2250.216 ;
    END
  END d[487]
  PIN d[488]
    DIRECTION INPUT ;
    USE SIGNAL ;
    SHAPE ABUTMENT ;
    PORT
      LAYER M5 ;
      RECT 113.184 2250.024 113.208 2250.216 ;
    END
  END d[488]
  PIN d[489]
    DIRECTION INPUT ;
    USE SIGNAL ;
    SHAPE ABUTMENT ;
    PORT
      LAYER M5 ;
      RECT 113.376 2250.024 113.400 2250.216 ;
    END
  END d[489]
  PIN d[490]
    DIRECTION INPUT ;
    USE SIGNAL ;
    SHAPE ABUTMENT ;
    PORT
      LAYER M5 ;
      RECT 113.568 2250.024 113.592 2250.216 ;
    END
  END d[490]
  PIN d[491]
    DIRECTION INPUT ;
    USE SIGNAL ;
    SHAPE ABUTMENT ;
    PORT
      LAYER M5 ;
      RECT 113.760 2250.024 113.784 2250.216 ;
    END
  END d[491]
  PIN d[492]
    DIRECTION INPUT ;
    USE SIGNAL ;
    SHAPE ABUTMENT ;
    PORT
      LAYER M5 ;
      RECT 113.952 2250.024 113.976 2250.216 ;
    END
  END d[492]
  PIN d[493]
    DIRECTION INPUT ;
    USE SIGNAL ;
    SHAPE ABUTMENT ;
    PORT
      LAYER M5 ;
      RECT 114.192 2250.024 114.216 2250.216 ;
    END
  END d[493]
  PIN d[494]
    DIRECTION INPUT ;
    USE SIGNAL ;
    SHAPE ABUTMENT ;
    PORT
      LAYER M5 ;
      RECT 114.384 2250.024 114.408 2250.216 ;
    END
  END d[494]
  PIN d[495]
    DIRECTION INPUT ;
    USE SIGNAL ;
    SHAPE ABUTMENT ;
    PORT
      LAYER M5 ;
      RECT 114.576 2250.024 114.600 2250.216 ;
    END
  END d[495]
  PIN d[496]
    DIRECTION INPUT ;
    USE SIGNAL ;
    SHAPE ABUTMENT ;
    PORT
      LAYER M5 ;
      RECT 114.768 2250.024 114.792 2250.216 ;
    END
  END d[496]
  PIN d[497]
    DIRECTION INPUT ;
    USE SIGNAL ;
    SHAPE ABUTMENT ;
    PORT
      LAYER M5 ;
      RECT 114.960 2250.024 114.984 2250.216 ;
    END
  END d[497]
  PIN d[498]
    DIRECTION INPUT ;
    USE SIGNAL ;
    SHAPE ABUTMENT ;
    PORT
      LAYER M5 ;
      RECT 115.200 2250.024 115.224 2250.216 ;
    END
  END d[498]
  PIN d[499]
    DIRECTION INPUT ;
    USE SIGNAL ;
    SHAPE ABUTMENT ;
    PORT
      LAYER M5 ;
      RECT 115.392 2250.024 115.416 2250.216 ;
    END
  END d[499]
  PIN d[500]
    DIRECTION INPUT ;
    USE SIGNAL ;
    SHAPE ABUTMENT ;
    PORT
      LAYER M5 ;
      RECT 115.584 2250.024 115.608 2250.216 ;
    END
  END d[500]
  PIN d[501]
    DIRECTION INPUT ;
    USE SIGNAL ;
    SHAPE ABUTMENT ;
    PORT
      LAYER M5 ;
      RECT 115.776 2250.024 115.800 2250.216 ;
    END
  END d[501]
  PIN d[502]
    DIRECTION INPUT ;
    USE SIGNAL ;
    SHAPE ABUTMENT ;
    PORT
      LAYER M5 ;
      RECT 116.016 2250.024 116.040 2250.216 ;
    END
  END d[502]
  PIN d[503]
    DIRECTION INPUT ;
    USE SIGNAL ;
    SHAPE ABUTMENT ;
    PORT
      LAYER M5 ;
      RECT 116.208 2250.024 116.232 2250.216 ;
    END
  END d[503]
  PIN d[504]
    DIRECTION INPUT ;
    USE SIGNAL ;
    SHAPE ABUTMENT ;
    PORT
      LAYER M5 ;
      RECT 116.400 2250.024 116.424 2250.216 ;
    END
  END d[504]
  PIN d[505]
    DIRECTION INPUT ;
    USE SIGNAL ;
    SHAPE ABUTMENT ;
    PORT
      LAYER M5 ;
      RECT 116.592 2250.024 116.616 2250.216 ;
    END
  END d[505]
  PIN d[506]
    DIRECTION INPUT ;
    USE SIGNAL ;
    SHAPE ABUTMENT ;
    PORT
      LAYER M5 ;
      RECT 116.784 2250.024 116.808 2250.216 ;
    END
  END d[506]
  PIN d[507]
    DIRECTION INPUT ;
    USE SIGNAL ;
    SHAPE ABUTMENT ;
    PORT
      LAYER M5 ;
      RECT 117.024 2250.024 117.048 2250.216 ;
    END
  END d[507]
  PIN d[508]
    DIRECTION INPUT ;
    USE SIGNAL ;
    SHAPE ABUTMENT ;
    PORT
      LAYER M5 ;
      RECT 117.216 2250.024 117.240 2250.216 ;
    END
  END d[508]
  PIN d[509]
    DIRECTION INPUT ;
    USE SIGNAL ;
    SHAPE ABUTMENT ;
    PORT
      LAYER M5 ;
      RECT 117.408 2250.024 117.432 2250.216 ;
    END
  END d[509]
  PIN d[510]
    DIRECTION INPUT ;
    USE SIGNAL ;
    SHAPE ABUTMENT ;
    PORT
      LAYER M5 ;
      RECT 117.600 2250.024 117.624 2250.216 ;
    END
  END d[510]
  PIN d[511]
    DIRECTION INPUT ;
    USE SIGNAL ;
    SHAPE ABUTMENT ;
    PORT
      LAYER M5 ;
      RECT 117.792 2250.024 117.816 2250.216 ;
    END
  END d[511]
  PIN d[512]
    DIRECTION INPUT ;
    USE SIGNAL ;
    SHAPE ABUTMENT ;
    PORT
      LAYER M5 ;
      RECT 118.032 2250.024 118.056 2250.216 ;
    END
  END d[512]
  PIN d[513]
    DIRECTION INPUT ;
    USE SIGNAL ;
    SHAPE ABUTMENT ;
    PORT
      LAYER M5 ;
      RECT 118.224 2250.024 118.248 2250.216 ;
    END
  END d[513]
  PIN d[514]
    DIRECTION INPUT ;
    USE SIGNAL ;
    SHAPE ABUTMENT ;
    PORT
      LAYER M5 ;
      RECT 118.416 2250.024 118.440 2250.216 ;
    END
  END d[514]
  PIN d[515]
    DIRECTION INPUT ;
    USE SIGNAL ;
    SHAPE ABUTMENT ;
    PORT
      LAYER M5 ;
      RECT 118.608 2250.024 118.632 2250.216 ;
    END
  END d[515]
  PIN d[516]
    DIRECTION INPUT ;
    USE SIGNAL ;
    SHAPE ABUTMENT ;
    PORT
      LAYER M5 ;
      RECT 118.848 2250.024 118.872 2250.216 ;
    END
  END d[516]
  PIN d[517]
    DIRECTION INPUT ;
    USE SIGNAL ;
    SHAPE ABUTMENT ;
    PORT
      LAYER M5 ;
      RECT 119.040 2250.024 119.064 2250.216 ;
    END
  END d[517]
  PIN d[518]
    DIRECTION INPUT ;
    USE SIGNAL ;
    SHAPE ABUTMENT ;
    PORT
      LAYER M5 ;
      RECT 119.232 2250.024 119.256 2250.216 ;
    END
  END d[518]
  PIN d[519]
    DIRECTION INPUT ;
    USE SIGNAL ;
    SHAPE ABUTMENT ;
    PORT
      LAYER M5 ;
      RECT 119.424 2250.024 119.448 2250.216 ;
    END
  END d[519]
  PIN d[520]
    DIRECTION INPUT ;
    USE SIGNAL ;
    SHAPE ABUTMENT ;
    PORT
      LAYER M5 ;
      RECT 119.616 2250.024 119.640 2250.216 ;
    END
  END d[520]
  PIN d[521]
    DIRECTION INPUT ;
    USE SIGNAL ;
    SHAPE ABUTMENT ;
    PORT
      LAYER M5 ;
      RECT 119.856 2250.024 119.880 2250.216 ;
    END
  END d[521]
  PIN d[522]
    DIRECTION INPUT ;
    USE SIGNAL ;
    SHAPE ABUTMENT ;
    PORT
      LAYER M5 ;
      RECT 120.048 2250.024 120.072 2250.216 ;
    END
  END d[522]
  PIN d[523]
    DIRECTION INPUT ;
    USE SIGNAL ;
    SHAPE ABUTMENT ;
    PORT
      LAYER M5 ;
      RECT 120.240 2250.024 120.264 2250.216 ;
    END
  END d[523]
  PIN d[524]
    DIRECTION INPUT ;
    USE SIGNAL ;
    SHAPE ABUTMENT ;
    PORT
      LAYER M5 ;
      RECT 120.432 2250.024 120.456 2250.216 ;
    END
  END d[524]
  PIN d[525]
    DIRECTION INPUT ;
    USE SIGNAL ;
    SHAPE ABUTMENT ;
    PORT
      LAYER M5 ;
      RECT 120.624 2250.024 120.648 2250.216 ;
    END
  END d[525]
  PIN d[526]
    DIRECTION INPUT ;
    USE SIGNAL ;
    SHAPE ABUTMENT ;
    PORT
      LAYER M5 ;
      RECT 120.864 2250.024 120.888 2250.216 ;
    END
  END d[526]
  PIN d[527]
    DIRECTION INPUT ;
    USE SIGNAL ;
    SHAPE ABUTMENT ;
    PORT
      LAYER M5 ;
      RECT 121.056 2250.024 121.080 2250.216 ;
    END
  END d[527]
  PIN d[528]
    DIRECTION INPUT ;
    USE SIGNAL ;
    SHAPE ABUTMENT ;
    PORT
      LAYER M5 ;
      RECT 121.248 2250.024 121.272 2250.216 ;
    END
  END d[528]
  PIN d[529]
    DIRECTION INPUT ;
    USE SIGNAL ;
    SHAPE ABUTMENT ;
    PORT
      LAYER M5 ;
      RECT 121.440 2250.024 121.464 2250.216 ;
    END
  END d[529]
  PIN d[530]
    DIRECTION INPUT ;
    USE SIGNAL ;
    SHAPE ABUTMENT ;
    PORT
      LAYER M5 ;
      RECT 121.680 2250.024 121.704 2250.216 ;
    END
  END d[530]
  PIN d[531]
    DIRECTION INPUT ;
    USE SIGNAL ;
    SHAPE ABUTMENT ;
    PORT
      LAYER M5 ;
      RECT 121.872 2250.024 121.896 2250.216 ;
    END
  END d[531]
  PIN d[532]
    DIRECTION INPUT ;
    USE SIGNAL ;
    SHAPE ABUTMENT ;
    PORT
      LAYER M5 ;
      RECT 122.064 2250.024 122.088 2250.216 ;
    END
  END d[532]
  PIN d[533]
    DIRECTION INPUT ;
    USE SIGNAL ;
    SHAPE ABUTMENT ;
    PORT
      LAYER M5 ;
      RECT 122.256 2250.024 122.280 2250.216 ;
    END
  END d[533]
  PIN d[534]
    DIRECTION INPUT ;
    USE SIGNAL ;
    SHAPE ABUTMENT ;
    PORT
      LAYER M5 ;
      RECT 122.448 2250.024 122.472 2250.216 ;
    END
  END d[534]
  PIN d[535]
    DIRECTION INPUT ;
    USE SIGNAL ;
    SHAPE ABUTMENT ;
    PORT
      LAYER M5 ;
      RECT 122.688 2250.024 122.712 2250.216 ;
    END
  END d[535]
  PIN d[536]
    DIRECTION INPUT ;
    USE SIGNAL ;
    SHAPE ABUTMENT ;
    PORT
      LAYER M5 ;
      RECT 122.880 2250.024 122.904 2250.216 ;
    END
  END d[536]
  PIN d[537]
    DIRECTION INPUT ;
    USE SIGNAL ;
    SHAPE ABUTMENT ;
    PORT
      LAYER M5 ;
      RECT 123.072 2250.024 123.096 2250.216 ;
    END
  END d[537]
  PIN d[538]
    DIRECTION INPUT ;
    USE SIGNAL ;
    SHAPE ABUTMENT ;
    PORT
      LAYER M5 ;
      RECT 123.264 2250.024 123.288 2250.216 ;
    END
  END d[538]
  PIN d[539]
    DIRECTION INPUT ;
    USE SIGNAL ;
    SHAPE ABUTMENT ;
    PORT
      LAYER M5 ;
      RECT 123.456 2250.024 123.480 2250.216 ;
    END
  END d[539]
  PIN d[540]
    DIRECTION INPUT ;
    USE SIGNAL ;
    SHAPE ABUTMENT ;
    PORT
      LAYER M5 ;
      RECT 123.696 2250.024 123.720 2250.216 ;
    END
  END d[540]
  PIN d[541]
    DIRECTION INPUT ;
    USE SIGNAL ;
    SHAPE ABUTMENT ;
    PORT
      LAYER M5 ;
      RECT 123.888 2250.024 123.912 2250.216 ;
    END
  END d[541]
  PIN d[542]
    DIRECTION INPUT ;
    USE SIGNAL ;
    SHAPE ABUTMENT ;
    PORT
      LAYER M5 ;
      RECT 124.080 2250.024 124.104 2250.216 ;
    END
  END d[542]
  PIN d[543]
    DIRECTION INPUT ;
    USE SIGNAL ;
    SHAPE ABUTMENT ;
    PORT
      LAYER M5 ;
      RECT 124.272 2250.024 124.296 2250.216 ;
    END
  END d[543]
  PIN pma_tx[0]
    DIRECTION OUTPUT ;
    USE SIGNAL ;
    SHAPE ABUTMENT ;
    PORT
      LAYER M5 ;
      RECT 4.512 0.000 4.536 0.192 ;
    END
  END pma_tx[0]
  PIN pma_tx[1]
    DIRECTION OUTPUT ;
    USE SIGNAL ;
    SHAPE ABUTMENT ;
    PORT
      LAYER M5 ;
      RECT 4.704 0.000 4.728 0.192 ;
    END
  END pma_tx[1]
  PIN pma_tx[2]
    DIRECTION OUTPUT ;
    USE SIGNAL ;
    SHAPE ABUTMENT ;
    PORT
      LAYER M5 ;
      RECT 4.896 0.000 4.920 0.192 ;
    END
  END pma_tx[2]
  PIN pma_tx[3]
    DIRECTION OUTPUT ;
    USE SIGNAL ;
    SHAPE ABUTMENT ;
    PORT
      LAYER M5 ;
      RECT 5.088 0.000 5.112 0.192 ;
    END
  END pma_tx[3]
  PIN pma_tx[4]
    DIRECTION OUTPUT ;
    USE SIGNAL ;
    SHAPE ABUTMENT ;
    PORT
      LAYER M5 ;
      RECT 5.328 0.000 5.352 0.192 ;
    END
  END pma_tx[4]
  PIN pma_tx[5]
    DIRECTION OUTPUT ;
    USE SIGNAL ;
    SHAPE ABUTMENT ;
    PORT
      LAYER M5 ;
      RECT 5.520 0.000 5.544 0.192 ;
    END
  END pma_tx[5]
  PIN pma_tx[6]
    DIRECTION OUTPUT ;
    USE SIGNAL ;
    SHAPE ABUTMENT ;
    PORT
      LAYER M5 ;
      RECT 5.712 0.000 5.736 0.192 ;
    END
  END pma_tx[6]
  PIN pma_tx[7]
    DIRECTION OUTPUT ;
    USE SIGNAL ;
    SHAPE ABUTMENT ;
    PORT
      LAYER M5 ;
      RECT 5.952 0.000 5.976 0.192 ;
    END
  END pma_tx[7]
  PIN pma_tx[8]
    DIRECTION OUTPUT ;
    USE SIGNAL ;
    SHAPE ABUTMENT ;
    PORT
      LAYER M5 ;
      RECT 6.144 0.000 6.168 0.192 ;
    END
  END pma_tx[8]
  PIN pma_tx[9]
    DIRECTION OUTPUT ;
    USE SIGNAL ;
    SHAPE ABUTMENT ;
    PORT
      LAYER M5 ;
      RECT 6.336 0.000 6.360 0.192 ;
    END
  END pma_tx[9]
  PIN pma_tx[10]
    DIRECTION OUTPUT ;
    USE SIGNAL ;
    SHAPE ABUTMENT ;
    PORT
      LAYER M5 ;
      RECT 6.528 0.000 6.552 0.192 ;
    END
  END pma_tx[10]
  PIN pma_tx[11]
    DIRECTION OUTPUT ;
    USE SIGNAL ;
    SHAPE ABUTMENT ;
    PORT
      LAYER M5 ;
      RECT 6.768 0.000 6.792 0.192 ;
    END
  END pma_tx[11]
  PIN pma_tx[12]
    DIRECTION OUTPUT ;
    USE SIGNAL ;
    SHAPE ABUTMENT ;
    PORT
      LAYER M5 ;
      RECT 6.960 0.000 6.984 0.192 ;
    END
  END pma_tx[12]
  PIN pma_tx[13]
    DIRECTION OUTPUT ;
    USE SIGNAL ;
    SHAPE ABUTMENT ;
    PORT
      LAYER M5 ;
      RECT 7.152 0.000 7.176 0.192 ;
    END
  END pma_tx[13]
  PIN pma_tx[14]
    DIRECTION OUTPUT ;
    USE SIGNAL ;
    SHAPE ABUTMENT ;
    PORT
      LAYER M5 ;
      RECT 7.392 0.000 7.416 0.192 ;
    END
  END pma_tx[14]
  PIN pma_tx[15]
    DIRECTION OUTPUT ;
    USE SIGNAL ;
    SHAPE ABUTMENT ;
    PORT
      LAYER M5 ;
      RECT 7.584 0.000 7.608 0.192 ;
    END
  END pma_tx[15]
  PIN pma_tx[16]
    DIRECTION OUTPUT ;
    USE SIGNAL ;
    SHAPE ABUTMENT ;
    PORT
      LAYER M5 ;
      RECT 7.776 0.000 7.800 0.192 ;
    END
  END pma_tx[16]
  PIN pma_tx[17]
    DIRECTION OUTPUT ;
    USE SIGNAL ;
    SHAPE ABUTMENT ;
    PORT
      LAYER M5 ;
      RECT 7.968 0.000 7.992 0.192 ;
    END
  END pma_tx[17]
  PIN pma_tx[18]
    DIRECTION OUTPUT ;
    USE SIGNAL ;
    SHAPE ABUTMENT ;
    PORT
      LAYER M5 ;
      RECT 8.208 0.000 8.232 0.192 ;
    END
  END pma_tx[18]
  PIN pma_tx[19]
    DIRECTION OUTPUT ;
    USE SIGNAL ;
    SHAPE ABUTMENT ;
    PORT
      LAYER M5 ;
      RECT 8.400 0.000 8.424 0.192 ;
    END
  END pma_tx[19]
  PIN pma_tx[20]
    DIRECTION OUTPUT ;
    USE SIGNAL ;
    SHAPE ABUTMENT ;
    PORT
      LAYER M5 ;
      RECT 8.592 0.000 8.616 0.192 ;
    END
  END pma_tx[20]
  PIN pma_tx[21]
    DIRECTION OUTPUT ;
    USE SIGNAL ;
    SHAPE ABUTMENT ;
    PORT
      LAYER M5 ;
      RECT 8.832 0.000 8.856 0.192 ;
    END
  END pma_tx[21]
  PIN pma_tx[22]
    DIRECTION OUTPUT ;
    USE SIGNAL ;
    SHAPE ABUTMENT ;
    PORT
      LAYER M5 ;
      RECT 9.024 0.000 9.048 0.192 ;
    END
  END pma_tx[22]
  PIN pma_tx[23]
    DIRECTION OUTPUT ;
    USE SIGNAL ;
    SHAPE ABUTMENT ;
    PORT
      LAYER M5 ;
      RECT 9.216 0.000 9.240 0.192 ;
    END
  END pma_tx[23]
  PIN pma_tx[24]
    DIRECTION OUTPUT ;
    USE SIGNAL ;
    SHAPE ABUTMENT ;
    PORT
      LAYER M5 ;
      RECT 9.408 0.000 9.432 0.192 ;
    END
  END pma_tx[24]
  PIN pma_tx[25]
    DIRECTION OUTPUT ;
    USE SIGNAL ;
    SHAPE ABUTMENT ;
    PORT
      LAYER M5 ;
      RECT 9.648 0.000 9.672 0.192 ;
    END
  END pma_tx[25]
  PIN pma_tx[26]
    DIRECTION OUTPUT ;
    USE SIGNAL ;
    SHAPE ABUTMENT ;
    PORT
      LAYER M5 ;
      RECT 9.840 0.000 9.864 0.192 ;
    END
  END pma_tx[26]
  PIN pma_tx[27]
    DIRECTION OUTPUT ;
    USE SIGNAL ;
    SHAPE ABUTMENT ;
    PORT
      LAYER M5 ;
      RECT 10.032 0.000 10.056 0.192 ;
    END
  END pma_tx[27]
  PIN pma_tx[28]
    DIRECTION OUTPUT ;
    USE SIGNAL ;
    SHAPE ABUTMENT ;
    PORT
      LAYER M5 ;
      RECT 10.272 0.000 10.296 0.192 ;
    END
  END pma_tx[28]
  PIN pma_tx[29]
    DIRECTION OUTPUT ;
    USE SIGNAL ;
    SHAPE ABUTMENT ;
    PORT
      LAYER M5 ;
      RECT 10.464 0.000 10.488 0.192 ;
    END
  END pma_tx[29]
  PIN pma_tx[30]
    DIRECTION OUTPUT ;
    USE SIGNAL ;
    SHAPE ABUTMENT ;
    PORT
      LAYER M5 ;
      RECT 10.656 0.000 10.680 0.192 ;
    END
  END pma_tx[30]
  PIN pma_tx[31]
    DIRECTION OUTPUT ;
    USE SIGNAL ;
    SHAPE ABUTMENT ;
    PORT
      LAYER M5 ;
      RECT 10.848 0.000 10.872 0.192 ;
    END
  END pma_tx[31]
  PIN pma_tx[32]
    DIRECTION OUTPUT ;
    USE SIGNAL ;
    SHAPE ABUTMENT ;
    PORT
      LAYER M5 ;
      RECT 11.088 0.000 11.112 0.192 ;
    END
  END pma_tx[32]
  PIN pma_tx[33]
    DIRECTION OUTPUT ;
    USE SIGNAL ;
    SHAPE ABUTMENT ;
    PORT
      LAYER M5 ;
      RECT 11.280 0.000 11.304 0.192 ;
    END
  END pma_tx[33]
  PIN pma_tx[34]
    DIRECTION OUTPUT ;
    USE SIGNAL ;
    SHAPE ABUTMENT ;
    PORT
      LAYER M5 ;
      RECT 11.472 0.000 11.496 0.192 ;
    END
  END pma_tx[34]
  PIN pma_tx[35]
    DIRECTION OUTPUT ;
    USE SIGNAL ;
    SHAPE ABUTMENT ;
    PORT
      LAYER M5 ;
      RECT 11.712 0.000 11.736 0.192 ;
    END
  END pma_tx[35]
  PIN pma_tx[36]
    DIRECTION OUTPUT ;
    USE SIGNAL ;
    SHAPE ABUTMENT ;
    PORT
      LAYER M5 ;
      RECT 11.904 0.000 11.928 0.192 ;
    END
  END pma_tx[36]
  PIN pma_tx[37]
    DIRECTION OUTPUT ;
    USE SIGNAL ;
    SHAPE ABUTMENT ;
    PORT
      LAYER M5 ;
      RECT 12.096 0.000 12.120 0.192 ;
    END
  END pma_tx[37]
  PIN pma_tx[38]
    DIRECTION OUTPUT ;
    USE SIGNAL ;
    SHAPE ABUTMENT ;
    PORT
      LAYER M5 ;
      RECT 12.288 0.000 12.312 0.192 ;
    END
  END pma_tx[38]
  PIN pma_tx[39]
    DIRECTION OUTPUT ;
    USE SIGNAL ;
    SHAPE ABUTMENT ;
    PORT
      LAYER M5 ;
      RECT 12.528 0.000 12.552 0.192 ;
    END
  END pma_tx[39]
  PIN pma_tx[40]
    DIRECTION OUTPUT ;
    USE SIGNAL ;
    SHAPE ABUTMENT ;
    PORT
      LAYER M5 ;
      RECT 12.720 0.000 12.744 0.192 ;
    END
  END pma_tx[40]
  PIN pma_tx[41]
    DIRECTION OUTPUT ;
    USE SIGNAL ;
    SHAPE ABUTMENT ;
    PORT
      LAYER M5 ;
      RECT 12.912 0.000 12.936 0.192 ;
    END
  END pma_tx[41]
  PIN pma_tx[42]
    DIRECTION OUTPUT ;
    USE SIGNAL ;
    SHAPE ABUTMENT ;
    PORT
      LAYER M5 ;
      RECT 13.152 0.000 13.176 0.192 ;
    END
  END pma_tx[42]
  PIN pma_tx[43]
    DIRECTION OUTPUT ;
    USE SIGNAL ;
    SHAPE ABUTMENT ;
    PORT
      LAYER M5 ;
      RECT 13.344 0.000 13.368 0.192 ;
    END
  END pma_tx[43]
  PIN pma_tx[44]
    DIRECTION OUTPUT ;
    USE SIGNAL ;
    SHAPE ABUTMENT ;
    PORT
      LAYER M5 ;
      RECT 13.536 0.000 13.560 0.192 ;
    END
  END pma_tx[44]
  PIN pma_tx[45]
    DIRECTION OUTPUT ;
    USE SIGNAL ;
    SHAPE ABUTMENT ;
    PORT
      LAYER M5 ;
      RECT 13.728 0.000 13.752 0.192 ;
    END
  END pma_tx[45]
  PIN pma_tx[46]
    DIRECTION OUTPUT ;
    USE SIGNAL ;
    SHAPE ABUTMENT ;
    PORT
      LAYER M5 ;
      RECT 13.968 0.000 13.992 0.192 ;
    END
  END pma_tx[46]
  PIN pma_tx[47]
    DIRECTION OUTPUT ;
    USE SIGNAL ;
    SHAPE ABUTMENT ;
    PORT
      LAYER M5 ;
      RECT 14.160 0.000 14.184 0.192 ;
    END
  END pma_tx[47]
  PIN pma_tx[48]
    DIRECTION OUTPUT ;
    USE SIGNAL ;
    SHAPE ABUTMENT ;
    PORT
      LAYER M5 ;
      RECT 14.352 0.000 14.376 0.192 ;
    END
  END pma_tx[48]
  PIN pma_tx[49]
    DIRECTION OUTPUT ;
    USE SIGNAL ;
    SHAPE ABUTMENT ;
    PORT
      LAYER M5 ;
      RECT 14.592 0.000 14.616 0.192 ;
    END
  END pma_tx[49]
  PIN pma_tx[50]
    DIRECTION OUTPUT ;
    USE SIGNAL ;
    SHAPE ABUTMENT ;
    PORT
      LAYER M5 ;
      RECT 14.784 0.000 14.808 0.192 ;
    END
  END pma_tx[50]
  PIN pma_tx[51]
    DIRECTION OUTPUT ;
    USE SIGNAL ;
    SHAPE ABUTMENT ;
    PORT
      LAYER M5 ;
      RECT 14.976 0.000 15.000 0.192 ;
    END
  END pma_tx[51]
  PIN pma_tx[52]
    DIRECTION OUTPUT ;
    USE SIGNAL ;
    SHAPE ABUTMENT ;
    PORT
      LAYER M5 ;
      RECT 15.216 0.000 15.240 0.192 ;
    END
  END pma_tx[52]
  PIN pma_tx[53]
    DIRECTION OUTPUT ;
    USE SIGNAL ;
    SHAPE ABUTMENT ;
    PORT
      LAYER M5 ;
      RECT 15.408 0.000 15.432 0.192 ;
    END
  END pma_tx[53]
  PIN pma_tx[54]
    DIRECTION OUTPUT ;
    USE SIGNAL ;
    SHAPE ABUTMENT ;
    PORT
      LAYER M5 ;
      RECT 15.600 0.000 15.624 0.192 ;
    END
  END pma_tx[54]
  PIN pma_tx[55]
    DIRECTION OUTPUT ;
    USE SIGNAL ;
    SHAPE ABUTMENT ;
    PORT
      LAYER M5 ;
      RECT 15.792 0.000 15.816 0.192 ;
    END
  END pma_tx[55]
  PIN pma_tx[56]
    DIRECTION OUTPUT ;
    USE SIGNAL ;
    SHAPE ABUTMENT ;
    PORT
      LAYER M5 ;
      RECT 16.032 0.000 16.056 0.192 ;
    END
  END pma_tx[56]
  PIN pma_tx[57]
    DIRECTION OUTPUT ;
    USE SIGNAL ;
    SHAPE ABUTMENT ;
    PORT
      LAYER M5 ;
      RECT 16.224 0.000 16.248 0.192 ;
    END
  END pma_tx[57]
  PIN pma_tx[58]
    DIRECTION OUTPUT ;
    USE SIGNAL ;
    SHAPE ABUTMENT ;
    PORT
      LAYER M5 ;
      RECT 16.416 0.000 16.440 0.192 ;
    END
  END pma_tx[58]
  PIN pma_tx[59]
    DIRECTION OUTPUT ;
    USE SIGNAL ;
    SHAPE ABUTMENT ;
    PORT
      LAYER M5 ;
      RECT 16.656 0.000 16.680 0.192 ;
    END
  END pma_tx[59]
  PIN pma_tx[60]
    DIRECTION OUTPUT ;
    USE SIGNAL ;
    SHAPE ABUTMENT ;
    PORT
      LAYER M5 ;
      RECT 16.848 0.000 16.872 0.192 ;
    END
  END pma_tx[60]
  PIN pma_tx[61]
    DIRECTION OUTPUT ;
    USE SIGNAL ;
    SHAPE ABUTMENT ;
    PORT
      LAYER M5 ;
      RECT 17.040 0.000 17.064 0.192 ;
    END
  END pma_tx[61]
  PIN pma_tx[62]
    DIRECTION OUTPUT ;
    USE SIGNAL ;
    SHAPE ABUTMENT ;
    PORT
      LAYER M5 ;
      RECT 17.232 0.000 17.256 0.192 ;
    END
  END pma_tx[62]
  PIN pma_tx[63]
    DIRECTION OUTPUT ;
    USE SIGNAL ;
    SHAPE ABUTMENT ;
    PORT
      LAYER M5 ;
      RECT 17.472 0.000 17.496 0.192 ;
    END
  END pma_tx[63]
  PIN pma_tx[64]
    DIRECTION OUTPUT ;
    USE SIGNAL ;
    SHAPE ABUTMENT ;
    PORT
      LAYER M5 ;
      RECT 17.664 0.000 17.688 0.192 ;
    END
  END pma_tx[64]
  PIN pma_tx[65]
    DIRECTION OUTPUT ;
    USE SIGNAL ;
    SHAPE ABUTMENT ;
    PORT
      LAYER M5 ;
      RECT 17.856 0.000 17.880 0.192 ;
    END
  END pma_tx[65]
  PIN pma_tx[66]
    DIRECTION OUTPUT ;
    USE SIGNAL ;
    SHAPE ABUTMENT ;
    PORT
      LAYER M5 ;
      RECT 18.096 0.000 18.120 0.192 ;
    END
  END pma_tx[66]
  PIN pma_tx[67]
    DIRECTION OUTPUT ;
    USE SIGNAL ;
    SHAPE ABUTMENT ;
    PORT
      LAYER M5 ;
      RECT 18.288 0.000 18.312 0.192 ;
    END
  END pma_tx[67]
  PIN pma_tx[68]
    DIRECTION OUTPUT ;
    USE SIGNAL ;
    SHAPE ABUTMENT ;
    PORT
      LAYER M5 ;
      RECT 18.480 0.000 18.504 0.192 ;
    END
  END pma_tx[68]
  PIN pma_tx[69]
    DIRECTION OUTPUT ;
    USE SIGNAL ;
    SHAPE ABUTMENT ;
    PORT
      LAYER M5 ;
      RECT 18.672 0.000 18.696 0.192 ;
    END
  END pma_tx[69]
  PIN pma_tx[70]
    DIRECTION OUTPUT ;
    USE SIGNAL ;
    SHAPE ABUTMENT ;
    PORT
      LAYER M5 ;
      RECT 18.912 0.000 18.936 0.192 ;
    END
  END pma_tx[70]
  PIN pma_tx[71]
    DIRECTION OUTPUT ;
    USE SIGNAL ;
    SHAPE ABUTMENT ;
    PORT
      LAYER M5 ;
      RECT 19.104 0.000 19.128 0.192 ;
    END
  END pma_tx[71]
  PIN pma_tx[72]
    DIRECTION OUTPUT ;
    USE SIGNAL ;
    SHAPE ABUTMENT ;
    PORT
      LAYER M5 ;
      RECT 19.296 0.000 19.320 0.192 ;
    END
  END pma_tx[72]
  PIN pma_tx[73]
    DIRECTION OUTPUT ;
    USE SIGNAL ;
    SHAPE ABUTMENT ;
    PORT
      LAYER M5 ;
      RECT 19.536 0.000 19.560 0.192 ;
    END
  END pma_tx[73]
  PIN pma_tx[74]
    DIRECTION OUTPUT ;
    USE SIGNAL ;
    SHAPE ABUTMENT ;
    PORT
      LAYER M5 ;
      RECT 19.728 0.000 19.752 0.192 ;
    END
  END pma_tx[74]
  PIN pma_tx[75]
    DIRECTION OUTPUT ;
    USE SIGNAL ;
    SHAPE ABUTMENT ;
    PORT
      LAYER M5 ;
      RECT 19.920 0.000 19.944 0.192 ;
    END
  END pma_tx[75]
  PIN pma_tx[76]
    DIRECTION OUTPUT ;
    USE SIGNAL ;
    SHAPE ABUTMENT ;
    PORT
      LAYER M5 ;
      RECT 20.112 0.000 20.136 0.192 ;
    END
  END pma_tx[76]
  PIN pma_tx[77]
    DIRECTION OUTPUT ;
    USE SIGNAL ;
    SHAPE ABUTMENT ;
    PORT
      LAYER M5 ;
      RECT 20.352 0.000 20.376 0.192 ;
    END
  END pma_tx[77]
  PIN pma_tx[78]
    DIRECTION OUTPUT ;
    USE SIGNAL ;
    SHAPE ABUTMENT ;
    PORT
      LAYER M5 ;
      RECT 20.544 0.000 20.568 0.192 ;
    END
  END pma_tx[78]
  PIN pma_tx[79]
    DIRECTION OUTPUT ;
    USE SIGNAL ;
    SHAPE ABUTMENT ;
    PORT
      LAYER M5 ;
      RECT 20.736 0.000 20.760 0.192 ;
    END
  END pma_tx[79]
  PIN pma_tx[80]
    DIRECTION OUTPUT ;
    USE SIGNAL ;
    SHAPE ABUTMENT ;
    PORT
      LAYER M5 ;
      RECT 20.976 0.000 21.000 0.192 ;
    END
  END pma_tx[80]
  PIN pma_tx[81]
    DIRECTION OUTPUT ;
    USE SIGNAL ;
    SHAPE ABUTMENT ;
    PORT
      LAYER M5 ;
      RECT 21.168 0.000 21.192 0.192 ;
    END
  END pma_tx[81]
  PIN pma_tx[82]
    DIRECTION OUTPUT ;
    USE SIGNAL ;
    SHAPE ABUTMENT ;
    PORT
      LAYER M5 ;
      RECT 21.360 0.000 21.384 0.192 ;
    END
  END pma_tx[82]
  PIN pma_tx[83]
    DIRECTION OUTPUT ;
    USE SIGNAL ;
    SHAPE ABUTMENT ;
    PORT
      LAYER M5 ;
      RECT 21.552 0.000 21.576 0.192 ;
    END
  END pma_tx[83]
  PIN pma_tx[84]
    DIRECTION OUTPUT ;
    USE SIGNAL ;
    SHAPE ABUTMENT ;
    PORT
      LAYER M5 ;
      RECT 21.792 0.000 21.816 0.192 ;
    END
  END pma_tx[84]
  PIN pma_tx[85]
    DIRECTION OUTPUT ;
    USE SIGNAL ;
    SHAPE ABUTMENT ;
    PORT
      LAYER M5 ;
      RECT 21.984 0.000 22.008 0.192 ;
    END
  END pma_tx[85]
  PIN pma_tx[86]
    DIRECTION OUTPUT ;
    USE SIGNAL ;
    SHAPE ABUTMENT ;
    PORT
      LAYER M5 ;
      RECT 22.176 0.000 22.200 0.192 ;
    END
  END pma_tx[86]
  PIN pma_tx[87]
    DIRECTION OUTPUT ;
    USE SIGNAL ;
    SHAPE ABUTMENT ;
    PORT
      LAYER M5 ;
      RECT 22.416 0.000 22.440 0.192 ;
    END
  END pma_tx[87]
  PIN pma_tx[88]
    DIRECTION OUTPUT ;
    USE SIGNAL ;
    SHAPE ABUTMENT ;
    PORT
      LAYER M5 ;
      RECT 22.608 0.000 22.632 0.192 ;
    END
  END pma_tx[88]
  PIN pma_tx[89]
    DIRECTION OUTPUT ;
    USE SIGNAL ;
    SHAPE ABUTMENT ;
    PORT
      LAYER M5 ;
      RECT 22.800 0.000 22.824 0.192 ;
    END
  END pma_tx[89]
  PIN pma_tx[90]
    DIRECTION OUTPUT ;
    USE SIGNAL ;
    SHAPE ABUTMENT ;
    PORT
      LAYER M5 ;
      RECT 22.992 0.000 23.016 0.192 ;
    END
  END pma_tx[90]
  PIN pma_tx[91]
    DIRECTION OUTPUT ;
    USE SIGNAL ;
    SHAPE ABUTMENT ;
    PORT
      LAYER M5 ;
      RECT 23.232 0.000 23.256 0.192 ;
    END
  END pma_tx[91]
  PIN pma_tx[92]
    DIRECTION OUTPUT ;
    USE SIGNAL ;
    SHAPE ABUTMENT ;
    PORT
      LAYER M5 ;
      RECT 23.424 0.000 23.448 0.192 ;
    END
  END pma_tx[92]
  PIN pma_tx[93]
    DIRECTION OUTPUT ;
    USE SIGNAL ;
    SHAPE ABUTMENT ;
    PORT
      LAYER M5 ;
      RECT 23.616 0.000 23.640 0.192 ;
    END
  END pma_tx[93]
  PIN pma_tx[94]
    DIRECTION OUTPUT ;
    USE SIGNAL ;
    SHAPE ABUTMENT ;
    PORT
      LAYER M5 ;
      RECT 23.856 0.000 23.880 0.192 ;
    END
  END pma_tx[94]
  PIN pma_tx[95]
    DIRECTION OUTPUT ;
    USE SIGNAL ;
    SHAPE ABUTMENT ;
    PORT
      LAYER M5 ;
      RECT 24.048 0.000 24.072 0.192 ;
    END
  END pma_tx[95]
  PIN pma_tx[96]
    DIRECTION OUTPUT ;
    USE SIGNAL ;
    SHAPE ABUTMENT ;
    PORT
      LAYER M5 ;
      RECT 24.240 0.000 24.264 0.192 ;
    END
  END pma_tx[96]
  PIN pma_tx[97]
    DIRECTION OUTPUT ;
    USE SIGNAL ;
    SHAPE ABUTMENT ;
    PORT
      LAYER M5 ;
      RECT 24.432 0.000 24.456 0.192 ;
    END
  END pma_tx[97]
  PIN pma_tx[98]
    DIRECTION OUTPUT ;
    USE SIGNAL ;
    SHAPE ABUTMENT ;
    PORT
      LAYER M5 ;
      RECT 24.672 0.000 24.696 0.192 ;
    END
  END pma_tx[98]
  PIN pma_tx[99]
    DIRECTION OUTPUT ;
    USE SIGNAL ;
    SHAPE ABUTMENT ;
    PORT
      LAYER M5 ;
      RECT 24.864 0.000 24.888 0.192 ;
    END
  END pma_tx[99]
  PIN pma_tx[100]
    DIRECTION OUTPUT ;
    USE SIGNAL ;
    SHAPE ABUTMENT ;
    PORT
      LAYER M5 ;
      RECT 25.056 0.000 25.080 0.192 ;
    END
  END pma_tx[100]
  PIN pma_tx[101]
    DIRECTION OUTPUT ;
    USE SIGNAL ;
    SHAPE ABUTMENT ;
    PORT
      LAYER M5 ;
      RECT 25.296 0.000 25.320 0.192 ;
    END
  END pma_tx[101]
  PIN pma_tx[102]
    DIRECTION OUTPUT ;
    USE SIGNAL ;
    SHAPE ABUTMENT ;
    PORT
      LAYER M5 ;
      RECT 25.488 0.000 25.512 0.192 ;
    END
  END pma_tx[102]
  PIN pma_tx[103]
    DIRECTION OUTPUT ;
    USE SIGNAL ;
    SHAPE ABUTMENT ;
    PORT
      LAYER M5 ;
      RECT 25.680 0.000 25.704 0.192 ;
    END
  END pma_tx[103]
  PIN pma_tx[104]
    DIRECTION OUTPUT ;
    USE SIGNAL ;
    SHAPE ABUTMENT ;
    PORT
      LAYER M5 ;
      RECT 25.920 0.000 25.944 0.192 ;
    END
  END pma_tx[104]
  PIN pma_tx[105]
    DIRECTION OUTPUT ;
    USE SIGNAL ;
    SHAPE ABUTMENT ;
    PORT
      LAYER M5 ;
      RECT 26.112 0.000 26.136 0.192 ;
    END
  END pma_tx[105]
  PIN pma_tx[106]
    DIRECTION OUTPUT ;
    USE SIGNAL ;
    SHAPE ABUTMENT ;
    PORT
      LAYER M5 ;
      RECT 26.304 0.000 26.328 0.192 ;
    END
  END pma_tx[106]
  PIN pma_tx[107]
    DIRECTION OUTPUT ;
    USE SIGNAL ;
    SHAPE ABUTMENT ;
    PORT
      LAYER M5 ;
      RECT 26.496 0.000 26.520 0.192 ;
    END
  END pma_tx[107]
  PIN pma_tx[108]
    DIRECTION OUTPUT ;
    USE SIGNAL ;
    SHAPE ABUTMENT ;
    PORT
      LAYER M5 ;
      RECT 26.736 0.000 26.760 0.192 ;
    END
  END pma_tx[108]
  PIN pma_tx[109]
    DIRECTION OUTPUT ;
    USE SIGNAL ;
    SHAPE ABUTMENT ;
    PORT
      LAYER M5 ;
      RECT 26.928 0.000 26.952 0.192 ;
    END
  END pma_tx[109]
  PIN pma_tx[110]
    DIRECTION OUTPUT ;
    USE SIGNAL ;
    SHAPE ABUTMENT ;
    PORT
      LAYER M5 ;
      RECT 27.120 0.000 27.144 0.192 ;
    END
  END pma_tx[110]
  PIN pma_tx[111]
    DIRECTION OUTPUT ;
    USE SIGNAL ;
    SHAPE ABUTMENT ;
    PORT
      LAYER M5 ;
      RECT 27.360 0.000 27.384 0.192 ;
    END
  END pma_tx[111]
  PIN pma_tx[112]
    DIRECTION OUTPUT ;
    USE SIGNAL ;
    SHAPE ABUTMENT ;
    PORT
      LAYER M5 ;
      RECT 27.552 0.000 27.576 0.192 ;
    END
  END pma_tx[112]
  PIN pma_tx[113]
    DIRECTION OUTPUT ;
    USE SIGNAL ;
    SHAPE ABUTMENT ;
    PORT
      LAYER M5 ;
      RECT 27.744 0.000 27.768 0.192 ;
    END
  END pma_tx[113]
  PIN pma_tx[114]
    DIRECTION OUTPUT ;
    USE SIGNAL ;
    SHAPE ABUTMENT ;
    PORT
      LAYER M5 ;
      RECT 27.936 0.000 27.960 0.192 ;
    END
  END pma_tx[114]
  PIN pma_tx[115]
    DIRECTION OUTPUT ;
    USE SIGNAL ;
    SHAPE ABUTMENT ;
    PORT
      LAYER M5 ;
      RECT 28.176 0.000 28.200 0.192 ;
    END
  END pma_tx[115]
  PIN pma_tx[116]
    DIRECTION OUTPUT ;
    USE SIGNAL ;
    SHAPE ABUTMENT ;
    PORT
      LAYER M5 ;
      RECT 28.368 0.000 28.392 0.192 ;
    END
  END pma_tx[116]
  PIN pma_tx[117]
    DIRECTION OUTPUT ;
    USE SIGNAL ;
    SHAPE ABUTMENT ;
    PORT
      LAYER M5 ;
      RECT 28.560 0.000 28.584 0.192 ;
    END
  END pma_tx[117]
  PIN pma_tx[118]
    DIRECTION OUTPUT ;
    USE SIGNAL ;
    SHAPE ABUTMENT ;
    PORT
      LAYER M5 ;
      RECT 28.800 0.000 28.824 0.192 ;
    END
  END pma_tx[118]
  PIN pma_tx[119]
    DIRECTION OUTPUT ;
    USE SIGNAL ;
    SHAPE ABUTMENT ;
    PORT
      LAYER M5 ;
      RECT 28.992 0.000 29.016 0.192 ;
    END
  END pma_tx[119]
  PIN pma_tx[120]
    DIRECTION OUTPUT ;
    USE SIGNAL ;
    SHAPE ABUTMENT ;
    PORT
      LAYER M5 ;
      RECT 29.184 0.000 29.208 0.192 ;
    END
  END pma_tx[120]
  PIN pma_tx[121]
    DIRECTION OUTPUT ;
    USE SIGNAL ;
    SHAPE ABUTMENT ;
    PORT
      LAYER M5 ;
      RECT 29.376 0.000 29.400 0.192 ;
    END
  END pma_tx[121]
  PIN pma_tx[122]
    DIRECTION OUTPUT ;
    USE SIGNAL ;
    SHAPE ABUTMENT ;
    PORT
      LAYER M5 ;
      RECT 29.616 0.000 29.640 0.192 ;
    END
  END pma_tx[122]
  PIN pma_tx[123]
    DIRECTION OUTPUT ;
    USE SIGNAL ;
    SHAPE ABUTMENT ;
    PORT
      LAYER M5 ;
      RECT 29.808 0.000 29.832 0.192 ;
    END
  END pma_tx[123]
  PIN pma_tx[124]
    DIRECTION OUTPUT ;
    USE SIGNAL ;
    SHAPE ABUTMENT ;
    PORT
      LAYER M5 ;
      RECT 30.000 0.000 30.024 0.192 ;
    END
  END pma_tx[124]
  PIN pma_tx[125]
    DIRECTION OUTPUT ;
    USE SIGNAL ;
    SHAPE ABUTMENT ;
    PORT
      LAYER M5 ;
      RECT 30.240 0.000 30.264 0.192 ;
    END
  END pma_tx[125]
  PIN pma_tx[126]
    DIRECTION OUTPUT ;
    USE SIGNAL ;
    SHAPE ABUTMENT ;
    PORT
      LAYER M5 ;
      RECT 30.432 0.000 30.456 0.192 ;
    END
  END pma_tx[126]
  PIN pma_tx[127]
    DIRECTION OUTPUT ;
    USE SIGNAL ;
    SHAPE ABUTMENT ;
    PORT
      LAYER M5 ;
      RECT 30.624 0.000 30.648 0.192 ;
    END
  END pma_tx[127]
  PIN pma_tx[128]
    DIRECTION OUTPUT ;
    USE SIGNAL ;
    SHAPE ABUTMENT ;
    PORT
      LAYER M5 ;
      RECT 30.816 0.000 30.840 0.192 ;
    END
  END pma_tx[128]
  PIN pma_tx[129]
    DIRECTION OUTPUT ;
    USE SIGNAL ;
    SHAPE ABUTMENT ;
    PORT
      LAYER M5 ;
      RECT 31.056 0.000 31.080 0.192 ;
    END
  END pma_tx[129]
  PIN pma_tx[130]
    DIRECTION OUTPUT ;
    USE SIGNAL ;
    SHAPE ABUTMENT ;
    PORT
      LAYER M5 ;
      RECT 31.248 0.000 31.272 0.192 ;
    END
  END pma_tx[130]
  PIN pma_tx[131]
    DIRECTION OUTPUT ;
    USE SIGNAL ;
    SHAPE ABUTMENT ;
    PORT
      LAYER M5 ;
      RECT 31.440 0.000 31.464 0.192 ;
    END
  END pma_tx[131]
  PIN pma_tx[132]
    DIRECTION OUTPUT ;
    USE SIGNAL ;
    SHAPE ABUTMENT ;
    PORT
      LAYER M5 ;
      RECT 31.680 0.000 31.704 0.192 ;
    END
  END pma_tx[132]
  PIN pma_tx[133]
    DIRECTION OUTPUT ;
    USE SIGNAL ;
    SHAPE ABUTMENT ;
    PORT
      LAYER M5 ;
      RECT 31.872 0.000 31.896 0.192 ;
    END
  END pma_tx[133]
  PIN pma_tx[134]
    DIRECTION OUTPUT ;
    USE SIGNAL ;
    SHAPE ABUTMENT ;
    PORT
      LAYER M5 ;
      RECT 32.064 0.000 32.088 0.192 ;
    END
  END pma_tx[134]
  PIN pma_tx[135]
    DIRECTION OUTPUT ;
    USE SIGNAL ;
    SHAPE ABUTMENT ;
    PORT
      LAYER M5 ;
      RECT 32.256 0.000 32.280 0.192 ;
    END
  END pma_tx[135]
  PIN pma_tx[136]
    DIRECTION OUTPUT ;
    USE SIGNAL ;
    SHAPE ABUTMENT ;
    PORT
      LAYER M5 ;
      RECT 32.496 0.000 32.520 0.192 ;
    END
  END pma_tx[136]
  PIN pma_tx[137]
    DIRECTION OUTPUT ;
    USE SIGNAL ;
    SHAPE ABUTMENT ;
    PORT
      LAYER M5 ;
      RECT 32.688 0.000 32.712 0.192 ;
    END
  END pma_tx[137]
  PIN pma_tx[138]
    DIRECTION OUTPUT ;
    USE SIGNAL ;
    SHAPE ABUTMENT ;
    PORT
      LAYER M5 ;
      RECT 32.880 0.000 32.904 0.192 ;
    END
  END pma_tx[138]
  PIN pma_tx[139]
    DIRECTION OUTPUT ;
    USE SIGNAL ;
    SHAPE ABUTMENT ;
    PORT
      LAYER M5 ;
      RECT 33.120 0.000 33.144 0.192 ;
    END
  END pma_tx[139]
  PIN pma_tx[140]
    DIRECTION OUTPUT ;
    USE SIGNAL ;
    SHAPE ABUTMENT ;
    PORT
      LAYER M5 ;
      RECT 33.312 0.000 33.336 0.192 ;
    END
  END pma_tx[140]
  PIN pma_tx[141]
    DIRECTION OUTPUT ;
    USE SIGNAL ;
    SHAPE ABUTMENT ;
    PORT
      LAYER M5 ;
      RECT 33.504 0.000 33.528 0.192 ;
    END
  END pma_tx[141]
  PIN pma_tx[142]
    DIRECTION OUTPUT ;
    USE SIGNAL ;
    SHAPE ABUTMENT ;
    PORT
      LAYER M5 ;
      RECT 33.696 0.000 33.720 0.192 ;
    END
  END pma_tx[142]
  PIN pma_tx[143]
    DIRECTION OUTPUT ;
    USE SIGNAL ;
    SHAPE ABUTMENT ;
    PORT
      LAYER M5 ;
      RECT 33.936 0.000 33.960 0.192 ;
    END
  END pma_tx[143]
  PIN pma_tx[144]
    DIRECTION OUTPUT ;
    USE SIGNAL ;
    SHAPE ABUTMENT ;
    PORT
      LAYER M5 ;
      RECT 34.128 0.000 34.152 0.192 ;
    END
  END pma_tx[144]
  PIN pma_tx[145]
    DIRECTION OUTPUT ;
    USE SIGNAL ;
    SHAPE ABUTMENT ;
    PORT
      LAYER M5 ;
      RECT 34.320 0.000 34.344 0.192 ;
    END
  END pma_tx[145]
  PIN pma_tx[146]
    DIRECTION OUTPUT ;
    USE SIGNAL ;
    SHAPE ABUTMENT ;
    PORT
      LAYER M5 ;
      RECT 34.560 0.000 34.584 0.192 ;
    END
  END pma_tx[146]
  PIN pma_tx[147]
    DIRECTION OUTPUT ;
    USE SIGNAL ;
    SHAPE ABUTMENT ;
    PORT
      LAYER M5 ;
      RECT 34.752 0.000 34.776 0.192 ;
    END
  END pma_tx[147]
  PIN pma_tx[148]
    DIRECTION OUTPUT ;
    USE SIGNAL ;
    SHAPE ABUTMENT ;
    PORT
      LAYER M5 ;
      RECT 34.944 0.000 34.968 0.192 ;
    END
  END pma_tx[148]
  PIN pma_tx[149]
    DIRECTION OUTPUT ;
    USE SIGNAL ;
    SHAPE ABUTMENT ;
    PORT
      LAYER M5 ;
      RECT 35.184 0.000 35.208 0.192 ;
    END
  END pma_tx[149]
  PIN pma_tx[150]
    DIRECTION OUTPUT ;
    USE SIGNAL ;
    SHAPE ABUTMENT ;
    PORT
      LAYER M5 ;
      RECT 35.376 0.000 35.400 0.192 ;
    END
  END pma_tx[150]
  PIN pma_tx[151]
    DIRECTION OUTPUT ;
    USE SIGNAL ;
    SHAPE ABUTMENT ;
    PORT
      LAYER M5 ;
      RECT 35.568 0.000 35.592 0.192 ;
    END
  END pma_tx[151]
  PIN pma_tx[152]
    DIRECTION OUTPUT ;
    USE SIGNAL ;
    SHAPE ABUTMENT ;
    PORT
      LAYER M5 ;
      RECT 35.760 0.000 35.784 0.192 ;
    END
  END pma_tx[152]
  PIN pma_tx[153]
    DIRECTION OUTPUT ;
    USE SIGNAL ;
    SHAPE ABUTMENT ;
    PORT
      LAYER M5 ;
      RECT 36.000 0.000 36.024 0.192 ;
    END
  END pma_tx[153]
  PIN pma_tx[154]
    DIRECTION OUTPUT ;
    USE SIGNAL ;
    SHAPE ABUTMENT ;
    PORT
      LAYER M5 ;
      RECT 36.192 0.000 36.216 0.192 ;
    END
  END pma_tx[154]
  PIN pma_tx[155]
    DIRECTION OUTPUT ;
    USE SIGNAL ;
    SHAPE ABUTMENT ;
    PORT
      LAYER M5 ;
      RECT 36.384 0.000 36.408 0.192 ;
    END
  END pma_tx[155]
  PIN pma_tx[156]
    DIRECTION OUTPUT ;
    USE SIGNAL ;
    SHAPE ABUTMENT ;
    PORT
      LAYER M5 ;
      RECT 36.624 0.000 36.648 0.192 ;
    END
  END pma_tx[156]
  PIN pma_tx[157]
    DIRECTION OUTPUT ;
    USE SIGNAL ;
    SHAPE ABUTMENT ;
    PORT
      LAYER M5 ;
      RECT 36.816 0.000 36.840 0.192 ;
    END
  END pma_tx[157]
  PIN pma_tx[158]
    DIRECTION OUTPUT ;
    USE SIGNAL ;
    SHAPE ABUTMENT ;
    PORT
      LAYER M5 ;
      RECT 37.008 0.000 37.032 0.192 ;
    END
  END pma_tx[158]
  PIN pma_tx[159]
    DIRECTION OUTPUT ;
    USE SIGNAL ;
    SHAPE ABUTMENT ;
    PORT
      LAYER M5 ;
      RECT 37.200 0.000 37.224 0.192 ;
    END
  END pma_tx[159]
  PIN pma_tx[160]
    DIRECTION OUTPUT ;
    USE SIGNAL ;
    SHAPE ABUTMENT ;
    PORT
      LAYER M5 ;
      RECT 37.440 0.000 37.464 0.192 ;
    END
  END pma_tx[160]
  PIN pma_tx[161]
    DIRECTION OUTPUT ;
    USE SIGNAL ;
    SHAPE ABUTMENT ;
    PORT
      LAYER M5 ;
      RECT 37.632 0.000 37.656 0.192 ;
    END
  END pma_tx[161]
  PIN pma_tx[162]
    DIRECTION OUTPUT ;
    USE SIGNAL ;
    SHAPE ABUTMENT ;
    PORT
      LAYER M5 ;
      RECT 37.824 0.000 37.848 0.192 ;
    END
  END pma_tx[162]
  PIN pma_tx[163]
    DIRECTION OUTPUT ;
    USE SIGNAL ;
    SHAPE ABUTMENT ;
    PORT
      LAYER M5 ;
      RECT 38.064 0.000 38.088 0.192 ;
    END
  END pma_tx[163]
  PIN pma_tx[164]
    DIRECTION OUTPUT ;
    USE SIGNAL ;
    SHAPE ABUTMENT ;
    PORT
      LAYER M5 ;
      RECT 38.256 0.000 38.280 0.192 ;
    END
  END pma_tx[164]
  PIN pma_tx[165]
    DIRECTION OUTPUT ;
    USE SIGNAL ;
    SHAPE ABUTMENT ;
    PORT
      LAYER M5 ;
      RECT 38.448 0.000 38.472 0.192 ;
    END
  END pma_tx[165]
  PIN pma_tx[166]
    DIRECTION OUTPUT ;
    USE SIGNAL ;
    SHAPE ABUTMENT ;
    PORT
      LAYER M5 ;
      RECT 38.640 0.000 38.664 0.192 ;
    END
  END pma_tx[166]
  PIN pma_tx[167]
    DIRECTION OUTPUT ;
    USE SIGNAL ;
    SHAPE ABUTMENT ;
    PORT
      LAYER M5 ;
      RECT 38.880 0.000 38.904 0.192 ;
    END
  END pma_tx[167]
  PIN pma_tx[168]
    DIRECTION OUTPUT ;
    USE SIGNAL ;
    SHAPE ABUTMENT ;
    PORT
      LAYER M5 ;
      RECT 39.072 0.000 39.096 0.192 ;
    END
  END pma_tx[168]
  PIN pma_tx[169]
    DIRECTION OUTPUT ;
    USE SIGNAL ;
    SHAPE ABUTMENT ;
    PORT
      LAYER M5 ;
      RECT 39.264 0.000 39.288 0.192 ;
    END
  END pma_tx[169]
  PIN pma_tx[170]
    DIRECTION OUTPUT ;
    USE SIGNAL ;
    SHAPE ABUTMENT ;
    PORT
      LAYER M5 ;
      RECT 39.504 0.000 39.528 0.192 ;
    END
  END pma_tx[170]
  PIN pma_tx[171]
    DIRECTION OUTPUT ;
    USE SIGNAL ;
    SHAPE ABUTMENT ;
    PORT
      LAYER M5 ;
      RECT 39.696 0.000 39.720 0.192 ;
    END
  END pma_tx[171]
  PIN pma_tx[172]
    DIRECTION OUTPUT ;
    USE SIGNAL ;
    SHAPE ABUTMENT ;
    PORT
      LAYER M5 ;
      RECT 39.888 0.000 39.912 0.192 ;
    END
  END pma_tx[172]
  PIN pma_tx[173]
    DIRECTION OUTPUT ;
    USE SIGNAL ;
    SHAPE ABUTMENT ;
    PORT
      LAYER M5 ;
      RECT 40.080 0.000 40.104 0.192 ;
    END
  END pma_tx[173]
  PIN pma_tx[174]
    DIRECTION OUTPUT ;
    USE SIGNAL ;
    SHAPE ABUTMENT ;
    PORT
      LAYER M5 ;
      RECT 40.320 0.000 40.344 0.192 ;
    END
  END pma_tx[174]
  PIN pma_tx[175]
    DIRECTION OUTPUT ;
    USE SIGNAL ;
    SHAPE ABUTMENT ;
    PORT
      LAYER M5 ;
      RECT 40.512 0.000 40.536 0.192 ;
    END
  END pma_tx[175]
  PIN pma_tx[176]
    DIRECTION OUTPUT ;
    USE SIGNAL ;
    SHAPE ABUTMENT ;
    PORT
      LAYER M5 ;
      RECT 40.704 0.000 40.728 0.192 ;
    END
  END pma_tx[176]
  PIN pma_tx[177]
    DIRECTION OUTPUT ;
    USE SIGNAL ;
    SHAPE ABUTMENT ;
    PORT
      LAYER M5 ;
      RECT 40.944 0.000 40.968 0.192 ;
    END
  END pma_tx[177]
  PIN pma_tx[178]
    DIRECTION OUTPUT ;
    USE SIGNAL ;
    SHAPE ABUTMENT ;
    PORT
      LAYER M5 ;
      RECT 41.136 0.000 41.160 0.192 ;
    END
  END pma_tx[178]
  PIN pma_tx[179]
    DIRECTION OUTPUT ;
    USE SIGNAL ;
    SHAPE ABUTMENT ;
    PORT
      LAYER M5 ;
      RECT 41.328 0.000 41.352 0.192 ;
    END
  END pma_tx[179]
  PIN pma_tx[180]
    DIRECTION OUTPUT ;
    USE SIGNAL ;
    SHAPE ABUTMENT ;
    PORT
      LAYER M5 ;
      RECT 41.520 0.000 41.544 0.192 ;
    END
  END pma_tx[180]
  PIN pma_tx[181]
    DIRECTION OUTPUT ;
    USE SIGNAL ;
    SHAPE ABUTMENT ;
    PORT
      LAYER M5 ;
      RECT 41.760 0.000 41.784 0.192 ;
    END
  END pma_tx[181]
  PIN pma_tx[182]
    DIRECTION OUTPUT ;
    USE SIGNAL ;
    SHAPE ABUTMENT ;
    PORT
      LAYER M5 ;
      RECT 41.952 0.000 41.976 0.192 ;
    END
  END pma_tx[182]
  PIN pma_tx[183]
    DIRECTION OUTPUT ;
    USE SIGNAL ;
    SHAPE ABUTMENT ;
    PORT
      LAYER M5 ;
      RECT 42.144 0.000 42.168 0.192 ;
    END
  END pma_tx[183]
  PIN pma_tx[184]
    DIRECTION OUTPUT ;
    USE SIGNAL ;
    SHAPE ABUTMENT ;
    PORT
      LAYER M5 ;
      RECT 42.384 0.000 42.408 0.192 ;
    END
  END pma_tx[184]
  PIN pma_tx[185]
    DIRECTION OUTPUT ;
    USE SIGNAL ;
    SHAPE ABUTMENT ;
    PORT
      LAYER M5 ;
      RECT 42.576 0.000 42.600 0.192 ;
    END
  END pma_tx[185]
  PIN pma_tx[186]
    DIRECTION OUTPUT ;
    USE SIGNAL ;
    SHAPE ABUTMENT ;
    PORT
      LAYER M5 ;
      RECT 42.768 0.000 42.792 0.192 ;
    END
  END pma_tx[186]
  PIN pma_tx[187]
    DIRECTION OUTPUT ;
    USE SIGNAL ;
    SHAPE ABUTMENT ;
    PORT
      LAYER M5 ;
      RECT 42.960 0.000 42.984 0.192 ;
    END
  END pma_tx[187]
  PIN pma_tx[188]
    DIRECTION OUTPUT ;
    USE SIGNAL ;
    SHAPE ABUTMENT ;
    PORT
      LAYER M5 ;
      RECT 43.200 0.000 43.224 0.192 ;
    END
  END pma_tx[188]
  PIN pma_tx[189]
    DIRECTION OUTPUT ;
    USE SIGNAL ;
    SHAPE ABUTMENT ;
    PORT
      LAYER M5 ;
      RECT 43.392 0.000 43.416 0.192 ;
    END
  END pma_tx[189]
  PIN pma_tx[190]
    DIRECTION OUTPUT ;
    USE SIGNAL ;
    SHAPE ABUTMENT ;
    PORT
      LAYER M5 ;
      RECT 43.584 0.000 43.608 0.192 ;
    END
  END pma_tx[190]
  PIN pma_tx[191]
    DIRECTION OUTPUT ;
    USE SIGNAL ;
    SHAPE ABUTMENT ;
    PORT
      LAYER M5 ;
      RECT 43.824 0.000 43.848 0.192 ;
    END
  END pma_tx[191]
  PIN pma_tx[192]
    DIRECTION OUTPUT ;
    USE SIGNAL ;
    SHAPE ABUTMENT ;
    PORT
      LAYER M5 ;
      RECT 44.016 0.000 44.040 0.192 ;
    END
  END pma_tx[192]
  PIN pma_tx[193]
    DIRECTION OUTPUT ;
    USE SIGNAL ;
    SHAPE ABUTMENT ;
    PORT
      LAYER M5 ;
      RECT 44.208 0.000 44.232 0.192 ;
    END
  END pma_tx[193]
  PIN pma_tx[194]
    DIRECTION OUTPUT ;
    USE SIGNAL ;
    SHAPE ABUTMENT ;
    PORT
      LAYER M5 ;
      RECT 44.400 0.000 44.424 0.192 ;
    END
  END pma_tx[194]
  PIN pma_tx[195]
    DIRECTION OUTPUT ;
    USE SIGNAL ;
    SHAPE ABUTMENT ;
    PORT
      LAYER M5 ;
      RECT 44.640 0.000 44.664 0.192 ;
    END
  END pma_tx[195]
  PIN pma_tx[196]
    DIRECTION OUTPUT ;
    USE SIGNAL ;
    SHAPE ABUTMENT ;
    PORT
      LAYER M5 ;
      RECT 44.832 0.000 44.856 0.192 ;
    END
  END pma_tx[196]
  PIN pma_tx[197]
    DIRECTION OUTPUT ;
    USE SIGNAL ;
    SHAPE ABUTMENT ;
    PORT
      LAYER M5 ;
      RECT 45.024 0.000 45.048 0.192 ;
    END
  END pma_tx[197]
  PIN pma_tx[198]
    DIRECTION OUTPUT ;
    USE SIGNAL ;
    SHAPE ABUTMENT ;
    PORT
      LAYER M5 ;
      RECT 45.264 0.000 45.288 0.192 ;
    END
  END pma_tx[198]
  PIN pma_tx[199]
    DIRECTION OUTPUT ;
    USE SIGNAL ;
    SHAPE ABUTMENT ;
    PORT
      LAYER M5 ;
      RECT 45.456 0.000 45.480 0.192 ;
    END
  END pma_tx[199]
  PIN pma_tx[200]
    DIRECTION OUTPUT ;
    USE SIGNAL ;
    SHAPE ABUTMENT ;
    PORT
      LAYER M5 ;
      RECT 45.648 0.000 45.672 0.192 ;
    END
  END pma_tx[200]
  PIN pma_tx[201]
    DIRECTION OUTPUT ;
    USE SIGNAL ;
    SHAPE ABUTMENT ;
    PORT
      LAYER M5 ;
      RECT 45.888 0.000 45.912 0.192 ;
    END
  END pma_tx[201]
  PIN pma_tx[202]
    DIRECTION OUTPUT ;
    USE SIGNAL ;
    SHAPE ABUTMENT ;
    PORT
      LAYER M5 ;
      RECT 46.080 0.000 46.104 0.192 ;
    END
  END pma_tx[202]
  PIN pma_tx[203]
    DIRECTION OUTPUT ;
    USE SIGNAL ;
    SHAPE ABUTMENT ;
    PORT
      LAYER M5 ;
      RECT 46.272 0.000 46.296 0.192 ;
    END
  END pma_tx[203]
  PIN pma_tx[204]
    DIRECTION OUTPUT ;
    USE SIGNAL ;
    SHAPE ABUTMENT ;
    PORT
      LAYER M5 ;
      RECT 46.464 0.000 46.488 0.192 ;
    END
  END pma_tx[204]
  PIN pma_tx[205]
    DIRECTION OUTPUT ;
    USE SIGNAL ;
    SHAPE ABUTMENT ;
    PORT
      LAYER M5 ;
      RECT 46.704 0.000 46.728 0.192 ;
    END
  END pma_tx[205]
  PIN pma_tx[206]
    DIRECTION OUTPUT ;
    USE SIGNAL ;
    SHAPE ABUTMENT ;
    PORT
      LAYER M5 ;
      RECT 46.896 0.000 46.920 0.192 ;
    END
  END pma_tx[206]
  PIN pma_tx[207]
    DIRECTION OUTPUT ;
    USE SIGNAL ;
    SHAPE ABUTMENT ;
    PORT
      LAYER M5 ;
      RECT 47.088 0.000 47.112 0.192 ;
    END
  END pma_tx[207]
  PIN pma_tx[208]
    DIRECTION OUTPUT ;
    USE SIGNAL ;
    SHAPE ABUTMENT ;
    PORT
      LAYER M5 ;
      RECT 47.328 0.000 47.352 0.192 ;
    END
  END pma_tx[208]
  PIN pma_tx[209]
    DIRECTION OUTPUT ;
    USE SIGNAL ;
    SHAPE ABUTMENT ;
    PORT
      LAYER M5 ;
      RECT 47.520 0.000 47.544 0.192 ;
    END
  END pma_tx[209]
  PIN pma_tx[210]
    DIRECTION OUTPUT ;
    USE SIGNAL ;
    SHAPE ABUTMENT ;
    PORT
      LAYER M5 ;
      RECT 47.712 0.000 47.736 0.192 ;
    END
  END pma_tx[210]
  PIN pma_tx[211]
    DIRECTION OUTPUT ;
    USE SIGNAL ;
    SHAPE ABUTMENT ;
    PORT
      LAYER M5 ;
      RECT 47.904 0.000 47.928 0.192 ;
    END
  END pma_tx[211]
  PIN pma_tx[212]
    DIRECTION OUTPUT ;
    USE SIGNAL ;
    SHAPE ABUTMENT ;
    PORT
      LAYER M5 ;
      RECT 48.144 0.000 48.168 0.192 ;
    END
  END pma_tx[212]
  PIN pma_tx[213]
    DIRECTION OUTPUT ;
    USE SIGNAL ;
    SHAPE ABUTMENT ;
    PORT
      LAYER M5 ;
      RECT 48.336 0.000 48.360 0.192 ;
    END
  END pma_tx[213]
  PIN pma_tx[214]
    DIRECTION OUTPUT ;
    USE SIGNAL ;
    SHAPE ABUTMENT ;
    PORT
      LAYER M5 ;
      RECT 48.528 0.000 48.552 0.192 ;
    END
  END pma_tx[214]
  PIN pma_tx[215]
    DIRECTION OUTPUT ;
    USE SIGNAL ;
    SHAPE ABUTMENT ;
    PORT
      LAYER M5 ;
      RECT 48.768 0.000 48.792 0.192 ;
    END
  END pma_tx[215]
  PIN pma_tx[216]
    DIRECTION OUTPUT ;
    USE SIGNAL ;
    SHAPE ABUTMENT ;
    PORT
      LAYER M5 ;
      RECT 48.960 0.000 48.984 0.192 ;
    END
  END pma_tx[216]
  PIN pma_tx[217]
    DIRECTION OUTPUT ;
    USE SIGNAL ;
    SHAPE ABUTMENT ;
    PORT
      LAYER M5 ;
      RECT 49.152 0.000 49.176 0.192 ;
    END
  END pma_tx[217]
  PIN pma_tx[218]
    DIRECTION OUTPUT ;
    USE SIGNAL ;
    SHAPE ABUTMENT ;
    PORT
      LAYER M5 ;
      RECT 49.344 0.000 49.368 0.192 ;
    END
  END pma_tx[218]
  PIN pma_tx[219]
    DIRECTION OUTPUT ;
    USE SIGNAL ;
    SHAPE ABUTMENT ;
    PORT
      LAYER M5 ;
      RECT 49.584 0.000 49.608 0.192 ;
    END
  END pma_tx[219]
  PIN pma_tx[220]
    DIRECTION OUTPUT ;
    USE SIGNAL ;
    SHAPE ABUTMENT ;
    PORT
      LAYER M5 ;
      RECT 49.776 0.000 49.800 0.192 ;
    END
  END pma_tx[220]
  PIN pma_tx[221]
    DIRECTION OUTPUT ;
    USE SIGNAL ;
    SHAPE ABUTMENT ;
    PORT
      LAYER M5 ;
      RECT 49.968 0.000 49.992 0.192 ;
    END
  END pma_tx[221]
  PIN pma_tx[222]
    DIRECTION OUTPUT ;
    USE SIGNAL ;
    SHAPE ABUTMENT ;
    PORT
      LAYER M5 ;
      RECT 50.208 0.000 50.232 0.192 ;
    END
  END pma_tx[222]
  PIN pma_tx[223]
    DIRECTION OUTPUT ;
    USE SIGNAL ;
    SHAPE ABUTMENT ;
    PORT
      LAYER M5 ;
      RECT 50.400 0.000 50.424 0.192 ;
    END
  END pma_tx[223]
  PIN pma_tx[224]
    DIRECTION OUTPUT ;
    USE SIGNAL ;
    SHAPE ABUTMENT ;
    PORT
      LAYER M5 ;
      RECT 50.592 0.000 50.616 0.192 ;
    END
  END pma_tx[224]
  PIN pma_tx[225]
    DIRECTION OUTPUT ;
    USE SIGNAL ;
    SHAPE ABUTMENT ;
    PORT
      LAYER M5 ;
      RECT 50.784 0.000 50.808 0.192 ;
    END
  END pma_tx[225]
  PIN pma_tx[226]
    DIRECTION OUTPUT ;
    USE SIGNAL ;
    SHAPE ABUTMENT ;
    PORT
      LAYER M5 ;
      RECT 51.024 0.000 51.048 0.192 ;
    END
  END pma_tx[226]
  PIN pma_tx[227]
    DIRECTION OUTPUT ;
    USE SIGNAL ;
    SHAPE ABUTMENT ;
    PORT
      LAYER M5 ;
      RECT 51.216 0.000 51.240 0.192 ;
    END
  END pma_tx[227]
  PIN pma_tx[228]
    DIRECTION OUTPUT ;
    USE SIGNAL ;
    SHAPE ABUTMENT ;
    PORT
      LAYER M5 ;
      RECT 51.408 0.000 51.432 0.192 ;
    END
  END pma_tx[228]
  PIN pma_tx[229]
    DIRECTION OUTPUT ;
    USE SIGNAL ;
    SHAPE ABUTMENT ;
    PORT
      LAYER M5 ;
      RECT 51.648 0.000 51.672 0.192 ;
    END
  END pma_tx[229]
  PIN pma_tx[230]
    DIRECTION OUTPUT ;
    USE SIGNAL ;
    SHAPE ABUTMENT ;
    PORT
      LAYER M5 ;
      RECT 51.840 0.000 51.864 0.192 ;
    END
  END pma_tx[230]
  PIN pma_tx[231]
    DIRECTION OUTPUT ;
    USE SIGNAL ;
    SHAPE ABUTMENT ;
    PORT
      LAYER M5 ;
      RECT 52.032 0.000 52.056 0.192 ;
    END
  END pma_tx[231]
  PIN pma_tx[232]
    DIRECTION OUTPUT ;
    USE SIGNAL ;
    SHAPE ABUTMENT ;
    PORT
      LAYER M5 ;
      RECT 52.224 0.000 52.248 0.192 ;
    END
  END pma_tx[232]
  PIN pma_tx[233]
    DIRECTION OUTPUT ;
    USE SIGNAL ;
    SHAPE ABUTMENT ;
    PORT
      LAYER M5 ;
      RECT 52.464 0.000 52.488 0.192 ;
    END
  END pma_tx[233]
  PIN pma_tx[234]
    DIRECTION OUTPUT ;
    USE SIGNAL ;
    SHAPE ABUTMENT ;
    PORT
      LAYER M5 ;
      RECT 52.656 0.000 52.680 0.192 ;
    END
  END pma_tx[234]
  PIN pma_tx[235]
    DIRECTION OUTPUT ;
    USE SIGNAL ;
    SHAPE ABUTMENT ;
    PORT
      LAYER M5 ;
      RECT 52.848 0.000 52.872 0.192 ;
    END
  END pma_tx[235]
  PIN pma_tx[236]
    DIRECTION OUTPUT ;
    USE SIGNAL ;
    SHAPE ABUTMENT ;
    PORT
      LAYER M5 ;
      RECT 53.088 0.000 53.112 0.192 ;
    END
  END pma_tx[236]
  PIN pma_tx[237]
    DIRECTION OUTPUT ;
    USE SIGNAL ;
    SHAPE ABUTMENT ;
    PORT
      LAYER M5 ;
      RECT 53.280 0.000 53.304 0.192 ;
    END
  END pma_tx[237]
  PIN pma_tx[238]
    DIRECTION OUTPUT ;
    USE SIGNAL ;
    SHAPE ABUTMENT ;
    PORT
      LAYER M5 ;
      RECT 53.472 0.000 53.496 0.192 ;
    END
  END pma_tx[238]
  PIN pma_tx[239]
    DIRECTION OUTPUT ;
    USE SIGNAL ;
    SHAPE ABUTMENT ;
    PORT
      LAYER M5 ;
      RECT 53.664 0.000 53.688 0.192 ;
    END
  END pma_tx[239]
  PIN pma_tx[240]
    DIRECTION OUTPUT ;
    USE SIGNAL ;
    SHAPE ABUTMENT ;
    PORT
      LAYER M5 ;
      RECT 53.904 0.000 53.928 0.192 ;
    END
  END pma_tx[240]
  PIN pma_tx[241]
    DIRECTION OUTPUT ;
    USE SIGNAL ;
    SHAPE ABUTMENT ;
    PORT
      LAYER M5 ;
      RECT 54.096 0.000 54.120 0.192 ;
    END
  END pma_tx[241]
  PIN pma_tx[242]
    DIRECTION OUTPUT ;
    USE SIGNAL ;
    SHAPE ABUTMENT ;
    PORT
      LAYER M5 ;
      RECT 54.288 0.000 54.312 0.192 ;
    END
  END pma_tx[242]
  PIN pma_tx[243]
    DIRECTION OUTPUT ;
    USE SIGNAL ;
    SHAPE ABUTMENT ;
    PORT
      LAYER M5 ;
      RECT 54.528 0.000 54.552 0.192 ;
    END
  END pma_tx[243]
  PIN pma_tx[244]
    DIRECTION OUTPUT ;
    USE SIGNAL ;
    SHAPE ABUTMENT ;
    PORT
      LAYER M5 ;
      RECT 54.720 0.000 54.744 0.192 ;
    END
  END pma_tx[244]
  PIN pma_tx[245]
    DIRECTION OUTPUT ;
    USE SIGNAL ;
    SHAPE ABUTMENT ;
    PORT
      LAYER M5 ;
      RECT 54.912 0.000 54.936 0.192 ;
    END
  END pma_tx[245]
  PIN pma_tx[246]
    DIRECTION OUTPUT ;
    USE SIGNAL ;
    SHAPE ABUTMENT ;
    PORT
      LAYER M5 ;
      RECT 55.104 0.000 55.128 0.192 ;
    END
  END pma_tx[246]
  PIN pma_tx[247]
    DIRECTION OUTPUT ;
    USE SIGNAL ;
    SHAPE ABUTMENT ;
    PORT
      LAYER M5 ;
      RECT 55.344 0.000 55.368 0.192 ;
    END
  END pma_tx[247]
  PIN pma_tx[248]
    DIRECTION OUTPUT ;
    USE SIGNAL ;
    SHAPE ABUTMENT ;
    PORT
      LAYER M5 ;
      RECT 55.536 0.000 55.560 0.192 ;
    END
  END pma_tx[248]
  PIN pma_tx[249]
    DIRECTION OUTPUT ;
    USE SIGNAL ;
    SHAPE ABUTMENT ;
    PORT
      LAYER M5 ;
      RECT 55.728 0.000 55.752 0.192 ;
    END
  END pma_tx[249]
  PIN pma_tx[250]
    DIRECTION OUTPUT ;
    USE SIGNAL ;
    SHAPE ABUTMENT ;
    PORT
      LAYER M5 ;
      RECT 55.968 0.000 55.992 0.192 ;
    END
  END pma_tx[250]
  PIN pma_tx[251]
    DIRECTION OUTPUT ;
    USE SIGNAL ;
    SHAPE ABUTMENT ;
    PORT
      LAYER M5 ;
      RECT 56.160 0.000 56.184 0.192 ;
    END
  END pma_tx[251]
  PIN pma_tx[252]
    DIRECTION OUTPUT ;
    USE SIGNAL ;
    SHAPE ABUTMENT ;
    PORT
      LAYER M5 ;
      RECT 56.352 0.000 56.376 0.192 ;
    END
  END pma_tx[252]
  PIN pma_tx[253]
    DIRECTION OUTPUT ;
    USE SIGNAL ;
    SHAPE ABUTMENT ;
    PORT
      LAYER M5 ;
      RECT 56.592 0.000 56.616 0.192 ;
    END
  END pma_tx[253]
  PIN pma_tx[254]
    DIRECTION OUTPUT ;
    USE SIGNAL ;
    SHAPE ABUTMENT ;
    PORT
      LAYER M5 ;
      RECT 56.784 0.000 56.808 0.192 ;
    END
  END pma_tx[254]
  PIN pma_tx[255]
    DIRECTION OUTPUT ;
    USE SIGNAL ;
    SHAPE ABUTMENT ;
    PORT
      LAYER M5 ;
      RECT 56.976 0.000 57.000 0.192 ;
    END
  END pma_tx[255]
  PIN pma_tx[256]
    DIRECTION OUTPUT ;
    USE SIGNAL ;
    SHAPE ABUTMENT ;
    PORT
      LAYER M5 ;
      RECT 57.168 0.000 57.192 0.192 ;
    END
  END pma_tx[256]
  PIN pma_tx[257]
    DIRECTION OUTPUT ;
    USE SIGNAL ;
    SHAPE ABUTMENT ;
    PORT
      LAYER M5 ;
      RECT 57.408 0.000 57.432 0.192 ;
    END
  END pma_tx[257]
  PIN pma_tx[258]
    DIRECTION OUTPUT ;
    USE SIGNAL ;
    SHAPE ABUTMENT ;
    PORT
      LAYER M5 ;
      RECT 57.600 0.000 57.624 0.192 ;
    END
  END pma_tx[258]
  PIN pma_tx[259]
    DIRECTION OUTPUT ;
    USE SIGNAL ;
    SHAPE ABUTMENT ;
    PORT
      LAYER M5 ;
      RECT 57.792 0.000 57.816 0.192 ;
    END
  END pma_tx[259]
  PIN pma_tx[260]
    DIRECTION OUTPUT ;
    USE SIGNAL ;
    SHAPE ABUTMENT ;
    PORT
      LAYER M5 ;
      RECT 58.032 0.000 58.056 0.192 ;
    END
  END pma_tx[260]
  PIN pma_tx[261]
    DIRECTION OUTPUT ;
    USE SIGNAL ;
    SHAPE ABUTMENT ;
    PORT
      LAYER M5 ;
      RECT 58.224 0.000 58.248 0.192 ;
    END
  END pma_tx[261]
  PIN pma_tx[262]
    DIRECTION OUTPUT ;
    USE SIGNAL ;
    SHAPE ABUTMENT ;
    PORT
      LAYER M5 ;
      RECT 58.416 0.000 58.440 0.192 ;
    END
  END pma_tx[262]
  PIN pma_tx[263]
    DIRECTION OUTPUT ;
    USE SIGNAL ;
    SHAPE ABUTMENT ;
    PORT
      LAYER M5 ;
      RECT 58.608 0.000 58.632 0.192 ;
    END
  END pma_tx[263]
  PIN pma_tx[264]
    DIRECTION OUTPUT ;
    USE SIGNAL ;
    SHAPE ABUTMENT ;
    PORT
      LAYER M5 ;
      RECT 58.848 0.000 58.872 0.192 ;
    END
  END pma_tx[264]
  PIN pma_tx[265]
    DIRECTION OUTPUT ;
    USE SIGNAL ;
    SHAPE ABUTMENT ;
    PORT
      LAYER M5 ;
      RECT 59.040 0.000 59.064 0.192 ;
    END
  END pma_tx[265]
  PIN pma_tx[266]
    DIRECTION OUTPUT ;
    USE SIGNAL ;
    SHAPE ABUTMENT ;
    PORT
      LAYER M5 ;
      RECT 59.232 0.000 59.256 0.192 ;
    END
  END pma_tx[266]
  PIN pma_tx[267]
    DIRECTION OUTPUT ;
    USE SIGNAL ;
    SHAPE ABUTMENT ;
    PORT
      LAYER M5 ;
      RECT 59.472 0.000 59.496 0.192 ;
    END
  END pma_tx[267]
  PIN pma_tx[268]
    DIRECTION OUTPUT ;
    USE SIGNAL ;
    SHAPE ABUTMENT ;
    PORT
      LAYER M5 ;
      RECT 59.664 0.000 59.688 0.192 ;
    END
  END pma_tx[268]
  PIN pma_tx[269]
    DIRECTION OUTPUT ;
    USE SIGNAL ;
    SHAPE ABUTMENT ;
    PORT
      LAYER M5 ;
      RECT 59.856 0.000 59.880 0.192 ;
    END
  END pma_tx[269]
  PIN pma_tx[270]
    DIRECTION OUTPUT ;
    USE SIGNAL ;
    SHAPE ABUTMENT ;
    PORT
      LAYER M5 ;
      RECT 60.048 0.000 60.072 0.192 ;
    END
  END pma_tx[270]
  PIN pma_tx[271]
    DIRECTION OUTPUT ;
    USE SIGNAL ;
    SHAPE ABUTMENT ;
    PORT
      LAYER M5 ;
      RECT 60.288 0.000 60.312 0.192 ;
    END
  END pma_tx[271]
  PIN pma_tx[272]
    DIRECTION OUTPUT ;
    USE SIGNAL ;
    SHAPE ABUTMENT ;
    PORT
      LAYER M5 ;
      RECT 60.480 0.000 60.504 0.192 ;
    END
  END pma_tx[272]
  PIN pma_tx[273]
    DIRECTION OUTPUT ;
    USE SIGNAL ;
    SHAPE ABUTMENT ;
    PORT
      LAYER M5 ;
      RECT 60.672 0.000 60.696 0.192 ;
    END
  END pma_tx[273]
  PIN pma_tx[274]
    DIRECTION OUTPUT ;
    USE SIGNAL ;
    SHAPE ABUTMENT ;
    PORT
      LAYER M5 ;
      RECT 60.912 0.000 60.936 0.192 ;
    END
  END pma_tx[274]
  PIN pma_tx[275]
    DIRECTION OUTPUT ;
    USE SIGNAL ;
    SHAPE ABUTMENT ;
    PORT
      LAYER M5 ;
      RECT 61.104 0.000 61.128 0.192 ;
    END
  END pma_tx[275]
  PIN pma_tx[276]
    DIRECTION OUTPUT ;
    USE SIGNAL ;
    SHAPE ABUTMENT ;
    PORT
      LAYER M5 ;
      RECT 61.296 0.000 61.320 0.192 ;
    END
  END pma_tx[276]
  PIN pma_tx[277]
    DIRECTION OUTPUT ;
    USE SIGNAL ;
    SHAPE ABUTMENT ;
    PORT
      LAYER M5 ;
      RECT 61.488 0.000 61.512 0.192 ;
    END
  END pma_tx[277]
  PIN pma_tx[278]
    DIRECTION OUTPUT ;
    USE SIGNAL ;
    SHAPE ABUTMENT ;
    PORT
      LAYER M5 ;
      RECT 61.728 0.000 61.752 0.192 ;
    END
  END pma_tx[278]
  PIN pma_tx[279]
    DIRECTION OUTPUT ;
    USE SIGNAL ;
    SHAPE ABUTMENT ;
    PORT
      LAYER M5 ;
      RECT 61.920 0.000 61.944 0.192 ;
    END
  END pma_tx[279]
  PIN pma_tx[280]
    DIRECTION OUTPUT ;
    USE SIGNAL ;
    SHAPE ABUTMENT ;
    PORT
      LAYER M5 ;
      RECT 62.112 0.000 62.136 0.192 ;
    END
  END pma_tx[280]
  PIN pma_tx[281]
    DIRECTION OUTPUT ;
    USE SIGNAL ;
    SHAPE ABUTMENT ;
    PORT
      LAYER M5 ;
      RECT 62.352 0.000 62.376 0.192 ;
    END
  END pma_tx[281]
  PIN pma_tx[282]
    DIRECTION OUTPUT ;
    USE SIGNAL ;
    SHAPE ABUTMENT ;
    PORT
      LAYER M5 ;
      RECT 62.544 0.000 62.568 0.192 ;
    END
  END pma_tx[282]
  PIN pma_tx[283]
    DIRECTION OUTPUT ;
    USE SIGNAL ;
    SHAPE ABUTMENT ;
    PORT
      LAYER M5 ;
      RECT 62.736 0.000 62.760 0.192 ;
    END
  END pma_tx[283]
  PIN pma_tx[284]
    DIRECTION OUTPUT ;
    USE SIGNAL ;
    SHAPE ABUTMENT ;
    PORT
      LAYER M5 ;
      RECT 62.928 0.000 62.952 0.192 ;
    END
  END pma_tx[284]
  PIN pma_tx[285]
    DIRECTION OUTPUT ;
    USE SIGNAL ;
    SHAPE ABUTMENT ;
    PORT
      LAYER M5 ;
      RECT 63.168 0.000 63.192 0.192 ;
    END
  END pma_tx[285]
  PIN pma_tx[286]
    DIRECTION OUTPUT ;
    USE SIGNAL ;
    SHAPE ABUTMENT ;
    PORT
      LAYER M5 ;
      RECT 63.360 0.000 63.384 0.192 ;
    END
  END pma_tx[286]
  PIN pma_tx[287]
    DIRECTION OUTPUT ;
    USE SIGNAL ;
    SHAPE ABUTMENT ;
    PORT
      LAYER M5 ;
      RECT 63.552 0.000 63.576 0.192 ;
    END
  END pma_tx[287]
  PIN pma_tx[288]
    DIRECTION OUTPUT ;
    USE SIGNAL ;
    SHAPE ABUTMENT ;
    PORT
      LAYER M5 ;
      RECT 63.792 0.000 63.816 0.192 ;
    END
  END pma_tx[288]
  PIN pma_tx[289]
    DIRECTION OUTPUT ;
    USE SIGNAL ;
    SHAPE ABUTMENT ;
    PORT
      LAYER M5 ;
      RECT 63.984 0.000 64.008 0.192 ;
    END
  END pma_tx[289]
  PIN pma_tx[290]
    DIRECTION OUTPUT ;
    USE SIGNAL ;
    SHAPE ABUTMENT ;
    PORT
      LAYER M5 ;
      RECT 64.176 0.000 64.200 0.192 ;
    END
  END pma_tx[290]
  PIN pma_tx[291]
    DIRECTION OUTPUT ;
    USE SIGNAL ;
    SHAPE ABUTMENT ;
    PORT
      LAYER M5 ;
      RECT 64.368 0.000 64.392 0.192 ;
    END
  END pma_tx[291]
  PIN pma_tx[292]
    DIRECTION OUTPUT ;
    USE SIGNAL ;
    SHAPE ABUTMENT ;
    PORT
      LAYER M5 ;
      RECT 64.608 0.000 64.632 0.192 ;
    END
  END pma_tx[292]
  PIN pma_tx[293]
    DIRECTION OUTPUT ;
    USE SIGNAL ;
    SHAPE ABUTMENT ;
    PORT
      LAYER M5 ;
      RECT 64.800 0.000 64.824 0.192 ;
    END
  END pma_tx[293]
  PIN pma_tx[294]
    DIRECTION OUTPUT ;
    USE SIGNAL ;
    SHAPE ABUTMENT ;
    PORT
      LAYER M5 ;
      RECT 64.992 0.000 65.016 0.192 ;
    END
  END pma_tx[294]
  PIN pma_tx[295]
    DIRECTION OUTPUT ;
    USE SIGNAL ;
    SHAPE ABUTMENT ;
    PORT
      LAYER M5 ;
      RECT 65.232 0.000 65.256 0.192 ;
    END
  END pma_tx[295]
  PIN pma_tx[296]
    DIRECTION OUTPUT ;
    USE SIGNAL ;
    SHAPE ABUTMENT ;
    PORT
      LAYER M5 ;
      RECT 65.424 0.000 65.448 0.192 ;
    END
  END pma_tx[296]
  PIN pma_tx[297]
    DIRECTION OUTPUT ;
    USE SIGNAL ;
    SHAPE ABUTMENT ;
    PORT
      LAYER M5 ;
      RECT 65.616 0.000 65.640 0.192 ;
    END
  END pma_tx[297]
  PIN pma_tx[298]
    DIRECTION OUTPUT ;
    USE SIGNAL ;
    SHAPE ABUTMENT ;
    PORT
      LAYER M5 ;
      RECT 65.856 0.000 65.880 0.192 ;
    END
  END pma_tx[298]
  PIN pma_tx[299]
    DIRECTION OUTPUT ;
    USE SIGNAL ;
    SHAPE ABUTMENT ;
    PORT
      LAYER M5 ;
      RECT 66.048 0.000 66.072 0.192 ;
    END
  END pma_tx[299]
  PIN pma_tx[300]
    DIRECTION OUTPUT ;
    USE SIGNAL ;
    SHAPE ABUTMENT ;
    PORT
      LAYER M5 ;
      RECT 66.240 0.000 66.264 0.192 ;
    END
  END pma_tx[300]
  PIN pma_tx[301]
    DIRECTION OUTPUT ;
    USE SIGNAL ;
    SHAPE ABUTMENT ;
    PORT
      LAYER M5 ;
      RECT 66.432 0.000 66.456 0.192 ;
    END
  END pma_tx[301]
  PIN pma_tx[302]
    DIRECTION OUTPUT ;
    USE SIGNAL ;
    SHAPE ABUTMENT ;
    PORT
      LAYER M5 ;
      RECT 66.672 0.000 66.696 0.192 ;
    END
  END pma_tx[302]
  PIN pma_tx[303]
    DIRECTION OUTPUT ;
    USE SIGNAL ;
    SHAPE ABUTMENT ;
    PORT
      LAYER M5 ;
      RECT 66.864 0.000 66.888 0.192 ;
    END
  END pma_tx[303]
  PIN pma_tx[304]
    DIRECTION OUTPUT ;
    USE SIGNAL ;
    SHAPE ABUTMENT ;
    PORT
      LAYER M5 ;
      RECT 67.056 0.000 67.080 0.192 ;
    END
  END pma_tx[304]
  PIN pma_tx[305]
    DIRECTION OUTPUT ;
    USE SIGNAL ;
    SHAPE ABUTMENT ;
    PORT
      LAYER M5 ;
      RECT 67.296 0.000 67.320 0.192 ;
    END
  END pma_tx[305]
  PIN pma_tx[306]
    DIRECTION OUTPUT ;
    USE SIGNAL ;
    SHAPE ABUTMENT ;
    PORT
      LAYER M5 ;
      RECT 67.488 0.000 67.512 0.192 ;
    END
  END pma_tx[306]
  PIN pma_tx[307]
    DIRECTION OUTPUT ;
    USE SIGNAL ;
    SHAPE ABUTMENT ;
    PORT
      LAYER M5 ;
      RECT 67.680 0.000 67.704 0.192 ;
    END
  END pma_tx[307]
  PIN pma_tx[308]
    DIRECTION OUTPUT ;
    USE SIGNAL ;
    SHAPE ABUTMENT ;
    PORT
      LAYER M5 ;
      RECT 67.872 0.000 67.896 0.192 ;
    END
  END pma_tx[308]
  PIN pma_tx[309]
    DIRECTION OUTPUT ;
    USE SIGNAL ;
    SHAPE ABUTMENT ;
    PORT
      LAYER M5 ;
      RECT 68.112 0.000 68.136 0.192 ;
    END
  END pma_tx[309]
  PIN pma_tx[310]
    DIRECTION OUTPUT ;
    USE SIGNAL ;
    SHAPE ABUTMENT ;
    PORT
      LAYER M5 ;
      RECT 68.304 0.000 68.328 0.192 ;
    END
  END pma_tx[310]
  PIN pma_tx[311]
    DIRECTION OUTPUT ;
    USE SIGNAL ;
    SHAPE ABUTMENT ;
    PORT
      LAYER M5 ;
      RECT 68.496 0.000 68.520 0.192 ;
    END
  END pma_tx[311]
  PIN pma_tx[312]
    DIRECTION OUTPUT ;
    USE SIGNAL ;
    SHAPE ABUTMENT ;
    PORT
      LAYER M5 ;
      RECT 68.736 0.000 68.760 0.192 ;
    END
  END pma_tx[312]
  PIN pma_tx[313]
    DIRECTION OUTPUT ;
    USE SIGNAL ;
    SHAPE ABUTMENT ;
    PORT
      LAYER M5 ;
      RECT 68.928 0.000 68.952 0.192 ;
    END
  END pma_tx[313]
  PIN pma_tx[314]
    DIRECTION OUTPUT ;
    USE SIGNAL ;
    SHAPE ABUTMENT ;
    PORT
      LAYER M5 ;
      RECT 69.120 0.000 69.144 0.192 ;
    END
  END pma_tx[314]
  PIN pma_tx[315]
    DIRECTION OUTPUT ;
    USE SIGNAL ;
    SHAPE ABUTMENT ;
    PORT
      LAYER M5 ;
      RECT 69.312 0.000 69.336 0.192 ;
    END
  END pma_tx[315]
  PIN pma_tx[316]
    DIRECTION OUTPUT ;
    USE SIGNAL ;
    SHAPE ABUTMENT ;
    PORT
      LAYER M5 ;
      RECT 69.552 0.000 69.576 0.192 ;
    END
  END pma_tx[316]
  PIN pma_tx[317]
    DIRECTION OUTPUT ;
    USE SIGNAL ;
    SHAPE ABUTMENT ;
    PORT
      LAYER M5 ;
      RECT 69.744 0.000 69.768 0.192 ;
    END
  END pma_tx[317]
  PIN pma_tx[318]
    DIRECTION OUTPUT ;
    USE SIGNAL ;
    SHAPE ABUTMENT ;
    PORT
      LAYER M5 ;
      RECT 69.936 0.000 69.960 0.192 ;
    END
  END pma_tx[318]
  PIN pma_tx[319]
    DIRECTION OUTPUT ;
    USE SIGNAL ;
    SHAPE ABUTMENT ;
    PORT
      LAYER M5 ;
      RECT 70.176 0.000 70.200 0.192 ;
    END
  END pma_tx[319]
  PIN pma_tx[320]
    DIRECTION OUTPUT ;
    USE SIGNAL ;
    SHAPE ABUTMENT ;
    PORT
      LAYER M5 ;
      RECT 70.368 0.000 70.392 0.192 ;
    END
  END pma_tx[320]
  PIN pma_tx[321]
    DIRECTION OUTPUT ;
    USE SIGNAL ;
    SHAPE ABUTMENT ;
    PORT
      LAYER M5 ;
      RECT 70.560 0.000 70.584 0.192 ;
    END
  END pma_tx[321]
  PIN pma_tx[322]
    DIRECTION OUTPUT ;
    USE SIGNAL ;
    SHAPE ABUTMENT ;
    PORT
      LAYER M5 ;
      RECT 70.752 0.000 70.776 0.192 ;
    END
  END pma_tx[322]
  PIN pma_tx[323]
    DIRECTION OUTPUT ;
    USE SIGNAL ;
    SHAPE ABUTMENT ;
    PORT
      LAYER M5 ;
      RECT 70.992 0.000 71.016 0.192 ;
    END
  END pma_tx[323]
  PIN pma_tx[324]
    DIRECTION OUTPUT ;
    USE SIGNAL ;
    SHAPE ABUTMENT ;
    PORT
      LAYER M5 ;
      RECT 71.184 0.000 71.208 0.192 ;
    END
  END pma_tx[324]
  PIN pma_tx[325]
    DIRECTION OUTPUT ;
    USE SIGNAL ;
    SHAPE ABUTMENT ;
    PORT
      LAYER M5 ;
      RECT 71.376 0.000 71.400 0.192 ;
    END
  END pma_tx[325]
  PIN pma_tx[326]
    DIRECTION OUTPUT ;
    USE SIGNAL ;
    SHAPE ABUTMENT ;
    PORT
      LAYER M5 ;
      RECT 71.616 0.000 71.640 0.192 ;
    END
  END pma_tx[326]
  PIN pma_tx[327]
    DIRECTION OUTPUT ;
    USE SIGNAL ;
    SHAPE ABUTMENT ;
    PORT
      LAYER M5 ;
      RECT 71.808 0.000 71.832 0.192 ;
    END
  END pma_tx[327]
  PIN pma_tx[328]
    DIRECTION OUTPUT ;
    USE SIGNAL ;
    SHAPE ABUTMENT ;
    PORT
      LAYER M5 ;
      RECT 72.000 0.000 72.024 0.192 ;
    END
  END pma_tx[328]
  PIN pma_tx[329]
    DIRECTION OUTPUT ;
    USE SIGNAL ;
    SHAPE ABUTMENT ;
    PORT
      LAYER M5 ;
      RECT 72.192 0.000 72.216 0.192 ;
    END
  END pma_tx[329]
  PIN pma_tx[330]
    DIRECTION OUTPUT ;
    USE SIGNAL ;
    SHAPE ABUTMENT ;
    PORT
      LAYER M5 ;
      RECT 72.432 0.000 72.456 0.192 ;
    END
  END pma_tx[330]
  PIN pma_tx[331]
    DIRECTION OUTPUT ;
    USE SIGNAL ;
    SHAPE ABUTMENT ;
    PORT
      LAYER M5 ;
      RECT 72.624 0.000 72.648 0.192 ;
    END
  END pma_tx[331]
  PIN pma_tx[332]
    DIRECTION OUTPUT ;
    USE SIGNAL ;
    SHAPE ABUTMENT ;
    PORT
      LAYER M5 ;
      RECT 72.816 0.000 72.840 0.192 ;
    END
  END pma_tx[332]
  PIN pma_tx[333]
    DIRECTION OUTPUT ;
    USE SIGNAL ;
    SHAPE ABUTMENT ;
    PORT
      LAYER M5 ;
      RECT 73.056 0.000 73.080 0.192 ;
    END
  END pma_tx[333]
  PIN pma_tx[334]
    DIRECTION OUTPUT ;
    USE SIGNAL ;
    SHAPE ABUTMENT ;
    PORT
      LAYER M5 ;
      RECT 73.248 0.000 73.272 0.192 ;
    END
  END pma_tx[334]
  PIN pma_tx[335]
    DIRECTION OUTPUT ;
    USE SIGNAL ;
    SHAPE ABUTMENT ;
    PORT
      LAYER M5 ;
      RECT 73.440 0.000 73.464 0.192 ;
    END
  END pma_tx[335]
  PIN pma_tx[336]
    DIRECTION OUTPUT ;
    USE SIGNAL ;
    SHAPE ABUTMENT ;
    PORT
      LAYER M5 ;
      RECT 73.632 0.000 73.656 0.192 ;
    END
  END pma_tx[336]
  PIN pma_tx[337]
    DIRECTION OUTPUT ;
    USE SIGNAL ;
    SHAPE ABUTMENT ;
    PORT
      LAYER M5 ;
      RECT 73.872 0.000 73.896 0.192 ;
    END
  END pma_tx[337]
  PIN pma_tx[338]
    DIRECTION OUTPUT ;
    USE SIGNAL ;
    SHAPE ABUTMENT ;
    PORT
      LAYER M5 ;
      RECT 74.064 0.000 74.088 0.192 ;
    END
  END pma_tx[338]
  PIN pma_tx[339]
    DIRECTION OUTPUT ;
    USE SIGNAL ;
    SHAPE ABUTMENT ;
    PORT
      LAYER M5 ;
      RECT 74.256 0.000 74.280 0.192 ;
    END
  END pma_tx[339]
  PIN pma_tx[340]
    DIRECTION OUTPUT ;
    USE SIGNAL ;
    SHAPE ABUTMENT ;
    PORT
      LAYER M5 ;
      RECT 74.496 0.000 74.520 0.192 ;
    END
  END pma_tx[340]
  PIN pma_tx[341]
    DIRECTION OUTPUT ;
    USE SIGNAL ;
    SHAPE ABUTMENT ;
    PORT
      LAYER M5 ;
      RECT 74.688 0.000 74.712 0.192 ;
    END
  END pma_tx[341]
  PIN pma_tx[342]
    DIRECTION OUTPUT ;
    USE SIGNAL ;
    SHAPE ABUTMENT ;
    PORT
      LAYER M5 ;
      RECT 74.880 0.000 74.904 0.192 ;
    END
  END pma_tx[342]
  PIN pma_tx[343]
    DIRECTION OUTPUT ;
    USE SIGNAL ;
    SHAPE ABUTMENT ;
    PORT
      LAYER M5 ;
      RECT 75.072 0.000 75.096 0.192 ;
    END
  END pma_tx[343]
  PIN pma_tx[344]
    DIRECTION OUTPUT ;
    USE SIGNAL ;
    SHAPE ABUTMENT ;
    PORT
      LAYER M5 ;
      RECT 75.312 0.000 75.336 0.192 ;
    END
  END pma_tx[344]
  PIN pma_tx[345]
    DIRECTION OUTPUT ;
    USE SIGNAL ;
    SHAPE ABUTMENT ;
    PORT
      LAYER M5 ;
      RECT 75.504 0.000 75.528 0.192 ;
    END
  END pma_tx[345]
  PIN pma_tx[346]
    DIRECTION OUTPUT ;
    USE SIGNAL ;
    SHAPE ABUTMENT ;
    PORT
      LAYER M5 ;
      RECT 75.696 0.000 75.720 0.192 ;
    END
  END pma_tx[346]
  PIN pma_tx[347]
    DIRECTION OUTPUT ;
    USE SIGNAL ;
    SHAPE ABUTMENT ;
    PORT
      LAYER M5 ;
      RECT 75.936 0.000 75.960 0.192 ;
    END
  END pma_tx[347]
  PIN pma_tx[348]
    DIRECTION OUTPUT ;
    USE SIGNAL ;
    SHAPE ABUTMENT ;
    PORT
      LAYER M5 ;
      RECT 76.128 0.000 76.152 0.192 ;
    END
  END pma_tx[348]
  PIN pma_tx[349]
    DIRECTION OUTPUT ;
    USE SIGNAL ;
    SHAPE ABUTMENT ;
    PORT
      LAYER M5 ;
      RECT 76.320 0.000 76.344 0.192 ;
    END
  END pma_tx[349]
  PIN pma_tx[350]
    DIRECTION OUTPUT ;
    USE SIGNAL ;
    SHAPE ABUTMENT ;
    PORT
      LAYER M5 ;
      RECT 76.560 0.000 76.584 0.192 ;
    END
  END pma_tx[350]
  PIN pma_tx[351]
    DIRECTION OUTPUT ;
    USE SIGNAL ;
    SHAPE ABUTMENT ;
    PORT
      LAYER M5 ;
      RECT 76.752 0.000 76.776 0.192 ;
    END
  END pma_tx[351]
  PIN pma_tx[352]
    DIRECTION OUTPUT ;
    USE SIGNAL ;
    SHAPE ABUTMENT ;
    PORT
      LAYER M5 ;
      RECT 76.944 0.000 76.968 0.192 ;
    END
  END pma_tx[352]
  PIN pma_tx[353]
    DIRECTION OUTPUT ;
    USE SIGNAL ;
    SHAPE ABUTMENT ;
    PORT
      LAYER M5 ;
      RECT 77.136 0.000 77.160 0.192 ;
    END
  END pma_tx[353]
  PIN pma_tx[354]
    DIRECTION OUTPUT ;
    USE SIGNAL ;
    SHAPE ABUTMENT ;
    PORT
      LAYER M5 ;
      RECT 77.376 0.000 77.400 0.192 ;
    END
  END pma_tx[354]
  PIN pma_tx[355]
    DIRECTION OUTPUT ;
    USE SIGNAL ;
    SHAPE ABUTMENT ;
    PORT
      LAYER M5 ;
      RECT 77.568 0.000 77.592 0.192 ;
    END
  END pma_tx[355]
  PIN pma_tx[356]
    DIRECTION OUTPUT ;
    USE SIGNAL ;
    SHAPE ABUTMENT ;
    PORT
      LAYER M5 ;
      RECT 77.760 0.000 77.784 0.192 ;
    END
  END pma_tx[356]
  PIN pma_tx[357]
    DIRECTION OUTPUT ;
    USE SIGNAL ;
    SHAPE ABUTMENT ;
    PORT
      LAYER M5 ;
      RECT 78.000 0.000 78.024 0.192 ;
    END
  END pma_tx[357]
  PIN pma_tx[358]
    DIRECTION OUTPUT ;
    USE SIGNAL ;
    SHAPE ABUTMENT ;
    PORT
      LAYER M5 ;
      RECT 78.192 0.000 78.216 0.192 ;
    END
  END pma_tx[358]
  PIN pma_tx[359]
    DIRECTION OUTPUT ;
    USE SIGNAL ;
    SHAPE ABUTMENT ;
    PORT
      LAYER M5 ;
      RECT 78.384 0.000 78.408 0.192 ;
    END
  END pma_tx[359]
  PIN pma_tx[360]
    DIRECTION OUTPUT ;
    USE SIGNAL ;
    SHAPE ABUTMENT ;
    PORT
      LAYER M5 ;
      RECT 78.576 0.000 78.600 0.192 ;
    END
  END pma_tx[360]
  PIN pma_tx[361]
    DIRECTION OUTPUT ;
    USE SIGNAL ;
    SHAPE ABUTMENT ;
    PORT
      LAYER M5 ;
      RECT 78.816 0.000 78.840 0.192 ;
    END
  END pma_tx[361]
  PIN pma_tx[362]
    DIRECTION OUTPUT ;
    USE SIGNAL ;
    SHAPE ABUTMENT ;
    PORT
      LAYER M5 ;
      RECT 79.008 0.000 79.032 0.192 ;
    END
  END pma_tx[362]
  PIN pma_tx[363]
    DIRECTION OUTPUT ;
    USE SIGNAL ;
    SHAPE ABUTMENT ;
    PORT
      LAYER M5 ;
      RECT 79.200 0.000 79.224 0.192 ;
    END
  END pma_tx[363]
  PIN pma_tx[364]
    DIRECTION OUTPUT ;
    USE SIGNAL ;
    SHAPE ABUTMENT ;
    PORT
      LAYER M5 ;
      RECT 79.440 0.000 79.464 0.192 ;
    END
  END pma_tx[364]
  PIN pma_tx[365]
    DIRECTION OUTPUT ;
    USE SIGNAL ;
    SHAPE ABUTMENT ;
    PORT
      LAYER M5 ;
      RECT 79.632 0.000 79.656 0.192 ;
    END
  END pma_tx[365]
  PIN pma_tx[366]
    DIRECTION OUTPUT ;
    USE SIGNAL ;
    SHAPE ABUTMENT ;
    PORT
      LAYER M5 ;
      RECT 79.824 0.000 79.848 0.192 ;
    END
  END pma_tx[366]
  PIN pma_tx[367]
    DIRECTION OUTPUT ;
    USE SIGNAL ;
    SHAPE ABUTMENT ;
    PORT
      LAYER M5 ;
      RECT 80.016 0.000 80.040 0.192 ;
    END
  END pma_tx[367]
  PIN pma_tx[368]
    DIRECTION OUTPUT ;
    USE SIGNAL ;
    SHAPE ABUTMENT ;
    PORT
      LAYER M5 ;
      RECT 80.256 0.000 80.280 0.192 ;
    END
  END pma_tx[368]
  PIN pma_tx[369]
    DIRECTION OUTPUT ;
    USE SIGNAL ;
    SHAPE ABUTMENT ;
    PORT
      LAYER M5 ;
      RECT 80.448 0.000 80.472 0.192 ;
    END
  END pma_tx[369]
  PIN pma_tx[370]
    DIRECTION OUTPUT ;
    USE SIGNAL ;
    SHAPE ABUTMENT ;
    PORT
      LAYER M5 ;
      RECT 80.640 0.000 80.664 0.192 ;
    END
  END pma_tx[370]
  PIN pma_tx[371]
    DIRECTION OUTPUT ;
    USE SIGNAL ;
    SHAPE ABUTMENT ;
    PORT
      LAYER M5 ;
      RECT 80.880 0.000 80.904 0.192 ;
    END
  END pma_tx[371]
  PIN pma_tx[372]
    DIRECTION OUTPUT ;
    USE SIGNAL ;
    SHAPE ABUTMENT ;
    PORT
      LAYER M5 ;
      RECT 81.072 0.000 81.096 0.192 ;
    END
  END pma_tx[372]
  PIN pma_tx[373]
    DIRECTION OUTPUT ;
    USE SIGNAL ;
    SHAPE ABUTMENT ;
    PORT
      LAYER M5 ;
      RECT 81.264 0.000 81.288 0.192 ;
    END
  END pma_tx[373]
  PIN pma_tx[374]
    DIRECTION OUTPUT ;
    USE SIGNAL ;
    SHAPE ABUTMENT ;
    PORT
      LAYER M5 ;
      RECT 81.456 0.000 81.480 0.192 ;
    END
  END pma_tx[374]
  PIN pma_tx[375]
    DIRECTION OUTPUT ;
    USE SIGNAL ;
    SHAPE ABUTMENT ;
    PORT
      LAYER M5 ;
      RECT 81.696 0.000 81.720 0.192 ;
    END
  END pma_tx[375]
  PIN pma_tx[376]
    DIRECTION OUTPUT ;
    USE SIGNAL ;
    SHAPE ABUTMENT ;
    PORT
      LAYER M5 ;
      RECT 81.888 0.000 81.912 0.192 ;
    END
  END pma_tx[376]
  PIN pma_tx[377]
    DIRECTION OUTPUT ;
    USE SIGNAL ;
    SHAPE ABUTMENT ;
    PORT
      LAYER M5 ;
      RECT 82.080 0.000 82.104 0.192 ;
    END
  END pma_tx[377]
  PIN pma_tx[378]
    DIRECTION OUTPUT ;
    USE SIGNAL ;
    SHAPE ABUTMENT ;
    PORT
      LAYER M5 ;
      RECT 82.320 0.000 82.344 0.192 ;
    END
  END pma_tx[378]
  PIN pma_tx[379]
    DIRECTION OUTPUT ;
    USE SIGNAL ;
    SHAPE ABUTMENT ;
    PORT
      LAYER M5 ;
      RECT 82.512 0.000 82.536 0.192 ;
    END
  END pma_tx[379]
  PIN pma_tx[380]
    DIRECTION OUTPUT ;
    USE SIGNAL ;
    SHAPE ABUTMENT ;
    PORT
      LAYER M5 ;
      RECT 82.704 0.000 82.728 0.192 ;
    END
  END pma_tx[380]
  PIN pma_tx[381]
    DIRECTION OUTPUT ;
    USE SIGNAL ;
    SHAPE ABUTMENT ;
    PORT
      LAYER M5 ;
      RECT 82.896 0.000 82.920 0.192 ;
    END
  END pma_tx[381]
  PIN pma_tx[382]
    DIRECTION OUTPUT ;
    USE SIGNAL ;
    SHAPE ABUTMENT ;
    PORT
      LAYER M5 ;
      RECT 83.136 0.000 83.160 0.192 ;
    END
  END pma_tx[382]
  PIN pma_tx[383]
    DIRECTION OUTPUT ;
    USE SIGNAL ;
    SHAPE ABUTMENT ;
    PORT
      LAYER M5 ;
      RECT 83.328 0.000 83.352 0.192 ;
    END
  END pma_tx[383]
  PIN pma_tx[384]
    DIRECTION OUTPUT ;
    USE SIGNAL ;
    SHAPE ABUTMENT ;
    PORT
      LAYER M5 ;
      RECT 83.520 0.000 83.544 0.192 ;
    END
  END pma_tx[384]
  PIN pma_tx[385]
    DIRECTION OUTPUT ;
    USE SIGNAL ;
    SHAPE ABUTMENT ;
    PORT
      LAYER M5 ;
      RECT 83.760 0.000 83.784 0.192 ;
    END
  END pma_tx[385]
  PIN pma_tx[386]
    DIRECTION OUTPUT ;
    USE SIGNAL ;
    SHAPE ABUTMENT ;
    PORT
      LAYER M5 ;
      RECT 83.952 0.000 83.976 0.192 ;
    END
  END pma_tx[386]
  PIN pma_tx[387]
    DIRECTION OUTPUT ;
    USE SIGNAL ;
    SHAPE ABUTMENT ;
    PORT
      LAYER M5 ;
      RECT 84.144 0.000 84.168 0.192 ;
    END
  END pma_tx[387]
  PIN pma_tx[388]
    DIRECTION OUTPUT ;
    USE SIGNAL ;
    SHAPE ABUTMENT ;
    PORT
      LAYER M5 ;
      RECT 84.336 0.000 84.360 0.192 ;
    END
  END pma_tx[388]
  PIN pma_tx[389]
    DIRECTION OUTPUT ;
    USE SIGNAL ;
    SHAPE ABUTMENT ;
    PORT
      LAYER M5 ;
      RECT 84.576 0.000 84.600 0.192 ;
    END
  END pma_tx[389]
  PIN pma_tx[390]
    DIRECTION OUTPUT ;
    USE SIGNAL ;
    SHAPE ABUTMENT ;
    PORT
      LAYER M5 ;
      RECT 84.768 0.000 84.792 0.192 ;
    END
  END pma_tx[390]
  PIN pma_tx[391]
    DIRECTION OUTPUT ;
    USE SIGNAL ;
    SHAPE ABUTMENT ;
    PORT
      LAYER M5 ;
      RECT 84.960 0.000 84.984 0.192 ;
    END
  END pma_tx[391]
  PIN pma_tx[392]
    DIRECTION OUTPUT ;
    USE SIGNAL ;
    SHAPE ABUTMENT ;
    PORT
      LAYER M5 ;
      RECT 85.200 0.000 85.224 0.192 ;
    END
  END pma_tx[392]
  PIN pma_tx[393]
    DIRECTION OUTPUT ;
    USE SIGNAL ;
    SHAPE ABUTMENT ;
    PORT
      LAYER M5 ;
      RECT 85.392 0.000 85.416 0.192 ;
    END
  END pma_tx[393]
  PIN pma_tx[394]
    DIRECTION OUTPUT ;
    USE SIGNAL ;
    SHAPE ABUTMENT ;
    PORT
      LAYER M5 ;
      RECT 85.584 0.000 85.608 0.192 ;
    END
  END pma_tx[394]
  PIN pma_tx[395]
    DIRECTION OUTPUT ;
    USE SIGNAL ;
    SHAPE ABUTMENT ;
    PORT
      LAYER M5 ;
      RECT 85.776 0.000 85.800 0.192 ;
    END
  END pma_tx[395]
  PIN pma_tx[396]
    DIRECTION OUTPUT ;
    USE SIGNAL ;
    SHAPE ABUTMENT ;
    PORT
      LAYER M5 ;
      RECT 86.016 0.000 86.040 0.192 ;
    END
  END pma_tx[396]
  PIN pma_tx[397]
    DIRECTION OUTPUT ;
    USE SIGNAL ;
    SHAPE ABUTMENT ;
    PORT
      LAYER M5 ;
      RECT 86.208 0.000 86.232 0.192 ;
    END
  END pma_tx[397]
  PIN pma_tx[398]
    DIRECTION OUTPUT ;
    USE SIGNAL ;
    SHAPE ABUTMENT ;
    PORT
      LAYER M5 ;
      RECT 86.400 0.000 86.424 0.192 ;
    END
  END pma_tx[398]
  PIN pma_tx[399]
    DIRECTION OUTPUT ;
    USE SIGNAL ;
    SHAPE ABUTMENT ;
    PORT
      LAYER M5 ;
      RECT 86.640 0.000 86.664 0.192 ;
    END
  END pma_tx[399]
  PIN pma_tx[400]
    DIRECTION OUTPUT ;
    USE SIGNAL ;
    SHAPE ABUTMENT ;
    PORT
      LAYER M5 ;
      RECT 86.832 0.000 86.856 0.192 ;
    END
  END pma_tx[400]
  PIN pma_tx[401]
    DIRECTION OUTPUT ;
    USE SIGNAL ;
    SHAPE ABUTMENT ;
    PORT
      LAYER M5 ;
      RECT 87.024 0.000 87.048 0.192 ;
    END
  END pma_tx[401]
  PIN pma_tx[402]
    DIRECTION OUTPUT ;
    USE SIGNAL ;
    SHAPE ABUTMENT ;
    PORT
      LAYER M5 ;
      RECT 87.264 0.000 87.288 0.192 ;
    END
  END pma_tx[402]
  PIN pma_tx[403]
    DIRECTION OUTPUT ;
    USE SIGNAL ;
    SHAPE ABUTMENT ;
    PORT
      LAYER M5 ;
      RECT 87.456 0.000 87.480 0.192 ;
    END
  END pma_tx[403]
  PIN pma_tx[404]
    DIRECTION OUTPUT ;
    USE SIGNAL ;
    SHAPE ABUTMENT ;
    PORT
      LAYER M5 ;
      RECT 87.648 0.000 87.672 0.192 ;
    END
  END pma_tx[404]
  PIN pma_tx[405]
    DIRECTION OUTPUT ;
    USE SIGNAL ;
    SHAPE ABUTMENT ;
    PORT
      LAYER M5 ;
      RECT 87.840 0.000 87.864 0.192 ;
    END
  END pma_tx[405]
  PIN pma_tx[406]
    DIRECTION OUTPUT ;
    USE SIGNAL ;
    SHAPE ABUTMENT ;
    PORT
      LAYER M5 ;
      RECT 88.080 0.000 88.104 0.192 ;
    END
  END pma_tx[406]
  PIN pma_tx[407]
    DIRECTION OUTPUT ;
    USE SIGNAL ;
    SHAPE ABUTMENT ;
    PORT
      LAYER M5 ;
      RECT 88.272 0.000 88.296 0.192 ;
    END
  END pma_tx[407]
  PIN pma_tx[408]
    DIRECTION OUTPUT ;
    USE SIGNAL ;
    SHAPE ABUTMENT ;
    PORT
      LAYER M5 ;
      RECT 88.464 0.000 88.488 0.192 ;
    END
  END pma_tx[408]
  PIN pma_tx[409]
    DIRECTION OUTPUT ;
    USE SIGNAL ;
    SHAPE ABUTMENT ;
    PORT
      LAYER M5 ;
      RECT 88.704 0.000 88.728 0.192 ;
    END
  END pma_tx[409]
  PIN pma_tx[410]
    DIRECTION OUTPUT ;
    USE SIGNAL ;
    SHAPE ABUTMENT ;
    PORT
      LAYER M5 ;
      RECT 88.896 0.000 88.920 0.192 ;
    END
  END pma_tx[410]
  PIN pma_tx[411]
    DIRECTION OUTPUT ;
    USE SIGNAL ;
    SHAPE ABUTMENT ;
    PORT
      LAYER M5 ;
      RECT 89.088 0.000 89.112 0.192 ;
    END
  END pma_tx[411]
  PIN pma_tx[412]
    DIRECTION OUTPUT ;
    USE SIGNAL ;
    SHAPE ABUTMENT ;
    PORT
      LAYER M5 ;
      RECT 89.280 0.000 89.304 0.192 ;
    END
  END pma_tx[412]
  PIN pma_tx[413]
    DIRECTION OUTPUT ;
    USE SIGNAL ;
    SHAPE ABUTMENT ;
    PORT
      LAYER M5 ;
      RECT 89.520 0.000 89.544 0.192 ;
    END
  END pma_tx[413]
  PIN pma_tx[414]
    DIRECTION OUTPUT ;
    USE SIGNAL ;
    SHAPE ABUTMENT ;
    PORT
      LAYER M5 ;
      RECT 89.712 0.000 89.736 0.192 ;
    END
  END pma_tx[414]
  PIN pma_tx[415]
    DIRECTION OUTPUT ;
    USE SIGNAL ;
    SHAPE ABUTMENT ;
    PORT
      LAYER M5 ;
      RECT 89.904 0.000 89.928 0.192 ;
    END
  END pma_tx[415]
  PIN pma_tx[416]
    DIRECTION OUTPUT ;
    USE SIGNAL ;
    SHAPE ABUTMENT ;
    PORT
      LAYER M5 ;
      RECT 90.144 0.000 90.168 0.192 ;
    END
  END pma_tx[416]
  PIN pma_tx[417]
    DIRECTION OUTPUT ;
    USE SIGNAL ;
    SHAPE ABUTMENT ;
    PORT
      LAYER M5 ;
      RECT 90.336 0.000 90.360 0.192 ;
    END
  END pma_tx[417]
  PIN pma_tx[418]
    DIRECTION OUTPUT ;
    USE SIGNAL ;
    SHAPE ABUTMENT ;
    PORT
      LAYER M5 ;
      RECT 90.528 0.000 90.552 0.192 ;
    END
  END pma_tx[418]
  PIN pma_tx[419]
    DIRECTION OUTPUT ;
    USE SIGNAL ;
    SHAPE ABUTMENT ;
    PORT
      LAYER M5 ;
      RECT 90.720 0.000 90.744 0.192 ;
    END
  END pma_tx[419]
  PIN pma_tx[420]
    DIRECTION OUTPUT ;
    USE SIGNAL ;
    SHAPE ABUTMENT ;
    PORT
      LAYER M5 ;
      RECT 90.960 0.000 90.984 0.192 ;
    END
  END pma_tx[420]
  PIN pma_tx[421]
    DIRECTION OUTPUT ;
    USE SIGNAL ;
    SHAPE ABUTMENT ;
    PORT
      LAYER M5 ;
      RECT 91.152 0.000 91.176 0.192 ;
    END
  END pma_tx[421]
  PIN pma_tx[422]
    DIRECTION OUTPUT ;
    USE SIGNAL ;
    SHAPE ABUTMENT ;
    PORT
      LAYER M5 ;
      RECT 91.344 0.000 91.368 0.192 ;
    END
  END pma_tx[422]
  PIN pma_tx[423]
    DIRECTION OUTPUT ;
    USE SIGNAL ;
    SHAPE ABUTMENT ;
    PORT
      LAYER M5 ;
      RECT 91.584 0.000 91.608 0.192 ;
    END
  END pma_tx[423]
  PIN pma_tx[424]
    DIRECTION OUTPUT ;
    USE SIGNAL ;
    SHAPE ABUTMENT ;
    PORT
      LAYER M5 ;
      RECT 91.776 0.000 91.800 0.192 ;
    END
  END pma_tx[424]
  PIN pma_tx[425]
    DIRECTION OUTPUT ;
    USE SIGNAL ;
    SHAPE ABUTMENT ;
    PORT
      LAYER M5 ;
      RECT 91.968 0.000 91.992 0.192 ;
    END
  END pma_tx[425]
  PIN pma_tx[426]
    DIRECTION OUTPUT ;
    USE SIGNAL ;
    SHAPE ABUTMENT ;
    PORT
      LAYER M5 ;
      RECT 92.160 0.000 92.184 0.192 ;
    END
  END pma_tx[426]
  PIN pma_tx[427]
    DIRECTION OUTPUT ;
    USE SIGNAL ;
    SHAPE ABUTMENT ;
    PORT
      LAYER M5 ;
      RECT 92.400 0.000 92.424 0.192 ;
    END
  END pma_tx[427]
  PIN pma_tx[428]
    DIRECTION OUTPUT ;
    USE SIGNAL ;
    SHAPE ABUTMENT ;
    PORT
      LAYER M5 ;
      RECT 92.592 0.000 92.616 0.192 ;
    END
  END pma_tx[428]
  PIN pma_tx[429]
    DIRECTION OUTPUT ;
    USE SIGNAL ;
    SHAPE ABUTMENT ;
    PORT
      LAYER M5 ;
      RECT 92.784 0.000 92.808 0.192 ;
    END
  END pma_tx[429]
  PIN pma_tx[430]
    DIRECTION OUTPUT ;
    USE SIGNAL ;
    SHAPE ABUTMENT ;
    PORT
      LAYER M5 ;
      RECT 93.024 0.000 93.048 0.192 ;
    END
  END pma_tx[430]
  PIN pma_tx[431]
    DIRECTION OUTPUT ;
    USE SIGNAL ;
    SHAPE ABUTMENT ;
    PORT
      LAYER M5 ;
      RECT 93.216 0.000 93.240 0.192 ;
    END
  END pma_tx[431]
  PIN pma_tx[432]
    DIRECTION OUTPUT ;
    USE SIGNAL ;
    SHAPE ABUTMENT ;
    PORT
      LAYER M5 ;
      RECT 93.408 0.000 93.432 0.192 ;
    END
  END pma_tx[432]
  PIN pma_tx[433]
    DIRECTION OUTPUT ;
    USE SIGNAL ;
    SHAPE ABUTMENT ;
    PORT
      LAYER M5 ;
      RECT 93.600 0.000 93.624 0.192 ;
    END
  END pma_tx[433]
  PIN pma_tx[434]
    DIRECTION OUTPUT ;
    USE SIGNAL ;
    SHAPE ABUTMENT ;
    PORT
      LAYER M5 ;
      RECT 93.840 0.000 93.864 0.192 ;
    END
  END pma_tx[434]
  PIN pma_tx[435]
    DIRECTION OUTPUT ;
    USE SIGNAL ;
    SHAPE ABUTMENT ;
    PORT
      LAYER M5 ;
      RECT 94.032 0.000 94.056 0.192 ;
    END
  END pma_tx[435]
  PIN pma_tx[436]
    DIRECTION OUTPUT ;
    USE SIGNAL ;
    SHAPE ABUTMENT ;
    PORT
      LAYER M5 ;
      RECT 94.224 0.000 94.248 0.192 ;
    END
  END pma_tx[436]
  PIN pma_tx[437]
    DIRECTION OUTPUT ;
    USE SIGNAL ;
    SHAPE ABUTMENT ;
    PORT
      LAYER M5 ;
      RECT 94.464 0.000 94.488 0.192 ;
    END
  END pma_tx[437]
  PIN pma_tx[438]
    DIRECTION OUTPUT ;
    USE SIGNAL ;
    SHAPE ABUTMENT ;
    PORT
      LAYER M5 ;
      RECT 94.656 0.000 94.680 0.192 ;
    END
  END pma_tx[438]
  PIN pma_tx[439]
    DIRECTION OUTPUT ;
    USE SIGNAL ;
    SHAPE ABUTMENT ;
    PORT
      LAYER M5 ;
      RECT 94.848 0.000 94.872 0.192 ;
    END
  END pma_tx[439]
  PIN pma_tx[440]
    DIRECTION OUTPUT ;
    USE SIGNAL ;
    SHAPE ABUTMENT ;
    PORT
      LAYER M5 ;
      RECT 95.040 0.000 95.064 0.192 ;
    END
  END pma_tx[440]
  PIN pma_tx[441]
    DIRECTION OUTPUT ;
    USE SIGNAL ;
    SHAPE ABUTMENT ;
    PORT
      LAYER M5 ;
      RECT 95.280 0.000 95.304 0.192 ;
    END
  END pma_tx[441]
  PIN pma_tx[442]
    DIRECTION OUTPUT ;
    USE SIGNAL ;
    SHAPE ABUTMENT ;
    PORT
      LAYER M5 ;
      RECT 95.472 0.000 95.496 0.192 ;
    END
  END pma_tx[442]
  PIN pma_tx[443]
    DIRECTION OUTPUT ;
    USE SIGNAL ;
    SHAPE ABUTMENT ;
    PORT
      LAYER M5 ;
      RECT 95.664 0.000 95.688 0.192 ;
    END
  END pma_tx[443]
  PIN pma_tx[444]
    DIRECTION OUTPUT ;
    USE SIGNAL ;
    SHAPE ABUTMENT ;
    PORT
      LAYER M5 ;
      RECT 95.904 0.000 95.928 0.192 ;
    END
  END pma_tx[444]
  PIN pma_tx[445]
    DIRECTION OUTPUT ;
    USE SIGNAL ;
    SHAPE ABUTMENT ;
    PORT
      LAYER M5 ;
      RECT 96.096 0.000 96.120 0.192 ;
    END
  END pma_tx[445]
  PIN pma_tx[446]
    DIRECTION OUTPUT ;
    USE SIGNAL ;
    SHAPE ABUTMENT ;
    PORT
      LAYER M5 ;
      RECT 96.288 0.000 96.312 0.192 ;
    END
  END pma_tx[446]
  PIN pma_tx[447]
    DIRECTION OUTPUT ;
    USE SIGNAL ;
    SHAPE ABUTMENT ;
    PORT
      LAYER M5 ;
      RECT 96.528 0.000 96.552 0.192 ;
    END
  END pma_tx[447]
  PIN pma_tx[448]
    DIRECTION OUTPUT ;
    USE SIGNAL ;
    SHAPE ABUTMENT ;
    PORT
      LAYER M5 ;
      RECT 96.720 0.000 96.744 0.192 ;
    END
  END pma_tx[448]
  PIN pma_tx[449]
    DIRECTION OUTPUT ;
    USE SIGNAL ;
    SHAPE ABUTMENT ;
    PORT
      LAYER M5 ;
      RECT 96.912 0.000 96.936 0.192 ;
    END
  END pma_tx[449]
  PIN pma_tx[450]
    DIRECTION OUTPUT ;
    USE SIGNAL ;
    SHAPE ABUTMENT ;
    PORT
      LAYER M5 ;
      RECT 97.104 0.000 97.128 0.192 ;
    END
  END pma_tx[450]
  PIN pma_tx[451]
    DIRECTION OUTPUT ;
    USE SIGNAL ;
    SHAPE ABUTMENT ;
    PORT
      LAYER M5 ;
      RECT 97.344 0.000 97.368 0.192 ;
    END
  END pma_tx[451]
  PIN pma_tx[452]
    DIRECTION OUTPUT ;
    USE SIGNAL ;
    SHAPE ABUTMENT ;
    PORT
      LAYER M5 ;
      RECT 97.536 0.000 97.560 0.192 ;
    END
  END pma_tx[452]
  PIN pma_tx[453]
    DIRECTION OUTPUT ;
    USE SIGNAL ;
    SHAPE ABUTMENT ;
    PORT
      LAYER M5 ;
      RECT 97.728 0.000 97.752 0.192 ;
    END
  END pma_tx[453]
  PIN pma_tx[454]
    DIRECTION OUTPUT ;
    USE SIGNAL ;
    SHAPE ABUTMENT ;
    PORT
      LAYER M5 ;
      RECT 97.968 0.000 97.992 0.192 ;
    END
  END pma_tx[454]
  PIN pma_tx[455]
    DIRECTION OUTPUT ;
    USE SIGNAL ;
    SHAPE ABUTMENT ;
    PORT
      LAYER M5 ;
      RECT 98.160 0.000 98.184 0.192 ;
    END
  END pma_tx[455]
  PIN pma_tx[456]
    DIRECTION OUTPUT ;
    USE SIGNAL ;
    SHAPE ABUTMENT ;
    PORT
      LAYER M5 ;
      RECT 98.352 0.000 98.376 0.192 ;
    END
  END pma_tx[456]
  PIN pma_tx[457]
    DIRECTION OUTPUT ;
    USE SIGNAL ;
    SHAPE ABUTMENT ;
    PORT
      LAYER M5 ;
      RECT 98.544 0.000 98.568 0.192 ;
    END
  END pma_tx[457]
  PIN pma_tx[458]
    DIRECTION OUTPUT ;
    USE SIGNAL ;
    SHAPE ABUTMENT ;
    PORT
      LAYER M5 ;
      RECT 98.784 0.000 98.808 0.192 ;
    END
  END pma_tx[458]
  PIN pma_tx[459]
    DIRECTION OUTPUT ;
    USE SIGNAL ;
    SHAPE ABUTMENT ;
    PORT
      LAYER M5 ;
      RECT 98.976 0.000 99.000 0.192 ;
    END
  END pma_tx[459]
  PIN pma_tx[460]
    DIRECTION OUTPUT ;
    USE SIGNAL ;
    SHAPE ABUTMENT ;
    PORT
      LAYER M5 ;
      RECT 99.168 0.000 99.192 0.192 ;
    END
  END pma_tx[460]
  PIN pma_tx[461]
    DIRECTION OUTPUT ;
    USE SIGNAL ;
    SHAPE ABUTMENT ;
    PORT
      LAYER M5 ;
      RECT 99.408 0.000 99.432 0.192 ;
    END
  END pma_tx[461]
  PIN pma_tx[462]
    DIRECTION OUTPUT ;
    USE SIGNAL ;
    SHAPE ABUTMENT ;
    PORT
      LAYER M5 ;
      RECT 99.600 0.000 99.624 0.192 ;
    END
  END pma_tx[462]
  PIN pma_tx[463]
    DIRECTION OUTPUT ;
    USE SIGNAL ;
    SHAPE ABUTMENT ;
    PORT
      LAYER M5 ;
      RECT 99.792 0.000 99.816 0.192 ;
    END
  END pma_tx[463]
  PIN pma_tx[464]
    DIRECTION OUTPUT ;
    USE SIGNAL ;
    SHAPE ABUTMENT ;
    PORT
      LAYER M5 ;
      RECT 99.984 0.000 100.008 0.192 ;
    END
  END pma_tx[464]
  PIN pma_tx[465]
    DIRECTION OUTPUT ;
    USE SIGNAL ;
    SHAPE ABUTMENT ;
    PORT
      LAYER M5 ;
      RECT 100.224 0.000 100.248 0.192 ;
    END
  END pma_tx[465]
  PIN pma_tx[466]
    DIRECTION OUTPUT ;
    USE SIGNAL ;
    SHAPE ABUTMENT ;
    PORT
      LAYER M5 ;
      RECT 100.416 0.000 100.440 0.192 ;
    END
  END pma_tx[466]
  PIN pma_tx[467]
    DIRECTION OUTPUT ;
    USE SIGNAL ;
    SHAPE ABUTMENT ;
    PORT
      LAYER M5 ;
      RECT 100.608 0.000 100.632 0.192 ;
    END
  END pma_tx[467]
  PIN pma_tx[468]
    DIRECTION OUTPUT ;
    USE SIGNAL ;
    SHAPE ABUTMENT ;
    PORT
      LAYER M5 ;
      RECT 100.848 0.000 100.872 0.192 ;
    END
  END pma_tx[468]
  PIN pma_tx[469]
    DIRECTION OUTPUT ;
    USE SIGNAL ;
    SHAPE ABUTMENT ;
    PORT
      LAYER M5 ;
      RECT 101.040 0.000 101.064 0.192 ;
    END
  END pma_tx[469]
  PIN pma_tx[470]
    DIRECTION OUTPUT ;
    USE SIGNAL ;
    SHAPE ABUTMENT ;
    PORT
      LAYER M5 ;
      RECT 101.232 0.000 101.256 0.192 ;
    END
  END pma_tx[470]
  PIN pma_tx[471]
    DIRECTION OUTPUT ;
    USE SIGNAL ;
    SHAPE ABUTMENT ;
    PORT
      LAYER M5 ;
      RECT 101.424 0.000 101.448 0.192 ;
    END
  END pma_tx[471]
  PIN pma_tx[472]
    DIRECTION OUTPUT ;
    USE SIGNAL ;
    SHAPE ABUTMENT ;
    PORT
      LAYER M5 ;
      RECT 101.664 0.000 101.688 0.192 ;
    END
  END pma_tx[472]
  PIN pma_tx[473]
    DIRECTION OUTPUT ;
    USE SIGNAL ;
    SHAPE ABUTMENT ;
    PORT
      LAYER M5 ;
      RECT 101.856 0.000 101.880 0.192 ;
    END
  END pma_tx[473]
  PIN pma_tx[474]
    DIRECTION OUTPUT ;
    USE SIGNAL ;
    SHAPE ABUTMENT ;
    PORT
      LAYER M5 ;
      RECT 102.048 0.000 102.072 0.192 ;
    END
  END pma_tx[474]
  PIN pma_tx[475]
    DIRECTION OUTPUT ;
    USE SIGNAL ;
    SHAPE ABUTMENT ;
    PORT
      LAYER M5 ;
      RECT 102.288 0.000 102.312 0.192 ;
    END
  END pma_tx[475]
  PIN pma_tx[476]
    DIRECTION OUTPUT ;
    USE SIGNAL ;
    SHAPE ABUTMENT ;
    PORT
      LAYER M5 ;
      RECT 102.480 0.000 102.504 0.192 ;
    END
  END pma_tx[476]
  PIN pma_tx[477]
    DIRECTION OUTPUT ;
    USE SIGNAL ;
    SHAPE ABUTMENT ;
    PORT
      LAYER M5 ;
      RECT 102.672 0.000 102.696 0.192 ;
    END
  END pma_tx[477]
  PIN pma_tx[478]
    DIRECTION OUTPUT ;
    USE SIGNAL ;
    SHAPE ABUTMENT ;
    PORT
      LAYER M5 ;
      RECT 102.864 0.000 102.888 0.192 ;
    END
  END pma_tx[478]
  PIN pma_tx[479]
    DIRECTION OUTPUT ;
    USE SIGNAL ;
    SHAPE ABUTMENT ;
    PORT
      LAYER M5 ;
      RECT 103.104 0.000 103.128 0.192 ;
    END
  END pma_tx[479]
  PIN pma_tx[480]
    DIRECTION OUTPUT ;
    USE SIGNAL ;
    SHAPE ABUTMENT ;
    PORT
      LAYER M5 ;
      RECT 103.296 0.000 103.320 0.192 ;
    END
  END pma_tx[480]
  PIN pma_tx[481]
    DIRECTION OUTPUT ;
    USE SIGNAL ;
    SHAPE ABUTMENT ;
    PORT
      LAYER M5 ;
      RECT 103.488 0.000 103.512 0.192 ;
    END
  END pma_tx[481]
  PIN pma_tx[482]
    DIRECTION OUTPUT ;
    USE SIGNAL ;
    SHAPE ABUTMENT ;
    PORT
      LAYER M5 ;
      RECT 103.728 0.000 103.752 0.192 ;
    END
  END pma_tx[482]
  PIN pma_tx[483]
    DIRECTION OUTPUT ;
    USE SIGNAL ;
    SHAPE ABUTMENT ;
    PORT
      LAYER M5 ;
      RECT 103.920 0.000 103.944 0.192 ;
    END
  END pma_tx[483]
  PIN pma_tx[484]
    DIRECTION OUTPUT ;
    USE SIGNAL ;
    SHAPE ABUTMENT ;
    PORT
      LAYER M5 ;
      RECT 104.112 0.000 104.136 0.192 ;
    END
  END pma_tx[484]
  PIN pma_tx[485]
    DIRECTION OUTPUT ;
    USE SIGNAL ;
    SHAPE ABUTMENT ;
    PORT
      LAYER M5 ;
      RECT 104.304 0.000 104.328 0.192 ;
    END
  END pma_tx[485]
  PIN pma_tx[486]
    DIRECTION OUTPUT ;
    USE SIGNAL ;
    SHAPE ABUTMENT ;
    PORT
      LAYER M5 ;
      RECT 104.544 0.000 104.568 0.192 ;
    END
  END pma_tx[486]
  PIN pma_tx[487]
    DIRECTION OUTPUT ;
    USE SIGNAL ;
    SHAPE ABUTMENT ;
    PORT
      LAYER M5 ;
      RECT 104.736 0.000 104.760 0.192 ;
    END
  END pma_tx[487]
  PIN pma_tx[488]
    DIRECTION OUTPUT ;
    USE SIGNAL ;
    SHAPE ABUTMENT ;
    PORT
      LAYER M5 ;
      RECT 104.928 0.000 104.952 0.192 ;
    END
  END pma_tx[488]
  PIN pma_tx[489]
    DIRECTION OUTPUT ;
    USE SIGNAL ;
    SHAPE ABUTMENT ;
    PORT
      LAYER M5 ;
      RECT 105.168 0.000 105.192 0.192 ;
    END
  END pma_tx[489]
  PIN pma_tx[490]
    DIRECTION OUTPUT ;
    USE SIGNAL ;
    SHAPE ABUTMENT ;
    PORT
      LAYER M5 ;
      RECT 105.360 0.000 105.384 0.192 ;
    END
  END pma_tx[490]
  PIN pma_tx[491]
    DIRECTION OUTPUT ;
    USE SIGNAL ;
    SHAPE ABUTMENT ;
    PORT
      LAYER M5 ;
      RECT 105.552 0.000 105.576 0.192 ;
    END
  END pma_tx[491]
  PIN pma_tx[492]
    DIRECTION OUTPUT ;
    USE SIGNAL ;
    SHAPE ABUTMENT ;
    PORT
      LAYER M5 ;
      RECT 105.744 0.000 105.768 0.192 ;
    END
  END pma_tx[492]
  PIN pma_tx[493]
    DIRECTION OUTPUT ;
    USE SIGNAL ;
    SHAPE ABUTMENT ;
    PORT
      LAYER M5 ;
      RECT 105.984 0.000 106.008 0.192 ;
    END
  END pma_tx[493]
  PIN pma_tx[494]
    DIRECTION OUTPUT ;
    USE SIGNAL ;
    SHAPE ABUTMENT ;
    PORT
      LAYER M5 ;
      RECT 106.176 0.000 106.200 0.192 ;
    END
  END pma_tx[494]
  PIN pma_tx[495]
    DIRECTION OUTPUT ;
    USE SIGNAL ;
    SHAPE ABUTMENT ;
    PORT
      LAYER M5 ;
      RECT 106.368 0.000 106.392 0.192 ;
    END
  END pma_tx[495]
  PIN pma_tx[496]
    DIRECTION OUTPUT ;
    USE SIGNAL ;
    SHAPE ABUTMENT ;
    PORT
      LAYER M5 ;
      RECT 106.608 0.000 106.632 0.192 ;
    END
  END pma_tx[496]
  PIN pma_tx[497]
    DIRECTION OUTPUT ;
    USE SIGNAL ;
    SHAPE ABUTMENT ;
    PORT
      LAYER M5 ;
      RECT 106.800 0.000 106.824 0.192 ;
    END
  END pma_tx[497]
  PIN pma_tx[498]
    DIRECTION OUTPUT ;
    USE SIGNAL ;
    SHAPE ABUTMENT ;
    PORT
      LAYER M5 ;
      RECT 106.992 0.000 107.016 0.192 ;
    END
  END pma_tx[498]
  PIN pma_tx[499]
    DIRECTION OUTPUT ;
    USE SIGNAL ;
    SHAPE ABUTMENT ;
    PORT
      LAYER M5 ;
      RECT 107.232 0.000 107.256 0.192 ;
    END
  END pma_tx[499]
  PIN pma_tx[500]
    DIRECTION OUTPUT ;
    USE SIGNAL ;
    SHAPE ABUTMENT ;
    PORT
      LAYER M5 ;
      RECT 107.424 0.000 107.448 0.192 ;
    END
  END pma_tx[500]
  PIN pma_tx[501]
    DIRECTION OUTPUT ;
    USE SIGNAL ;
    SHAPE ABUTMENT ;
    PORT
      LAYER M5 ;
      RECT 107.616 0.000 107.640 0.192 ;
    END
  END pma_tx[501]
  PIN pma_tx[502]
    DIRECTION OUTPUT ;
    USE SIGNAL ;
    SHAPE ABUTMENT ;
    PORT
      LAYER M5 ;
      RECT 107.808 0.000 107.832 0.192 ;
    END
  END pma_tx[502]
  PIN pma_tx[503]
    DIRECTION OUTPUT ;
    USE SIGNAL ;
    SHAPE ABUTMENT ;
    PORT
      LAYER M5 ;
      RECT 108.048 0.000 108.072 0.192 ;
    END
  END pma_tx[503]
  PIN pma_tx[504]
    DIRECTION OUTPUT ;
    USE SIGNAL ;
    SHAPE ABUTMENT ;
    PORT
      LAYER M5 ;
      RECT 108.240 0.000 108.264 0.192 ;
    END
  END pma_tx[504]
  PIN pma_tx[505]
    DIRECTION OUTPUT ;
    USE SIGNAL ;
    SHAPE ABUTMENT ;
    PORT
      LAYER M5 ;
      RECT 108.432 0.000 108.456 0.192 ;
    END
  END pma_tx[505]
  PIN pma_tx[506]
    DIRECTION OUTPUT ;
    USE SIGNAL ;
    SHAPE ABUTMENT ;
    PORT
      LAYER M5 ;
      RECT 108.672 0.000 108.696 0.192 ;
    END
  END pma_tx[506]
  PIN pma_tx[507]
    DIRECTION OUTPUT ;
    USE SIGNAL ;
    SHAPE ABUTMENT ;
    PORT
      LAYER M5 ;
      RECT 108.864 0.000 108.888 0.192 ;
    END
  END pma_tx[507]
  PIN pma_tx[508]
    DIRECTION OUTPUT ;
    USE SIGNAL ;
    SHAPE ABUTMENT ;
    PORT
      LAYER M5 ;
      RECT 109.056 0.000 109.080 0.192 ;
    END
  END pma_tx[508]
  PIN pma_tx[509]
    DIRECTION OUTPUT ;
    USE SIGNAL ;
    SHAPE ABUTMENT ;
    PORT
      LAYER M5 ;
      RECT 109.248 0.000 109.272 0.192 ;
    END
  END pma_tx[509]
  PIN pma_tx[510]
    DIRECTION OUTPUT ;
    USE SIGNAL ;
    SHAPE ABUTMENT ;
    PORT
      LAYER M5 ;
      RECT 109.488 0.000 109.512 0.192 ;
    END
  END pma_tx[510]
  PIN pma_tx[511]
    DIRECTION OUTPUT ;
    USE SIGNAL ;
    SHAPE ABUTMENT ;
    PORT
      LAYER M5 ;
      RECT 109.680 0.000 109.704 0.192 ;
    END
  END pma_tx[511]
  PIN pma_tx[512]
    DIRECTION OUTPUT ;
    USE SIGNAL ;
    SHAPE ABUTMENT ;
    PORT
      LAYER M5 ;
      RECT 109.872 0.000 109.896 0.192 ;
    END
  END pma_tx[512]
  PIN pma_tx[513]
    DIRECTION OUTPUT ;
    USE SIGNAL ;
    SHAPE ABUTMENT ;
    PORT
      LAYER M5 ;
      RECT 110.112 0.000 110.136 0.192 ;
    END
  END pma_tx[513]
  PIN pma_tx[514]
    DIRECTION OUTPUT ;
    USE SIGNAL ;
    SHAPE ABUTMENT ;
    PORT
      LAYER M5 ;
      RECT 110.304 0.000 110.328 0.192 ;
    END
  END pma_tx[514]
  PIN pma_tx[515]
    DIRECTION OUTPUT ;
    USE SIGNAL ;
    SHAPE ABUTMENT ;
    PORT
      LAYER M5 ;
      RECT 110.496 0.000 110.520 0.192 ;
    END
  END pma_tx[515]
  PIN pma_tx[516]
    DIRECTION OUTPUT ;
    USE SIGNAL ;
    SHAPE ABUTMENT ;
    PORT
      LAYER M5 ;
      RECT 110.688 0.000 110.712 0.192 ;
    END
  END pma_tx[516]
  PIN pma_tx[517]
    DIRECTION OUTPUT ;
    USE SIGNAL ;
    SHAPE ABUTMENT ;
    PORT
      LAYER M5 ;
      RECT 110.928 0.000 110.952 0.192 ;
    END
  END pma_tx[517]
  PIN pma_tx[518]
    DIRECTION OUTPUT ;
    USE SIGNAL ;
    SHAPE ABUTMENT ;
    PORT
      LAYER M5 ;
      RECT 111.120 0.000 111.144 0.192 ;
    END
  END pma_tx[518]
  PIN pma_tx[519]
    DIRECTION OUTPUT ;
    USE SIGNAL ;
    SHAPE ABUTMENT ;
    PORT
      LAYER M5 ;
      RECT 111.312 0.000 111.336 0.192 ;
    END
  END pma_tx[519]
  PIN pma_tx[520]
    DIRECTION OUTPUT ;
    USE SIGNAL ;
    SHAPE ABUTMENT ;
    PORT
      LAYER M5 ;
      RECT 111.552 0.000 111.576 0.192 ;
    END
  END pma_tx[520]
  PIN pma_tx[521]
    DIRECTION OUTPUT ;
    USE SIGNAL ;
    SHAPE ABUTMENT ;
    PORT
      LAYER M5 ;
      RECT 111.744 0.000 111.768 0.192 ;
    END
  END pma_tx[521]
  PIN pma_tx[522]
    DIRECTION OUTPUT ;
    USE SIGNAL ;
    SHAPE ABUTMENT ;
    PORT
      LAYER M5 ;
      RECT 111.936 0.000 111.960 0.192 ;
    END
  END pma_tx[522]
  PIN pma_tx[523]
    DIRECTION OUTPUT ;
    USE SIGNAL ;
    SHAPE ABUTMENT ;
    PORT
      LAYER M5 ;
      RECT 112.128 0.000 112.152 0.192 ;
    END
  END pma_tx[523]
  PIN pma_tx[524]
    DIRECTION OUTPUT ;
    USE SIGNAL ;
    SHAPE ABUTMENT ;
    PORT
      LAYER M5 ;
      RECT 112.368 0.000 112.392 0.192 ;
    END
  END pma_tx[524]
  PIN pma_tx[525]
    DIRECTION OUTPUT ;
    USE SIGNAL ;
    SHAPE ABUTMENT ;
    PORT
      LAYER M5 ;
      RECT 112.560 0.000 112.584 0.192 ;
    END
  END pma_tx[525]
  PIN pma_tx[526]
    DIRECTION OUTPUT ;
    USE SIGNAL ;
    SHAPE ABUTMENT ;
    PORT
      LAYER M5 ;
      RECT 112.752 0.000 112.776 0.192 ;
    END
  END pma_tx[526]
  PIN pma_tx[527]
    DIRECTION OUTPUT ;
    USE SIGNAL ;
    SHAPE ABUTMENT ;
    PORT
      LAYER M5 ;
      RECT 112.992 0.000 113.016 0.192 ;
    END
  END pma_tx[527]
  PIN pma_tx[528]
    DIRECTION OUTPUT ;
    USE SIGNAL ;
    SHAPE ABUTMENT ;
    PORT
      LAYER M5 ;
      RECT 113.184 0.000 113.208 0.192 ;
    END
  END pma_tx[528]
  PIN pma_tx[529]
    DIRECTION OUTPUT ;
    USE SIGNAL ;
    SHAPE ABUTMENT ;
    PORT
      LAYER M5 ;
      RECT 113.376 0.000 113.400 0.192 ;
    END
  END pma_tx[529]
  PIN pma_tx[530]
    DIRECTION OUTPUT ;
    USE SIGNAL ;
    SHAPE ABUTMENT ;
    PORT
      LAYER M5 ;
      RECT 113.568 0.000 113.592 0.192 ;
    END
  END pma_tx[530]
  PIN pma_tx[531]
    DIRECTION OUTPUT ;
    USE SIGNAL ;
    SHAPE ABUTMENT ;
    PORT
      LAYER M5 ;
      RECT 113.808 0.000 113.832 0.192 ;
    END
  END pma_tx[531]
  PIN pma_tx[532]
    DIRECTION OUTPUT ;
    USE SIGNAL ;
    SHAPE ABUTMENT ;
    PORT
      LAYER M5 ;
      RECT 114.000 0.000 114.024 0.192 ;
    END
  END pma_tx[532]
  PIN pma_tx[533]
    DIRECTION OUTPUT ;
    USE SIGNAL ;
    SHAPE ABUTMENT ;
    PORT
      LAYER M5 ;
      RECT 114.192 0.000 114.216 0.192 ;
    END
  END pma_tx[533]
  PIN pma_tx[534]
    DIRECTION OUTPUT ;
    USE SIGNAL ;
    SHAPE ABUTMENT ;
    PORT
      LAYER M5 ;
      RECT 114.432 0.000 114.456 0.192 ;
    END
  END pma_tx[534]
  PIN pma_tx[535]
    DIRECTION OUTPUT ;
    USE SIGNAL ;
    SHAPE ABUTMENT ;
    PORT
      LAYER M5 ;
      RECT 114.624 0.000 114.648 0.192 ;
    END
  END pma_tx[535]
  PIN pma_tx[536]
    DIRECTION OUTPUT ;
    USE SIGNAL ;
    SHAPE ABUTMENT ;
    PORT
      LAYER M5 ;
      RECT 114.816 0.000 114.840 0.192 ;
    END
  END pma_tx[536]
  PIN pma_tx[537]
    DIRECTION OUTPUT ;
    USE SIGNAL ;
    SHAPE ABUTMENT ;
    PORT
      LAYER M5 ;
      RECT 115.008 0.000 115.032 0.192 ;
    END
  END pma_tx[537]
  PIN pma_tx[538]
    DIRECTION OUTPUT ;
    USE SIGNAL ;
    SHAPE ABUTMENT ;
    PORT
      LAYER M5 ;
      RECT 115.248 0.000 115.272 0.192 ;
    END
  END pma_tx[538]
  PIN pma_tx[539]
    DIRECTION OUTPUT ;
    USE SIGNAL ;
    SHAPE ABUTMENT ;
    PORT
      LAYER M5 ;
      RECT 115.440 0.000 115.464 0.192 ;
    END
  END pma_tx[539]
  PIN pma_tx[540]
    DIRECTION OUTPUT ;
    USE SIGNAL ;
    SHAPE ABUTMENT ;
    PORT
      LAYER M5 ;
      RECT 115.632 0.000 115.656 0.192 ;
    END
  END pma_tx[540]
  PIN pma_tx[541]
    DIRECTION OUTPUT ;
    USE SIGNAL ;
    SHAPE ABUTMENT ;
    PORT
      LAYER M5 ;
      RECT 115.872 0.000 115.896 0.192 ;
    END
  END pma_tx[541]
  PIN pma_tx[542]
    DIRECTION OUTPUT ;
    USE SIGNAL ;
    SHAPE ABUTMENT ;
    PORT
      LAYER M5 ;
      RECT 116.064 0.000 116.088 0.192 ;
    END
  END pma_tx[542]
  PIN pma_tx[543]
    DIRECTION OUTPUT ;
    USE SIGNAL ;
    SHAPE ABUTMENT ;
    PORT
      LAYER M5 ;
      RECT 116.256 0.000 116.280 0.192 ;
    END
  END pma_tx[543]
  PIN pma_tck
    DIRECTION OUTPUT ;
    USE SIGNAL ;
    SHAPE ABUTMENT ;
    PORT
      LAYER M5 ;
      RECT 121.008 0.000 121.032 0.192 ;
    END
  END pma_tck
  PIN VSS
    DIRECTION INOUT ;
    USE GROUND ;
    PORT
      LAYER M4 ;
      RECT 0.492 1.200 128.532 1.296 ;
      RECT 0.492 3.600 128.532 3.696 ;
      RECT 0.492 6.000 128.532 6.096 ;
      RECT 0.492 8.400 128.532 8.496 ;
      RECT 0.492 10.800 128.532 10.896 ;
      RECT 0.492 13.200 128.532 13.296 ;
      RECT 0.492 15.600 128.532 15.696 ;
      RECT 0.492 18.000 128.532 18.096 ;
      RECT 0.492 20.400 128.532 20.496 ;
      RECT 0.492 22.800 128.532 22.896 ;
      RECT 0.492 25.200 128.532 25.296 ;
      RECT 0.492 27.600 128.532 27.696 ;
      RECT 0.492 30.000 128.532 30.096 ;
      RECT 0.492 32.400 128.532 32.496 ;
      RECT 0.492 34.800 128.532 34.896 ;
      RECT 0.492 37.200 128.532 37.296 ;
      RECT 0.492 39.600 128.532 39.696 ;
      RECT 0.492 42.000 128.532 42.096 ;
      RECT 0.492 44.400 128.532 44.496 ;
      RECT 0.492 46.800 128.532 46.896 ;
      RECT 0.492 49.200 128.532 49.296 ;
      RECT 0.492 51.600 128.532 51.696 ;
      RECT 0.492 54.000 128.532 54.096 ;
      RECT 0.492 56.400 128.532 56.496 ;
      RECT 0.492 58.800 128.532 58.896 ;
      RECT 0.492 61.200 128.532 61.296 ;
      RECT 0.492 63.600 128.532 63.696 ;
      RECT 0.492 66.000 128.532 66.096 ;
      RECT 0.492 68.400 128.532 68.496 ;
      RECT 0.492 70.800 128.532 70.896 ;
      RECT 0.492 73.200 128.532 73.296 ;
      RECT 0.492 75.600 128.532 75.696 ;
      RECT 0.492 78.000 128.532 78.096 ;
      RECT 0.492 80.400 128.532 80.496 ;
      RECT 0.492 82.800 128.532 82.896 ;
      RECT 0.492 85.200 128.532 85.296 ;
      RECT 0.492 87.600 128.532 87.696 ;
      RECT 0.492 90.000 128.532 90.096 ;
      RECT 0.492 92.400 128.532 92.496 ;
      RECT 0.492 94.800 128.532 94.896 ;
      RECT 0.492 97.200 128.532 97.296 ;
      RECT 0.492 99.600 128.532 99.696 ;
      RECT 0.492 102.000 128.532 102.096 ;
      RECT 0.492 104.400 128.532 104.496 ;
      RECT 0.492 106.800 128.532 106.896 ;
      RECT 0.492 109.200 128.532 109.296 ;
      RECT 0.492 111.600 128.532 111.696 ;
      RECT 0.492 114.000 128.532 114.096 ;
      RECT 0.492 116.400 128.532 116.496 ;
      RECT 0.492 118.800 128.532 118.896 ;
      RECT 0.492 121.200 128.532 121.296 ;
      RECT 0.492 123.600 128.532 123.696 ;
      RECT 0.492 126.000 128.532 126.096 ;
      RECT 0.492 128.400 128.532 128.496 ;
      RECT 0.492 130.800 128.532 130.896 ;
      RECT 0.492 133.200 128.532 133.296 ;
      RECT 0.492 135.600 128.532 135.696 ;
      RECT 0.492 138.000 128.532 138.096 ;
      RECT 0.492 140.400 128.532 140.496 ;
      RECT 0.492 142.800 128.532 142.896 ;
      RECT 0.492 145.200 128.532 145.296 ;
      RECT 0.492 147.600 128.532 147.696 ;
      RECT 0.492 150.000 128.532 150.096 ;
      RECT 0.492 152.400 128.532 152.496 ;
      RECT 0.492 154.800 128.532 154.896 ;
      RECT 0.492 157.200 128.532 157.296 ;
      RECT 0.492 159.600 128.532 159.696 ;
      RECT 0.492 162.000 128.532 162.096 ;
      RECT 0.492 164.400 128.532 164.496 ;
      RECT 0.492 166.800 128.532 166.896 ;
      RECT 0.492 169.200 128.532 169.296 ;
      RECT 0.492 171.600 128.532 171.696 ;
      RECT 0.492 174.000 128.532 174.096 ;
      RECT 0.492 176.400 128.532 176.496 ;
      RECT 0.492 178.800 128.532 178.896 ;
      RECT 0.492 181.200 128.532 181.296 ;
      RECT 0.492 183.600 128.532 183.696 ;
      RECT 0.492 186.000 128.532 186.096 ;
      RECT 0.492 188.400 128.532 188.496 ;
      RECT 0.492 190.800 128.532 190.896 ;
      RECT 0.492 193.200 128.532 193.296 ;
      RECT 0.492 195.600 128.532 195.696 ;
      RECT 0.492 198.000 128.532 198.096 ;
      RECT 0.492 200.400 128.532 200.496 ;
      RECT 0.492 202.800 128.532 202.896 ;
      RECT 0.492 205.200 128.532 205.296 ;
      RECT 0.492 207.600 128.532 207.696 ;
      RECT 0.492 210.000 128.532 210.096 ;
      RECT 0.492 212.400 128.532 212.496 ;
      RECT 0.492 214.800 128.532 214.896 ;
      RECT 0.492 217.200 128.532 217.296 ;
      RECT 0.492 219.600 128.532 219.696 ;
      RECT 0.492 222.000 128.532 222.096 ;
      RECT 0.492 224.400 128.532 224.496 ;
      RECT 0.492 226.800 128.532 226.896 ;
      RECT 0.492 229.200 128.532 229.296 ;
      RECT 0.492 231.600 128.532 231.696 ;
      RECT 0.492 234.000 128.532 234.096 ;
      RECT 0.492 236.400 128.532 236.496 ;
      RECT 0.492 238.800 128.532 238.896 ;
      RECT 0.492 241.200 128.532 241.296 ;
      RECT 0.492 243.600 128.532 243.696 ;
      RECT 0.492 246.000 128.532 246.096 ;
      RECT 0.492 248.400 128.532 248.496 ;
      RECT 0.492 250.800 128.532 250.896 ;
      RECT 0.492 253.200 128.532 253.296 ;
      RECT 0.492 255.600 128.532 255.696 ;
      RECT 0.492 258.000 128.532 258.096 ;
      RECT 0.492 260.400 128.532 260.496 ;
      RECT 0.492 262.800 128.532 262.896 ;
      RECT 0.492 265.200 128.532 265.296 ;
      RECT 0.492 267.600 128.532 267.696 ;
      RECT 0.492 270.000 128.532 270.096 ;
      RECT 0.492 272.400 128.532 272.496 ;
      RECT 0.492 274.800 128.532 274.896 ;
      RECT 0.492 277.200 128.532 277.296 ;
      RECT 0.492 279.600 128.532 279.696 ;
      RECT 0.492 282.000 128.532 282.096 ;
      RECT 0.492 284.400 128.532 284.496 ;
      RECT 0.492 286.800 128.532 286.896 ;
      RECT 0.492 289.200 128.532 289.296 ;
      RECT 0.492 291.600 128.532 291.696 ;
      RECT 0.492 294.000 128.532 294.096 ;
      RECT 0.492 296.400 128.532 296.496 ;
      RECT 0.492 298.800 128.532 298.896 ;
      RECT 0.492 301.200 128.532 301.296 ;
      RECT 0.492 303.600 128.532 303.696 ;
      RECT 0.492 306.000 128.532 306.096 ;
      RECT 0.492 308.400 128.532 308.496 ;
      RECT 0.492 310.800 128.532 310.896 ;
      RECT 0.492 313.200 128.532 313.296 ;
      RECT 0.492 315.600 128.532 315.696 ;
      RECT 0.492 318.000 128.532 318.096 ;
      RECT 0.492 320.400 128.532 320.496 ;
      RECT 0.492 322.800 128.532 322.896 ;
      RECT 0.492 325.200 128.532 325.296 ;
      RECT 0.492 327.600 128.532 327.696 ;
      RECT 0.492 330.000 128.532 330.096 ;
      RECT 0.492 332.400 128.532 332.496 ;
      RECT 0.492 334.800 128.532 334.896 ;
      RECT 0.492 337.200 128.532 337.296 ;
      RECT 0.492 339.600 128.532 339.696 ;
      RECT 0.492 342.000 128.532 342.096 ;
      RECT 0.492 344.400 128.532 344.496 ;
      RECT 0.492 346.800 128.532 346.896 ;
      RECT 0.492 349.200 128.532 349.296 ;
      RECT 0.492 351.600 128.532 351.696 ;
      RECT 0.492 354.000 128.532 354.096 ;
      RECT 0.492 356.400 128.532 356.496 ;
      RECT 0.492 358.800 128.532 358.896 ;
      RECT 0.492 361.200 128.532 361.296 ;
      RECT 0.492 363.600 128.532 363.696 ;
      RECT 0.492 366.000 128.532 366.096 ;
      RECT 0.492 368.400 128.532 368.496 ;
      RECT 0.492 370.800 128.532 370.896 ;
      RECT 0.492 373.200 128.532 373.296 ;
      RECT 0.492 375.600 128.532 375.696 ;
      RECT 0.492 378.000 128.532 378.096 ;
      RECT 0.492 380.400 128.532 380.496 ;
      RECT 0.492 382.800 128.532 382.896 ;
      RECT 0.492 385.200 128.532 385.296 ;
      RECT 0.492 387.600 128.532 387.696 ;
      RECT 0.492 390.000 128.532 390.096 ;
      RECT 0.492 392.400 128.532 392.496 ;
      RECT 0.492 394.800 128.532 394.896 ;
      RECT 0.492 397.200 128.532 397.296 ;
      RECT 0.492 399.600 128.532 399.696 ;
      RECT 0.492 402.000 128.532 402.096 ;
      RECT 0.492 404.400 128.532 404.496 ;
      RECT 0.492 406.800 128.532 406.896 ;
      RECT 0.492 409.200 128.532 409.296 ;
      RECT 0.492 411.600 128.532 411.696 ;
      RECT 0.492 414.000 128.532 414.096 ;
      RECT 0.492 416.400 128.532 416.496 ;
      RECT 0.492 418.800 128.532 418.896 ;
      RECT 0.492 421.200 128.532 421.296 ;
      RECT 0.492 423.600 128.532 423.696 ;
      RECT 0.492 426.000 128.532 426.096 ;
      RECT 0.492 428.400 128.532 428.496 ;
      RECT 0.492 430.800 128.532 430.896 ;
      RECT 0.492 433.200 128.532 433.296 ;
      RECT 0.492 435.600 128.532 435.696 ;
      RECT 0.492 438.000 128.532 438.096 ;
      RECT 0.492 440.400 128.532 440.496 ;
      RECT 0.492 442.800 128.532 442.896 ;
      RECT 0.492 445.200 128.532 445.296 ;
      RECT 0.492 447.600 128.532 447.696 ;
      RECT 0.492 450.000 128.532 450.096 ;
      RECT 0.492 452.400 128.532 452.496 ;
      RECT 0.492 454.800 128.532 454.896 ;
      RECT 0.492 457.200 128.532 457.296 ;
      RECT 0.492 459.600 128.532 459.696 ;
      RECT 0.492 462.000 128.532 462.096 ;
      RECT 0.492 464.400 128.532 464.496 ;
      RECT 0.492 466.800 128.532 466.896 ;
      RECT 0.492 469.200 128.532 469.296 ;
      RECT 0.492 471.600 128.532 471.696 ;
      RECT 0.492 474.000 128.532 474.096 ;
      RECT 0.492 476.400 128.532 476.496 ;
      RECT 0.492 478.800 128.532 478.896 ;
      RECT 0.492 481.200 128.532 481.296 ;
      RECT 0.492 483.600 128.532 483.696 ;
      RECT 0.492 486.000 128.532 486.096 ;
      RECT 0.492 488.400 128.532 488.496 ;
      RECT 0.492 490.800 128.532 490.896 ;
      RECT 0.492 493.200 128.532 493.296 ;
      RECT 0.492 495.600 128.532 495.696 ;
      RECT 0.492 498.000 128.532 498.096 ;
      RECT 0.492 500.400 128.532 500.496 ;
      RECT 0.492 502.800 128.532 502.896 ;
      RECT 0.492 505.200 128.532 505.296 ;
      RECT 0.492 507.600 128.532 507.696 ;
      RECT 0.492 510.000 128.532 510.096 ;
      RECT 0.492 512.400 128.532 512.496 ;
      RECT 0.492 514.800 128.532 514.896 ;
      RECT 0.492 517.200 128.532 517.296 ;
      RECT 0.492 519.600 128.532 519.696 ;
      RECT 0.492 522.000 128.532 522.096 ;
      RECT 0.492 524.400 128.532 524.496 ;
      RECT 0.492 526.800 128.532 526.896 ;
      RECT 0.492 529.200 128.532 529.296 ;
      RECT 0.492 531.600 128.532 531.696 ;
      RECT 0.492 534.000 128.532 534.096 ;
      RECT 0.492 536.400 128.532 536.496 ;
      RECT 0.492 538.800 128.532 538.896 ;
      RECT 0.492 541.200 128.532 541.296 ;
      RECT 0.492 543.600 128.532 543.696 ;
      RECT 0.492 546.000 128.532 546.096 ;
      RECT 0.492 548.400 128.532 548.496 ;
      RECT 0.492 550.800 128.532 550.896 ;
      RECT 0.492 553.200 128.532 553.296 ;
      RECT 0.492 555.600 128.532 555.696 ;
      RECT 0.492 558.000 128.532 558.096 ;
      RECT 0.492 560.400 128.532 560.496 ;
      RECT 0.492 562.800 128.532 562.896 ;
      RECT 0.492 565.200 128.532 565.296 ;
      RECT 0.492 567.600 128.532 567.696 ;
      RECT 0.492 570.000 128.532 570.096 ;
      RECT 0.492 572.400 128.532 572.496 ;
      RECT 0.492 574.800 128.532 574.896 ;
      RECT 0.492 577.200 128.532 577.296 ;
      RECT 0.492 579.600 128.532 579.696 ;
      RECT 0.492 582.000 128.532 582.096 ;
      RECT 0.492 584.400 128.532 584.496 ;
      RECT 0.492 586.800 128.532 586.896 ;
      RECT 0.492 589.200 128.532 589.296 ;
      RECT 0.492 591.600 128.532 591.696 ;
      RECT 0.492 594.000 128.532 594.096 ;
      RECT 0.492 596.400 128.532 596.496 ;
      RECT 0.492 598.800 128.532 598.896 ;
      RECT 0.492 601.200 128.532 601.296 ;
      RECT 0.492 603.600 128.532 603.696 ;
      RECT 0.492 606.000 128.532 606.096 ;
      RECT 0.492 608.400 128.532 608.496 ;
      RECT 0.492 610.800 128.532 610.896 ;
      RECT 0.492 613.200 128.532 613.296 ;
      RECT 0.492 615.600 128.532 615.696 ;
      RECT 0.492 618.000 128.532 618.096 ;
      RECT 0.492 620.400 128.532 620.496 ;
      RECT 0.492 622.800 128.532 622.896 ;
      RECT 0.492 625.200 128.532 625.296 ;
      RECT 0.492 627.600 128.532 627.696 ;
      RECT 0.492 630.000 128.532 630.096 ;
      RECT 0.492 632.400 128.532 632.496 ;
      RECT 0.492 634.800 128.532 634.896 ;
      RECT 0.492 637.200 128.532 637.296 ;
      RECT 0.492 639.600 128.532 639.696 ;
      RECT 0.492 642.000 128.532 642.096 ;
      RECT 0.492 644.400 128.532 644.496 ;
      RECT 0.492 646.800 128.532 646.896 ;
      RECT 0.492 649.200 128.532 649.296 ;
      RECT 0.492 651.600 128.532 651.696 ;
      RECT 0.492 654.000 128.532 654.096 ;
      RECT 0.492 656.400 128.532 656.496 ;
      RECT 0.492 658.800 128.532 658.896 ;
      RECT 0.492 661.200 128.532 661.296 ;
      RECT 0.492 663.600 128.532 663.696 ;
      RECT 0.492 666.000 128.532 666.096 ;
      RECT 0.492 668.400 128.532 668.496 ;
      RECT 0.492 670.800 128.532 670.896 ;
      RECT 0.492 673.200 128.532 673.296 ;
      RECT 0.492 675.600 128.532 675.696 ;
      RECT 0.492 678.000 128.532 678.096 ;
      RECT 0.492 680.400 128.532 680.496 ;
      RECT 0.492 682.800 128.532 682.896 ;
      RECT 0.492 685.200 128.532 685.296 ;
      RECT 0.492 687.600 128.532 687.696 ;
      RECT 0.492 690.000 128.532 690.096 ;
      RECT 0.492 692.400 128.532 692.496 ;
      RECT 0.492 694.800 128.532 694.896 ;
      RECT 0.492 697.200 128.532 697.296 ;
      RECT 0.492 699.600 128.532 699.696 ;
      RECT 0.492 702.000 128.532 702.096 ;
      RECT 0.492 704.400 128.532 704.496 ;
      RECT 0.492 706.800 128.532 706.896 ;
      RECT 0.492 709.200 128.532 709.296 ;
      RECT 0.492 711.600 128.532 711.696 ;
      RECT 0.492 714.000 128.532 714.096 ;
      RECT 0.492 716.400 128.532 716.496 ;
      RECT 0.492 718.800 128.532 718.896 ;
      RECT 0.492 721.200 128.532 721.296 ;
      RECT 0.492 723.600 128.532 723.696 ;
      RECT 0.492 726.000 128.532 726.096 ;
      RECT 0.492 728.400 128.532 728.496 ;
      RECT 0.492 730.800 128.532 730.896 ;
      RECT 0.492 733.200 128.532 733.296 ;
      RECT 0.492 735.600 128.532 735.696 ;
      RECT 0.492 738.000 128.532 738.096 ;
      RECT 0.492 740.400 128.532 740.496 ;
      RECT 0.492 742.800 128.532 742.896 ;
      RECT 0.492 745.200 128.532 745.296 ;
      RECT 0.492 747.600 128.532 747.696 ;
      RECT 0.492 750.000 128.532 750.096 ;
      RECT 0.492 752.400 128.532 752.496 ;
      RECT 0.492 754.800 128.532 754.896 ;
      RECT 0.492 757.200 128.532 757.296 ;
      RECT 0.492 759.600 128.532 759.696 ;
      RECT 0.492 762.000 128.532 762.096 ;
      RECT 0.492 764.400 128.532 764.496 ;
      RECT 0.492 766.800 128.532 766.896 ;
      RECT 0.492 769.200 128.532 769.296 ;
      RECT 0.492 771.600 128.532 771.696 ;
      RECT 0.492 774.000 128.532 774.096 ;
      RECT 0.492 776.400 128.532 776.496 ;
      RECT 0.492 778.800 128.532 778.896 ;
      RECT 0.492 781.200 128.532 781.296 ;
      RECT 0.492 783.600 128.532 783.696 ;
      RECT 0.492 786.000 128.532 786.096 ;
      RECT 0.492 788.400 128.532 788.496 ;
      RECT 0.492 790.800 128.532 790.896 ;
      RECT 0.492 793.200 128.532 793.296 ;
      RECT 0.492 795.600 128.532 795.696 ;
      RECT 0.492 798.000 128.532 798.096 ;
      RECT 0.492 800.400 128.532 800.496 ;
      RECT 0.492 802.800 128.532 802.896 ;
      RECT 0.492 805.200 128.532 805.296 ;
      RECT 0.492 807.600 128.532 807.696 ;
      RECT 0.492 810.000 128.532 810.096 ;
      RECT 0.492 812.400 128.532 812.496 ;
      RECT 0.492 814.800 128.532 814.896 ;
      RECT 0.492 817.200 128.532 817.296 ;
      RECT 0.492 819.600 128.532 819.696 ;
      RECT 0.492 822.000 128.532 822.096 ;
      RECT 0.492 824.400 128.532 824.496 ;
      RECT 0.492 826.800 128.532 826.896 ;
      RECT 0.492 829.200 128.532 829.296 ;
      RECT 0.492 831.600 128.532 831.696 ;
      RECT 0.492 834.000 128.532 834.096 ;
      RECT 0.492 836.400 128.532 836.496 ;
      RECT 0.492 838.800 128.532 838.896 ;
      RECT 0.492 841.200 128.532 841.296 ;
      RECT 0.492 843.600 128.532 843.696 ;
      RECT 0.492 846.000 128.532 846.096 ;
      RECT 0.492 848.400 128.532 848.496 ;
      RECT 0.492 850.800 128.532 850.896 ;
      RECT 0.492 853.200 128.532 853.296 ;
      RECT 0.492 855.600 128.532 855.696 ;
      RECT 0.492 858.000 128.532 858.096 ;
      RECT 0.492 860.400 128.532 860.496 ;
      RECT 0.492 862.800 128.532 862.896 ;
      RECT 0.492 865.200 128.532 865.296 ;
      RECT 0.492 867.600 128.532 867.696 ;
      RECT 0.492 870.000 128.532 870.096 ;
      RECT 0.492 872.400 128.532 872.496 ;
      RECT 0.492 874.800 128.532 874.896 ;
      RECT 0.492 877.200 128.532 877.296 ;
      RECT 0.492 879.600 128.532 879.696 ;
      RECT 0.492 882.000 128.532 882.096 ;
      RECT 0.492 884.400 128.532 884.496 ;
      RECT 0.492 886.800 128.532 886.896 ;
      RECT 0.492 889.200 128.532 889.296 ;
      RECT 0.492 891.600 128.532 891.696 ;
      RECT 0.492 894.000 128.532 894.096 ;
      RECT 0.492 896.400 128.532 896.496 ;
      RECT 0.492 898.800 128.532 898.896 ;
      RECT 0.492 901.200 128.532 901.296 ;
      RECT 0.492 903.600 128.532 903.696 ;
      RECT 0.492 906.000 128.532 906.096 ;
      RECT 0.492 908.400 128.532 908.496 ;
      RECT 0.492 910.800 128.532 910.896 ;
      RECT 0.492 913.200 128.532 913.296 ;
      RECT 0.492 915.600 128.532 915.696 ;
      RECT 0.492 918.000 128.532 918.096 ;
      RECT 0.492 920.400 128.532 920.496 ;
      RECT 0.492 922.800 128.532 922.896 ;
      RECT 0.492 925.200 128.532 925.296 ;
      RECT 0.492 927.600 128.532 927.696 ;
      RECT 0.492 930.000 128.532 930.096 ;
      RECT 0.492 932.400 128.532 932.496 ;
      RECT 0.492 934.800 128.532 934.896 ;
      RECT 0.492 937.200 128.532 937.296 ;
      RECT 0.492 939.600 128.532 939.696 ;
      RECT 0.492 942.000 128.532 942.096 ;
      RECT 0.492 944.400 128.532 944.496 ;
      RECT 0.492 946.800 128.532 946.896 ;
      RECT 0.492 949.200 128.532 949.296 ;
      RECT 0.492 951.600 128.532 951.696 ;
      RECT 0.492 954.000 128.532 954.096 ;
      RECT 0.492 956.400 128.532 956.496 ;
      RECT 0.492 958.800 128.532 958.896 ;
      RECT 0.492 961.200 128.532 961.296 ;
      RECT 0.492 963.600 128.532 963.696 ;
      RECT 0.492 966.000 128.532 966.096 ;
      RECT 0.492 968.400 128.532 968.496 ;
      RECT 0.492 970.800 128.532 970.896 ;
      RECT 0.492 973.200 128.532 973.296 ;
      RECT 0.492 975.600 128.532 975.696 ;
      RECT 0.492 978.000 128.532 978.096 ;
      RECT 0.492 980.400 128.532 980.496 ;
      RECT 0.492 982.800 128.532 982.896 ;
      RECT 0.492 985.200 128.532 985.296 ;
      RECT 0.492 987.600 128.532 987.696 ;
      RECT 0.492 990.000 128.532 990.096 ;
      RECT 0.492 992.400 128.532 992.496 ;
      RECT 0.492 994.800 128.532 994.896 ;
      RECT 0.492 997.200 128.532 997.296 ;
      RECT 0.492 999.600 128.532 999.696 ;
      RECT 0.492 1002.000 128.532 1002.096 ;
      RECT 0.492 1004.400 128.532 1004.496 ;
      RECT 0.492 1006.800 128.532 1006.896 ;
      RECT 0.492 1009.200 128.532 1009.296 ;
      RECT 0.492 1011.600 128.532 1011.696 ;
      RECT 0.492 1014.000 128.532 1014.096 ;
      RECT 0.492 1016.400 128.532 1016.496 ;
      RECT 0.492 1018.800 128.532 1018.896 ;
      RECT 0.492 1021.200 128.532 1021.296 ;
      RECT 0.492 1023.600 128.532 1023.696 ;
      RECT 0.492 1026.000 128.532 1026.096 ;
      RECT 0.492 1028.400 128.532 1028.496 ;
      RECT 0.492 1030.800 128.532 1030.896 ;
      RECT 0.492 1033.200 128.532 1033.296 ;
      RECT 0.492 1035.600 128.532 1035.696 ;
      RECT 0.492 1038.000 128.532 1038.096 ;
      RECT 0.492 1040.400 128.532 1040.496 ;
      RECT 0.492 1042.800 128.532 1042.896 ;
      RECT 0.492 1045.200 128.532 1045.296 ;
      RECT 0.492 1047.600 128.532 1047.696 ;
      RECT 0.492 1050.000 128.532 1050.096 ;
      RECT 0.492 1052.400 128.532 1052.496 ;
      RECT 0.492 1054.800 128.532 1054.896 ;
      RECT 0.492 1057.200 128.532 1057.296 ;
      RECT 0.492 1059.600 128.532 1059.696 ;
      RECT 0.492 1062.000 128.532 1062.096 ;
      RECT 0.492 1064.400 128.532 1064.496 ;
      RECT 0.492 1066.800 128.532 1066.896 ;
      RECT 0.492 1069.200 128.532 1069.296 ;
      RECT 0.492 1071.600 128.532 1071.696 ;
      RECT 0.492 1074.000 128.532 1074.096 ;
      RECT 0.492 1076.400 128.532 1076.496 ;
      RECT 0.492 1078.800 128.532 1078.896 ;
      RECT 0.492 1081.200 128.532 1081.296 ;
      RECT 0.492 1083.600 128.532 1083.696 ;
      RECT 0.492 1086.000 128.532 1086.096 ;
      RECT 0.492 1088.400 128.532 1088.496 ;
      RECT 0.492 1090.800 128.532 1090.896 ;
      RECT 0.492 1093.200 128.532 1093.296 ;
      RECT 0.492 1095.600 128.532 1095.696 ;
      RECT 0.492 1098.000 128.532 1098.096 ;
      RECT 0.492 1100.400 128.532 1100.496 ;
      RECT 0.492 1102.800 128.532 1102.896 ;
      RECT 0.492 1105.200 128.532 1105.296 ;
      RECT 0.492 1107.600 128.532 1107.696 ;
      RECT 0.492 1110.000 128.532 1110.096 ;
      RECT 0.492 1112.400 128.532 1112.496 ;
      RECT 0.492 1114.800 128.532 1114.896 ;
      RECT 0.492 1117.200 128.532 1117.296 ;
      RECT 0.492 1119.600 128.532 1119.696 ;
      RECT 0.492 1122.000 128.532 1122.096 ;
      RECT 0.492 1124.400 128.532 1124.496 ;
      RECT 0.492 1126.800 128.532 1126.896 ;
      RECT 0.492 1129.200 128.532 1129.296 ;
      RECT 0.492 1131.600 128.532 1131.696 ;
      RECT 0.492 1134.000 128.532 1134.096 ;
      RECT 0.492 1136.400 128.532 1136.496 ;
      RECT 0.492 1138.800 128.532 1138.896 ;
      RECT 0.492 1141.200 128.532 1141.296 ;
      RECT 0.492 1143.600 128.532 1143.696 ;
      RECT 0.492 1146.000 128.532 1146.096 ;
      RECT 0.492 1148.400 128.532 1148.496 ;
      RECT 0.492 1150.800 128.532 1150.896 ;
      RECT 0.492 1153.200 128.532 1153.296 ;
      RECT 0.492 1155.600 128.532 1155.696 ;
      RECT 0.492 1158.000 128.532 1158.096 ;
      RECT 0.492 1160.400 128.532 1160.496 ;
      RECT 0.492 1162.800 128.532 1162.896 ;
      RECT 0.492 1165.200 128.532 1165.296 ;
      RECT 0.492 1167.600 128.532 1167.696 ;
      RECT 0.492 1170.000 128.532 1170.096 ;
      RECT 0.492 1172.400 128.532 1172.496 ;
      RECT 0.492 1174.800 128.532 1174.896 ;
      RECT 0.492 1177.200 128.532 1177.296 ;
      RECT 0.492 1179.600 128.532 1179.696 ;
      RECT 0.492 1182.000 128.532 1182.096 ;
      RECT 0.492 1184.400 128.532 1184.496 ;
      RECT 0.492 1186.800 128.532 1186.896 ;
      RECT 0.492 1189.200 128.532 1189.296 ;
      RECT 0.492 1191.600 128.532 1191.696 ;
      RECT 0.492 1194.000 128.532 1194.096 ;
      RECT 0.492 1196.400 128.532 1196.496 ;
      RECT 0.492 1198.800 128.532 1198.896 ;
      RECT 0.492 1201.200 128.532 1201.296 ;
      RECT 0.492 1203.600 128.532 1203.696 ;
      RECT 0.492 1206.000 128.532 1206.096 ;
      RECT 0.492 1208.400 128.532 1208.496 ;
      RECT 0.492 1210.800 128.532 1210.896 ;
      RECT 0.492 1213.200 128.532 1213.296 ;
      RECT 0.492 1215.600 128.532 1215.696 ;
      RECT 0.492 1218.000 128.532 1218.096 ;
      RECT 0.492 1220.400 128.532 1220.496 ;
      RECT 0.492 1222.800 128.532 1222.896 ;
      RECT 0.492 1225.200 128.532 1225.296 ;
      RECT 0.492 1227.600 128.532 1227.696 ;
      RECT 0.492 1230.000 128.532 1230.096 ;
      RECT 0.492 1232.400 128.532 1232.496 ;
      RECT 0.492 1234.800 128.532 1234.896 ;
      RECT 0.492 1237.200 128.532 1237.296 ;
      RECT 0.492 1239.600 128.532 1239.696 ;
      RECT 0.492 1242.000 128.532 1242.096 ;
      RECT 0.492 1244.400 128.532 1244.496 ;
      RECT 0.492 1246.800 128.532 1246.896 ;
      RECT 0.492 1249.200 128.532 1249.296 ;
      RECT 0.492 1251.600 128.532 1251.696 ;
      RECT 0.492 1254.000 128.532 1254.096 ;
      RECT 0.492 1256.400 128.532 1256.496 ;
      RECT 0.492 1258.800 128.532 1258.896 ;
      RECT 0.492 1261.200 128.532 1261.296 ;
      RECT 0.492 1263.600 128.532 1263.696 ;
      RECT 0.492 1266.000 128.532 1266.096 ;
      RECT 0.492 1268.400 128.532 1268.496 ;
      RECT 0.492 1270.800 128.532 1270.896 ;
      RECT 0.492 1273.200 128.532 1273.296 ;
      RECT 0.492 1275.600 128.532 1275.696 ;
      RECT 0.492 1278.000 128.532 1278.096 ;
      RECT 0.492 1280.400 128.532 1280.496 ;
      RECT 0.492 1282.800 128.532 1282.896 ;
      RECT 0.492 1285.200 128.532 1285.296 ;
      RECT 0.492 1287.600 128.532 1287.696 ;
      RECT 0.492 1290.000 128.532 1290.096 ;
      RECT 0.492 1292.400 128.532 1292.496 ;
      RECT 0.492 1294.800 128.532 1294.896 ;
      RECT 0.492 1297.200 128.532 1297.296 ;
      RECT 0.492 1299.600 128.532 1299.696 ;
      RECT 0.492 1302.000 128.532 1302.096 ;
      RECT 0.492 1304.400 128.532 1304.496 ;
      RECT 0.492 1306.800 128.532 1306.896 ;
      RECT 0.492 1309.200 128.532 1309.296 ;
      RECT 0.492 1311.600 128.532 1311.696 ;
      RECT 0.492 1314.000 128.532 1314.096 ;
      RECT 0.492 1316.400 128.532 1316.496 ;
      RECT 0.492 1318.800 128.532 1318.896 ;
      RECT 0.492 1321.200 128.532 1321.296 ;
      RECT 0.492 1323.600 128.532 1323.696 ;
      RECT 0.492 1326.000 128.532 1326.096 ;
      RECT 0.492 1328.400 128.532 1328.496 ;
      RECT 0.492 1330.800 128.532 1330.896 ;
      RECT 0.492 1333.200 128.532 1333.296 ;
      RECT 0.492 1335.600 128.532 1335.696 ;
      RECT 0.492 1338.000 128.532 1338.096 ;
      RECT 0.492 1340.400 128.532 1340.496 ;
      RECT 0.492 1342.800 128.532 1342.896 ;
      RECT 0.492 1345.200 128.532 1345.296 ;
      RECT 0.492 1347.600 128.532 1347.696 ;
      RECT 0.492 1350.000 128.532 1350.096 ;
      RECT 0.492 1352.400 128.532 1352.496 ;
      RECT 0.492 1354.800 128.532 1354.896 ;
      RECT 0.492 1357.200 128.532 1357.296 ;
      RECT 0.492 1359.600 128.532 1359.696 ;
      RECT 0.492 1362.000 128.532 1362.096 ;
      RECT 0.492 1364.400 128.532 1364.496 ;
      RECT 0.492 1366.800 128.532 1366.896 ;
      RECT 0.492 1369.200 128.532 1369.296 ;
      RECT 0.492 1371.600 128.532 1371.696 ;
      RECT 0.492 1374.000 128.532 1374.096 ;
      RECT 0.492 1376.400 128.532 1376.496 ;
      RECT 0.492 1378.800 128.532 1378.896 ;
      RECT 0.492 1381.200 128.532 1381.296 ;
      RECT 0.492 1383.600 128.532 1383.696 ;
      RECT 0.492 1386.000 128.532 1386.096 ;
      RECT 0.492 1388.400 128.532 1388.496 ;
      RECT 0.492 1390.800 128.532 1390.896 ;
      RECT 0.492 1393.200 128.532 1393.296 ;
      RECT 0.492 1395.600 128.532 1395.696 ;
      RECT 0.492 1398.000 128.532 1398.096 ;
      RECT 0.492 1400.400 128.532 1400.496 ;
      RECT 0.492 1402.800 128.532 1402.896 ;
      RECT 0.492 1405.200 128.532 1405.296 ;
      RECT 0.492 1407.600 128.532 1407.696 ;
      RECT 0.492 1410.000 128.532 1410.096 ;
      RECT 0.492 1412.400 128.532 1412.496 ;
      RECT 0.492 1414.800 128.532 1414.896 ;
      RECT 0.492 1417.200 128.532 1417.296 ;
      RECT 0.492 1419.600 128.532 1419.696 ;
      RECT 0.492 1422.000 128.532 1422.096 ;
      RECT 0.492 1424.400 128.532 1424.496 ;
      RECT 0.492 1426.800 128.532 1426.896 ;
      RECT 0.492 1429.200 128.532 1429.296 ;
      RECT 0.492 1431.600 128.532 1431.696 ;
      RECT 0.492 1434.000 128.532 1434.096 ;
      RECT 0.492 1436.400 128.532 1436.496 ;
      RECT 0.492 1438.800 128.532 1438.896 ;
      RECT 0.492 1441.200 128.532 1441.296 ;
      RECT 0.492 1443.600 128.532 1443.696 ;
      RECT 0.492 1446.000 128.532 1446.096 ;
      RECT 0.492 1448.400 128.532 1448.496 ;
      RECT 0.492 1450.800 128.532 1450.896 ;
      RECT 0.492 1453.200 128.532 1453.296 ;
      RECT 0.492 1455.600 128.532 1455.696 ;
      RECT 0.492 1458.000 128.532 1458.096 ;
      RECT 0.492 1460.400 128.532 1460.496 ;
      RECT 0.492 1462.800 128.532 1462.896 ;
      RECT 0.492 1465.200 128.532 1465.296 ;
      RECT 0.492 1467.600 128.532 1467.696 ;
      RECT 0.492 1470.000 128.532 1470.096 ;
      RECT 0.492 1472.400 128.532 1472.496 ;
      RECT 0.492 1474.800 128.532 1474.896 ;
      RECT 0.492 1477.200 128.532 1477.296 ;
      RECT 0.492 1479.600 128.532 1479.696 ;
      RECT 0.492 1482.000 128.532 1482.096 ;
      RECT 0.492 1484.400 128.532 1484.496 ;
      RECT 0.492 1486.800 128.532 1486.896 ;
      RECT 0.492 1489.200 128.532 1489.296 ;
      RECT 0.492 1491.600 128.532 1491.696 ;
      RECT 0.492 1494.000 128.532 1494.096 ;
      RECT 0.492 1496.400 128.532 1496.496 ;
      RECT 0.492 1498.800 128.532 1498.896 ;
      RECT 0.492 1501.200 128.532 1501.296 ;
      RECT 0.492 1503.600 128.532 1503.696 ;
      RECT 0.492 1506.000 128.532 1506.096 ;
      RECT 0.492 1508.400 128.532 1508.496 ;
      RECT 0.492 1510.800 128.532 1510.896 ;
      RECT 0.492 1513.200 128.532 1513.296 ;
      RECT 0.492 1515.600 128.532 1515.696 ;
      RECT 0.492 1518.000 128.532 1518.096 ;
      RECT 0.492 1520.400 128.532 1520.496 ;
      RECT 0.492 1522.800 128.532 1522.896 ;
      RECT 0.492 1525.200 128.532 1525.296 ;
      RECT 0.492 1527.600 128.532 1527.696 ;
      RECT 0.492 1530.000 128.532 1530.096 ;
      RECT 0.492 1532.400 128.532 1532.496 ;
      RECT 0.492 1534.800 128.532 1534.896 ;
      RECT 0.492 1537.200 128.532 1537.296 ;
      RECT 0.492 1539.600 128.532 1539.696 ;
      RECT 0.492 1542.000 128.532 1542.096 ;
      RECT 0.492 1544.400 128.532 1544.496 ;
      RECT 0.492 1546.800 128.532 1546.896 ;
      RECT 0.492 1549.200 128.532 1549.296 ;
      RECT 0.492 1551.600 128.532 1551.696 ;
      RECT 0.492 1554.000 128.532 1554.096 ;
      RECT 0.492 1556.400 128.532 1556.496 ;
      RECT 0.492 1558.800 128.532 1558.896 ;
      RECT 0.492 1561.200 128.532 1561.296 ;
      RECT 0.492 1563.600 128.532 1563.696 ;
      RECT 0.492 1566.000 128.532 1566.096 ;
      RECT 0.492 1568.400 128.532 1568.496 ;
      RECT 0.492 1570.800 128.532 1570.896 ;
      RECT 0.492 1573.200 128.532 1573.296 ;
      RECT 0.492 1575.600 128.532 1575.696 ;
      RECT 0.492 1578.000 128.532 1578.096 ;
      RECT 0.492 1580.400 128.532 1580.496 ;
      RECT 0.492 1582.800 128.532 1582.896 ;
      RECT 0.492 1585.200 128.532 1585.296 ;
      RECT 0.492 1587.600 128.532 1587.696 ;
      RECT 0.492 1590.000 128.532 1590.096 ;
      RECT 0.492 1592.400 128.532 1592.496 ;
      RECT 0.492 1594.800 128.532 1594.896 ;
      RECT 0.492 1597.200 128.532 1597.296 ;
      RECT 0.492 1599.600 128.532 1599.696 ;
      RECT 0.492 1602.000 128.532 1602.096 ;
      RECT 0.492 1604.400 128.532 1604.496 ;
      RECT 0.492 1606.800 128.532 1606.896 ;
      RECT 0.492 1609.200 128.532 1609.296 ;
      RECT 0.492 1611.600 128.532 1611.696 ;
      RECT 0.492 1614.000 128.532 1614.096 ;
      RECT 0.492 1616.400 128.532 1616.496 ;
      RECT 0.492 1618.800 128.532 1618.896 ;
      RECT 0.492 1621.200 128.532 1621.296 ;
      RECT 0.492 1623.600 128.532 1623.696 ;
      RECT 0.492 1626.000 128.532 1626.096 ;
      RECT 0.492 1628.400 128.532 1628.496 ;
      RECT 0.492 1630.800 128.532 1630.896 ;
      RECT 0.492 1633.200 128.532 1633.296 ;
      RECT 0.492 1635.600 128.532 1635.696 ;
      RECT 0.492 1638.000 128.532 1638.096 ;
      RECT 0.492 1640.400 128.532 1640.496 ;
      RECT 0.492 1642.800 128.532 1642.896 ;
      RECT 0.492 1645.200 128.532 1645.296 ;
      RECT 0.492 1647.600 128.532 1647.696 ;
      RECT 0.492 1650.000 128.532 1650.096 ;
      RECT 0.492 1652.400 128.532 1652.496 ;
      RECT 0.492 1654.800 128.532 1654.896 ;
      RECT 0.492 1657.200 128.532 1657.296 ;
      RECT 0.492 1659.600 128.532 1659.696 ;
      RECT 0.492 1662.000 128.532 1662.096 ;
      RECT 0.492 1664.400 128.532 1664.496 ;
      RECT 0.492 1666.800 128.532 1666.896 ;
      RECT 0.492 1669.200 128.532 1669.296 ;
      RECT 0.492 1671.600 128.532 1671.696 ;
      RECT 0.492 1674.000 128.532 1674.096 ;
      RECT 0.492 1676.400 128.532 1676.496 ;
      RECT 0.492 1678.800 128.532 1678.896 ;
      RECT 0.492 1681.200 128.532 1681.296 ;
      RECT 0.492 1683.600 128.532 1683.696 ;
      RECT 0.492 1686.000 128.532 1686.096 ;
      RECT 0.492 1688.400 128.532 1688.496 ;
      RECT 0.492 1690.800 128.532 1690.896 ;
      RECT 0.492 1693.200 128.532 1693.296 ;
      RECT 0.492 1695.600 128.532 1695.696 ;
      RECT 0.492 1698.000 128.532 1698.096 ;
      RECT 0.492 1700.400 128.532 1700.496 ;
      RECT 0.492 1702.800 128.532 1702.896 ;
      RECT 0.492 1705.200 128.532 1705.296 ;
      RECT 0.492 1707.600 128.532 1707.696 ;
      RECT 0.492 1710.000 128.532 1710.096 ;
      RECT 0.492 1712.400 128.532 1712.496 ;
      RECT 0.492 1714.800 128.532 1714.896 ;
      RECT 0.492 1717.200 128.532 1717.296 ;
      RECT 0.492 1719.600 128.532 1719.696 ;
      RECT 0.492 1722.000 128.532 1722.096 ;
      RECT 0.492 1724.400 128.532 1724.496 ;
      RECT 0.492 1726.800 128.532 1726.896 ;
      RECT 0.492 1729.200 128.532 1729.296 ;
      RECT 0.492 1731.600 128.532 1731.696 ;
      RECT 0.492 1734.000 128.532 1734.096 ;
      RECT 0.492 1736.400 128.532 1736.496 ;
      RECT 0.492 1738.800 128.532 1738.896 ;
      RECT 0.492 1741.200 128.532 1741.296 ;
      RECT 0.492 1743.600 128.532 1743.696 ;
      RECT 0.492 1746.000 128.532 1746.096 ;
      RECT 0.492 1748.400 128.532 1748.496 ;
      RECT 0.492 1750.800 128.532 1750.896 ;
      RECT 0.492 1753.200 128.532 1753.296 ;
      RECT 0.492 1755.600 128.532 1755.696 ;
      RECT 0.492 1758.000 128.532 1758.096 ;
      RECT 0.492 1760.400 128.532 1760.496 ;
      RECT 0.492 1762.800 128.532 1762.896 ;
      RECT 0.492 1765.200 128.532 1765.296 ;
      RECT 0.492 1767.600 128.532 1767.696 ;
      RECT 0.492 1770.000 128.532 1770.096 ;
      RECT 0.492 1772.400 128.532 1772.496 ;
      RECT 0.492 1774.800 128.532 1774.896 ;
      RECT 0.492 1777.200 128.532 1777.296 ;
      RECT 0.492 1779.600 128.532 1779.696 ;
      RECT 0.492 1782.000 128.532 1782.096 ;
      RECT 0.492 1784.400 128.532 1784.496 ;
      RECT 0.492 1786.800 128.532 1786.896 ;
      RECT 0.492 1789.200 128.532 1789.296 ;
      RECT 0.492 1791.600 128.532 1791.696 ;
      RECT 0.492 1794.000 128.532 1794.096 ;
      RECT 0.492 1796.400 128.532 1796.496 ;
      RECT 0.492 1798.800 128.532 1798.896 ;
      RECT 0.492 1801.200 128.532 1801.296 ;
      RECT 0.492 1803.600 128.532 1803.696 ;
      RECT 0.492 1806.000 128.532 1806.096 ;
      RECT 0.492 1808.400 128.532 1808.496 ;
      RECT 0.492 1810.800 128.532 1810.896 ;
      RECT 0.492 1813.200 128.532 1813.296 ;
      RECT 0.492 1815.600 128.532 1815.696 ;
      RECT 0.492 1818.000 128.532 1818.096 ;
      RECT 0.492 1820.400 128.532 1820.496 ;
      RECT 0.492 1822.800 128.532 1822.896 ;
      RECT 0.492 1825.200 128.532 1825.296 ;
      RECT 0.492 1827.600 128.532 1827.696 ;
      RECT 0.492 1830.000 128.532 1830.096 ;
      RECT 0.492 1832.400 128.532 1832.496 ;
      RECT 0.492 1834.800 128.532 1834.896 ;
      RECT 0.492 1837.200 128.532 1837.296 ;
      RECT 0.492 1839.600 128.532 1839.696 ;
      RECT 0.492 1842.000 128.532 1842.096 ;
      RECT 0.492 1844.400 128.532 1844.496 ;
      RECT 0.492 1846.800 128.532 1846.896 ;
      RECT 0.492 1849.200 128.532 1849.296 ;
      RECT 0.492 1851.600 128.532 1851.696 ;
      RECT 0.492 1854.000 128.532 1854.096 ;
      RECT 0.492 1856.400 128.532 1856.496 ;
      RECT 0.492 1858.800 128.532 1858.896 ;
      RECT 0.492 1861.200 128.532 1861.296 ;
      RECT 0.492 1863.600 128.532 1863.696 ;
      RECT 0.492 1866.000 128.532 1866.096 ;
      RECT 0.492 1868.400 128.532 1868.496 ;
      RECT 0.492 1870.800 128.532 1870.896 ;
      RECT 0.492 1873.200 128.532 1873.296 ;
      RECT 0.492 1875.600 128.532 1875.696 ;
      RECT 0.492 1878.000 128.532 1878.096 ;
      RECT 0.492 1880.400 128.532 1880.496 ;
      RECT 0.492 1882.800 128.532 1882.896 ;
      RECT 0.492 1885.200 128.532 1885.296 ;
      RECT 0.492 1887.600 128.532 1887.696 ;
      RECT 0.492 1890.000 128.532 1890.096 ;
      RECT 0.492 1892.400 128.532 1892.496 ;
      RECT 0.492 1894.800 128.532 1894.896 ;
      RECT 0.492 1897.200 128.532 1897.296 ;
      RECT 0.492 1899.600 128.532 1899.696 ;
      RECT 0.492 1902.000 128.532 1902.096 ;
      RECT 0.492 1904.400 128.532 1904.496 ;
      RECT 0.492 1906.800 128.532 1906.896 ;
      RECT 0.492 1909.200 128.532 1909.296 ;
      RECT 0.492 1911.600 128.532 1911.696 ;
      RECT 0.492 1914.000 128.532 1914.096 ;
      RECT 0.492 1916.400 128.532 1916.496 ;
      RECT 0.492 1918.800 128.532 1918.896 ;
      RECT 0.492 1921.200 128.532 1921.296 ;
      RECT 0.492 1923.600 128.532 1923.696 ;
      RECT 0.492 1926.000 128.532 1926.096 ;
      RECT 0.492 1928.400 128.532 1928.496 ;
      RECT 0.492 1930.800 128.532 1930.896 ;
      RECT 0.492 1933.200 128.532 1933.296 ;
      RECT 0.492 1935.600 128.532 1935.696 ;
      RECT 0.492 1938.000 128.532 1938.096 ;
      RECT 0.492 1940.400 128.532 1940.496 ;
      RECT 0.492 1942.800 128.532 1942.896 ;
      RECT 0.492 1945.200 128.532 1945.296 ;
      RECT 0.492 1947.600 128.532 1947.696 ;
      RECT 0.492 1950.000 128.532 1950.096 ;
      RECT 0.492 1952.400 128.532 1952.496 ;
      RECT 0.492 1954.800 128.532 1954.896 ;
      RECT 0.492 1957.200 128.532 1957.296 ;
      RECT 0.492 1959.600 128.532 1959.696 ;
      RECT 0.492 1962.000 128.532 1962.096 ;
      RECT 0.492 1964.400 128.532 1964.496 ;
      RECT 0.492 1966.800 128.532 1966.896 ;
      RECT 0.492 1969.200 128.532 1969.296 ;
      RECT 0.492 1971.600 128.532 1971.696 ;
      RECT 0.492 1974.000 128.532 1974.096 ;
      RECT 0.492 1976.400 128.532 1976.496 ;
      RECT 0.492 1978.800 128.532 1978.896 ;
      RECT 0.492 1981.200 128.532 1981.296 ;
      RECT 0.492 1983.600 128.532 1983.696 ;
      RECT 0.492 1986.000 128.532 1986.096 ;
      RECT 0.492 1988.400 128.532 1988.496 ;
      RECT 0.492 1990.800 128.532 1990.896 ;
      RECT 0.492 1993.200 128.532 1993.296 ;
      RECT 0.492 1995.600 128.532 1995.696 ;
      RECT 0.492 1998.000 128.532 1998.096 ;
      RECT 0.492 2000.400 128.532 2000.496 ;
      RECT 0.492 2002.800 128.532 2002.896 ;
      RECT 0.492 2005.200 128.532 2005.296 ;
      RECT 0.492 2007.600 128.532 2007.696 ;
      RECT 0.492 2010.000 128.532 2010.096 ;
      RECT 0.492 2012.400 128.532 2012.496 ;
      RECT 0.492 2014.800 128.532 2014.896 ;
      RECT 0.492 2017.200 128.532 2017.296 ;
      RECT 0.492 2019.600 128.532 2019.696 ;
      RECT 0.492 2022.000 128.532 2022.096 ;
      RECT 0.492 2024.400 128.532 2024.496 ;
      RECT 0.492 2026.800 128.532 2026.896 ;
      RECT 0.492 2029.200 128.532 2029.296 ;
      RECT 0.492 2031.600 128.532 2031.696 ;
      RECT 0.492 2034.000 128.532 2034.096 ;
      RECT 0.492 2036.400 128.532 2036.496 ;
      RECT 0.492 2038.800 128.532 2038.896 ;
      RECT 0.492 2041.200 128.532 2041.296 ;
      RECT 0.492 2043.600 128.532 2043.696 ;
      RECT 0.492 2046.000 128.532 2046.096 ;
      RECT 0.492 2048.400 128.532 2048.496 ;
      RECT 0.492 2050.800 128.532 2050.896 ;
      RECT 0.492 2053.200 128.532 2053.296 ;
      RECT 0.492 2055.600 128.532 2055.696 ;
      RECT 0.492 2058.000 128.532 2058.096 ;
      RECT 0.492 2060.400 128.532 2060.496 ;
      RECT 0.492 2062.800 128.532 2062.896 ;
      RECT 0.492 2065.200 128.532 2065.296 ;
      RECT 0.492 2067.600 128.532 2067.696 ;
      RECT 0.492 2070.000 128.532 2070.096 ;
      RECT 0.492 2072.400 128.532 2072.496 ;
      RECT 0.492 2074.800 128.532 2074.896 ;
      RECT 0.492 2077.200 128.532 2077.296 ;
      RECT 0.492 2079.600 128.532 2079.696 ;
      RECT 0.492 2082.000 128.532 2082.096 ;
      RECT 0.492 2084.400 128.532 2084.496 ;
      RECT 0.492 2086.800 128.532 2086.896 ;
      RECT 0.492 2089.200 128.532 2089.296 ;
      RECT 0.492 2091.600 128.532 2091.696 ;
      RECT 0.492 2094.000 128.532 2094.096 ;
      RECT 0.492 2096.400 128.532 2096.496 ;
      RECT 0.492 2098.800 128.532 2098.896 ;
      RECT 0.492 2101.200 128.532 2101.296 ;
      RECT 0.492 2103.600 128.532 2103.696 ;
      RECT 0.492 2106.000 128.532 2106.096 ;
      RECT 0.492 2108.400 128.532 2108.496 ;
      RECT 0.492 2110.800 128.532 2110.896 ;
      RECT 0.492 2113.200 128.532 2113.296 ;
      RECT 0.492 2115.600 128.532 2115.696 ;
      RECT 0.492 2118.000 128.532 2118.096 ;
      RECT 0.492 2120.400 128.532 2120.496 ;
      RECT 0.492 2122.800 128.532 2122.896 ;
      RECT 0.492 2125.200 128.532 2125.296 ;
      RECT 0.492 2127.600 128.532 2127.696 ;
      RECT 0.492 2130.000 128.532 2130.096 ;
      RECT 0.492 2132.400 128.532 2132.496 ;
      RECT 0.492 2134.800 128.532 2134.896 ;
      RECT 0.492 2137.200 128.532 2137.296 ;
      RECT 0.492 2139.600 128.532 2139.696 ;
      RECT 0.492 2142.000 128.532 2142.096 ;
      RECT 0.492 2144.400 128.532 2144.496 ;
      RECT 0.492 2146.800 128.532 2146.896 ;
      RECT 0.492 2149.200 128.532 2149.296 ;
      RECT 0.492 2151.600 128.532 2151.696 ;
      RECT 0.492 2154.000 128.532 2154.096 ;
      RECT 0.492 2156.400 128.532 2156.496 ;
      RECT 0.492 2158.800 128.532 2158.896 ;
      RECT 0.492 2161.200 128.532 2161.296 ;
      RECT 0.492 2163.600 128.532 2163.696 ;
      RECT 0.492 2166.000 128.532 2166.096 ;
      RECT 0.492 2168.400 128.532 2168.496 ;
      RECT 0.492 2170.800 128.532 2170.896 ;
      RECT 0.492 2173.200 128.532 2173.296 ;
      RECT 0.492 2175.600 128.532 2175.696 ;
      RECT 0.492 2178.000 128.532 2178.096 ;
      RECT 0.492 2180.400 128.532 2180.496 ;
      RECT 0.492 2182.800 128.532 2182.896 ;
      RECT 0.492 2185.200 128.532 2185.296 ;
      RECT 0.492 2187.600 128.532 2187.696 ;
      RECT 0.492 2190.000 128.532 2190.096 ;
      RECT 0.492 2192.400 128.532 2192.496 ;
      RECT 0.492 2194.800 128.532 2194.896 ;
      RECT 0.492 2197.200 128.532 2197.296 ;
      RECT 0.492 2199.600 128.532 2199.696 ;
      RECT 0.492 2202.000 128.532 2202.096 ;
      RECT 0.492 2204.400 128.532 2204.496 ;
      RECT 0.492 2206.800 128.532 2206.896 ;
      RECT 0.492 2209.200 128.532 2209.296 ;
      RECT 0.492 2211.600 128.532 2211.696 ;
      RECT 0.492 2214.000 128.532 2214.096 ;
      RECT 0.492 2216.400 128.532 2216.496 ;
      RECT 0.492 2218.800 128.532 2218.896 ;
      RECT 0.492 2221.200 128.532 2221.296 ;
      RECT 0.492 2223.600 128.532 2223.696 ;
      RECT 0.492 2226.000 128.532 2226.096 ;
      RECT 0.492 2228.400 128.532 2228.496 ;
      RECT 0.492 2230.800 128.532 2230.896 ;
      RECT 0.492 2233.200 128.532 2233.296 ;
      RECT 0.492 2235.600 128.532 2235.696 ;
      RECT 0.492 2238.000 128.532 2238.096 ;
      RECT 0.492 2240.400 128.532 2240.496 ;
      RECT 0.492 2242.800 128.532 2242.896 ;
      RECT 0.492 2245.200 128.532 2245.296 ;
      RECT 0.492 2247.600 128.532 2247.696 ;
    END
  END VSS
  PIN VDD
    DIRECTION INOUT ;
    USE POWER ;
    PORT
      LAYER M4 ;
      RECT 0.492 2.400 128.532 2.496 ;
      RECT 0.492 4.800 128.532 4.896 ;
      RECT 0.492 7.200 128.532 7.296 ;
      RECT 0.492 9.600 128.532 9.696 ;
      RECT 0.492 12.000 128.532 12.096 ;
      RECT 0.492 14.400 128.532 14.496 ;
      RECT 0.492 16.800 128.532 16.896 ;
      RECT 0.492 19.200 128.532 19.296 ;
      RECT 0.492 21.600 128.532 21.696 ;
      RECT 0.492 24.000 128.532 24.096 ;
      RECT 0.492 26.400 128.532 26.496 ;
      RECT 0.492 28.800 128.532 28.896 ;
      RECT 0.492 31.200 128.532 31.296 ;
      RECT 0.492 33.600 128.532 33.696 ;
      RECT 0.492 36.000 128.532 36.096 ;
      RECT 0.492 38.400 128.532 38.496 ;
      RECT 0.492 40.800 128.532 40.896 ;
      RECT 0.492 43.200 128.532 43.296 ;
      RECT 0.492 45.600 128.532 45.696 ;
      RECT 0.492 48.000 128.532 48.096 ;
      RECT 0.492 50.400 128.532 50.496 ;
      RECT 0.492 52.800 128.532 52.896 ;
      RECT 0.492 55.200 128.532 55.296 ;
      RECT 0.492 57.600 128.532 57.696 ;
      RECT 0.492 60.000 128.532 60.096 ;
      RECT 0.492 62.400 128.532 62.496 ;
      RECT 0.492 64.800 128.532 64.896 ;
      RECT 0.492 67.200 128.532 67.296 ;
      RECT 0.492 69.600 128.532 69.696 ;
      RECT 0.492 72.000 128.532 72.096 ;
      RECT 0.492 74.400 128.532 74.496 ;
      RECT 0.492 76.800 128.532 76.896 ;
      RECT 0.492 79.200 128.532 79.296 ;
      RECT 0.492 81.600 128.532 81.696 ;
      RECT 0.492 84.000 128.532 84.096 ;
      RECT 0.492 86.400 128.532 86.496 ;
      RECT 0.492 88.800 128.532 88.896 ;
      RECT 0.492 91.200 128.532 91.296 ;
      RECT 0.492 93.600 128.532 93.696 ;
      RECT 0.492 96.000 128.532 96.096 ;
      RECT 0.492 98.400 128.532 98.496 ;
      RECT 0.492 100.800 128.532 100.896 ;
      RECT 0.492 103.200 128.532 103.296 ;
      RECT 0.492 105.600 128.532 105.696 ;
      RECT 0.492 108.000 128.532 108.096 ;
      RECT 0.492 110.400 128.532 110.496 ;
      RECT 0.492 112.800 128.532 112.896 ;
      RECT 0.492 115.200 128.532 115.296 ;
      RECT 0.492 117.600 128.532 117.696 ;
      RECT 0.492 120.000 128.532 120.096 ;
      RECT 0.492 122.400 128.532 122.496 ;
      RECT 0.492 124.800 128.532 124.896 ;
      RECT 0.492 127.200 128.532 127.296 ;
      RECT 0.492 129.600 128.532 129.696 ;
      RECT 0.492 132.000 128.532 132.096 ;
      RECT 0.492 134.400 128.532 134.496 ;
      RECT 0.492 136.800 128.532 136.896 ;
      RECT 0.492 139.200 128.532 139.296 ;
      RECT 0.492 141.600 128.532 141.696 ;
      RECT 0.492 144.000 128.532 144.096 ;
      RECT 0.492 146.400 128.532 146.496 ;
      RECT 0.492 148.800 128.532 148.896 ;
      RECT 0.492 151.200 128.532 151.296 ;
      RECT 0.492 153.600 128.532 153.696 ;
      RECT 0.492 156.000 128.532 156.096 ;
      RECT 0.492 158.400 128.532 158.496 ;
      RECT 0.492 160.800 128.532 160.896 ;
      RECT 0.492 163.200 128.532 163.296 ;
      RECT 0.492 165.600 128.532 165.696 ;
      RECT 0.492 168.000 128.532 168.096 ;
      RECT 0.492 170.400 128.532 170.496 ;
      RECT 0.492 172.800 128.532 172.896 ;
      RECT 0.492 175.200 128.532 175.296 ;
      RECT 0.492 177.600 128.532 177.696 ;
      RECT 0.492 180.000 128.532 180.096 ;
      RECT 0.492 182.400 128.532 182.496 ;
      RECT 0.492 184.800 128.532 184.896 ;
      RECT 0.492 187.200 128.532 187.296 ;
      RECT 0.492 189.600 128.532 189.696 ;
      RECT 0.492 192.000 128.532 192.096 ;
      RECT 0.492 194.400 128.532 194.496 ;
      RECT 0.492 196.800 128.532 196.896 ;
      RECT 0.492 199.200 128.532 199.296 ;
      RECT 0.492 201.600 128.532 201.696 ;
      RECT 0.492 204.000 128.532 204.096 ;
      RECT 0.492 206.400 128.532 206.496 ;
      RECT 0.492 208.800 128.532 208.896 ;
      RECT 0.492 211.200 128.532 211.296 ;
      RECT 0.492 213.600 128.532 213.696 ;
      RECT 0.492 216.000 128.532 216.096 ;
      RECT 0.492 218.400 128.532 218.496 ;
      RECT 0.492 220.800 128.532 220.896 ;
      RECT 0.492 223.200 128.532 223.296 ;
      RECT 0.492 225.600 128.532 225.696 ;
      RECT 0.492 228.000 128.532 228.096 ;
      RECT 0.492 230.400 128.532 230.496 ;
      RECT 0.492 232.800 128.532 232.896 ;
      RECT 0.492 235.200 128.532 235.296 ;
      RECT 0.492 237.600 128.532 237.696 ;
      RECT 0.492 240.000 128.532 240.096 ;
      RECT 0.492 242.400 128.532 242.496 ;
      RECT 0.492 244.800 128.532 244.896 ;
      RECT 0.492 247.200 128.532 247.296 ;
      RECT 0.492 249.600 128.532 249.696 ;
      RECT 0.492 252.000 128.532 252.096 ;
      RECT 0.492 254.400 128.532 254.496 ;
      RECT 0.492 256.800 128.532 256.896 ;
      RECT 0.492 259.200 128.532 259.296 ;
      RECT 0.492 261.600 128.532 261.696 ;
      RECT 0.492 264.000 128.532 264.096 ;
      RECT 0.492 266.400 128.532 266.496 ;
      RECT 0.492 268.800 128.532 268.896 ;
      RECT 0.492 271.200 128.532 271.296 ;
      RECT 0.492 273.600 128.532 273.696 ;
      RECT 0.492 276.000 128.532 276.096 ;
      RECT 0.492 278.400 128.532 278.496 ;
      RECT 0.492 280.800 128.532 280.896 ;
      RECT 0.492 283.200 128.532 283.296 ;
      RECT 0.492 285.600 128.532 285.696 ;
      RECT 0.492 288.000 128.532 288.096 ;
      RECT 0.492 290.400 128.532 290.496 ;
      RECT 0.492 292.800 128.532 292.896 ;
      RECT 0.492 295.200 128.532 295.296 ;
      RECT 0.492 297.600 128.532 297.696 ;
      RECT 0.492 300.000 128.532 300.096 ;
      RECT 0.492 302.400 128.532 302.496 ;
      RECT 0.492 304.800 128.532 304.896 ;
      RECT 0.492 307.200 128.532 307.296 ;
      RECT 0.492 309.600 128.532 309.696 ;
      RECT 0.492 312.000 128.532 312.096 ;
      RECT 0.492 314.400 128.532 314.496 ;
      RECT 0.492 316.800 128.532 316.896 ;
      RECT 0.492 319.200 128.532 319.296 ;
      RECT 0.492 321.600 128.532 321.696 ;
      RECT 0.492 324.000 128.532 324.096 ;
      RECT 0.492 326.400 128.532 326.496 ;
      RECT 0.492 328.800 128.532 328.896 ;
      RECT 0.492 331.200 128.532 331.296 ;
      RECT 0.492 333.600 128.532 333.696 ;
      RECT 0.492 336.000 128.532 336.096 ;
      RECT 0.492 338.400 128.532 338.496 ;
      RECT 0.492 340.800 128.532 340.896 ;
      RECT 0.492 343.200 128.532 343.296 ;
      RECT 0.492 345.600 128.532 345.696 ;
      RECT 0.492 348.000 128.532 348.096 ;
      RECT 0.492 350.400 128.532 350.496 ;
      RECT 0.492 352.800 128.532 352.896 ;
      RECT 0.492 355.200 128.532 355.296 ;
      RECT 0.492 357.600 128.532 357.696 ;
      RECT 0.492 360.000 128.532 360.096 ;
      RECT 0.492 362.400 128.532 362.496 ;
      RECT 0.492 364.800 128.532 364.896 ;
      RECT 0.492 367.200 128.532 367.296 ;
      RECT 0.492 369.600 128.532 369.696 ;
      RECT 0.492 372.000 128.532 372.096 ;
      RECT 0.492 374.400 128.532 374.496 ;
      RECT 0.492 376.800 128.532 376.896 ;
      RECT 0.492 379.200 128.532 379.296 ;
      RECT 0.492 381.600 128.532 381.696 ;
      RECT 0.492 384.000 128.532 384.096 ;
      RECT 0.492 386.400 128.532 386.496 ;
      RECT 0.492 388.800 128.532 388.896 ;
      RECT 0.492 391.200 128.532 391.296 ;
      RECT 0.492 393.600 128.532 393.696 ;
      RECT 0.492 396.000 128.532 396.096 ;
      RECT 0.492 398.400 128.532 398.496 ;
      RECT 0.492 400.800 128.532 400.896 ;
      RECT 0.492 403.200 128.532 403.296 ;
      RECT 0.492 405.600 128.532 405.696 ;
      RECT 0.492 408.000 128.532 408.096 ;
      RECT 0.492 410.400 128.532 410.496 ;
      RECT 0.492 412.800 128.532 412.896 ;
      RECT 0.492 415.200 128.532 415.296 ;
      RECT 0.492 417.600 128.532 417.696 ;
      RECT 0.492 420.000 128.532 420.096 ;
      RECT 0.492 422.400 128.532 422.496 ;
      RECT 0.492 424.800 128.532 424.896 ;
      RECT 0.492 427.200 128.532 427.296 ;
      RECT 0.492 429.600 128.532 429.696 ;
      RECT 0.492 432.000 128.532 432.096 ;
      RECT 0.492 434.400 128.532 434.496 ;
      RECT 0.492 436.800 128.532 436.896 ;
      RECT 0.492 439.200 128.532 439.296 ;
      RECT 0.492 441.600 128.532 441.696 ;
      RECT 0.492 444.000 128.532 444.096 ;
      RECT 0.492 446.400 128.532 446.496 ;
      RECT 0.492 448.800 128.532 448.896 ;
      RECT 0.492 451.200 128.532 451.296 ;
      RECT 0.492 453.600 128.532 453.696 ;
      RECT 0.492 456.000 128.532 456.096 ;
      RECT 0.492 458.400 128.532 458.496 ;
      RECT 0.492 460.800 128.532 460.896 ;
      RECT 0.492 463.200 128.532 463.296 ;
      RECT 0.492 465.600 128.532 465.696 ;
      RECT 0.492 468.000 128.532 468.096 ;
      RECT 0.492 470.400 128.532 470.496 ;
      RECT 0.492 472.800 128.532 472.896 ;
      RECT 0.492 475.200 128.532 475.296 ;
      RECT 0.492 477.600 128.532 477.696 ;
      RECT 0.492 480.000 128.532 480.096 ;
      RECT 0.492 482.400 128.532 482.496 ;
      RECT 0.492 484.800 128.532 484.896 ;
      RECT 0.492 487.200 128.532 487.296 ;
      RECT 0.492 489.600 128.532 489.696 ;
      RECT 0.492 492.000 128.532 492.096 ;
      RECT 0.492 494.400 128.532 494.496 ;
      RECT 0.492 496.800 128.532 496.896 ;
      RECT 0.492 499.200 128.532 499.296 ;
      RECT 0.492 501.600 128.532 501.696 ;
      RECT 0.492 504.000 128.532 504.096 ;
      RECT 0.492 506.400 128.532 506.496 ;
      RECT 0.492 508.800 128.532 508.896 ;
      RECT 0.492 511.200 128.532 511.296 ;
      RECT 0.492 513.600 128.532 513.696 ;
      RECT 0.492 516.000 128.532 516.096 ;
      RECT 0.492 518.400 128.532 518.496 ;
      RECT 0.492 520.800 128.532 520.896 ;
      RECT 0.492 523.200 128.532 523.296 ;
      RECT 0.492 525.600 128.532 525.696 ;
      RECT 0.492 528.000 128.532 528.096 ;
      RECT 0.492 530.400 128.532 530.496 ;
      RECT 0.492 532.800 128.532 532.896 ;
      RECT 0.492 535.200 128.532 535.296 ;
      RECT 0.492 537.600 128.532 537.696 ;
      RECT 0.492 540.000 128.532 540.096 ;
      RECT 0.492 542.400 128.532 542.496 ;
      RECT 0.492 544.800 128.532 544.896 ;
      RECT 0.492 547.200 128.532 547.296 ;
      RECT 0.492 549.600 128.532 549.696 ;
      RECT 0.492 552.000 128.532 552.096 ;
      RECT 0.492 554.400 128.532 554.496 ;
      RECT 0.492 556.800 128.532 556.896 ;
      RECT 0.492 559.200 128.532 559.296 ;
      RECT 0.492 561.600 128.532 561.696 ;
      RECT 0.492 564.000 128.532 564.096 ;
      RECT 0.492 566.400 128.532 566.496 ;
      RECT 0.492 568.800 128.532 568.896 ;
      RECT 0.492 571.200 128.532 571.296 ;
      RECT 0.492 573.600 128.532 573.696 ;
      RECT 0.492 576.000 128.532 576.096 ;
      RECT 0.492 578.400 128.532 578.496 ;
      RECT 0.492 580.800 128.532 580.896 ;
      RECT 0.492 583.200 128.532 583.296 ;
      RECT 0.492 585.600 128.532 585.696 ;
      RECT 0.492 588.000 128.532 588.096 ;
      RECT 0.492 590.400 128.532 590.496 ;
      RECT 0.492 592.800 128.532 592.896 ;
      RECT 0.492 595.200 128.532 595.296 ;
      RECT 0.492 597.600 128.532 597.696 ;
      RECT 0.492 600.000 128.532 600.096 ;
      RECT 0.492 602.400 128.532 602.496 ;
      RECT 0.492 604.800 128.532 604.896 ;
      RECT 0.492 607.200 128.532 607.296 ;
      RECT 0.492 609.600 128.532 609.696 ;
      RECT 0.492 612.000 128.532 612.096 ;
      RECT 0.492 614.400 128.532 614.496 ;
      RECT 0.492 616.800 128.532 616.896 ;
      RECT 0.492 619.200 128.532 619.296 ;
      RECT 0.492 621.600 128.532 621.696 ;
      RECT 0.492 624.000 128.532 624.096 ;
      RECT 0.492 626.400 128.532 626.496 ;
      RECT 0.492 628.800 128.532 628.896 ;
      RECT 0.492 631.200 128.532 631.296 ;
      RECT 0.492 633.600 128.532 633.696 ;
      RECT 0.492 636.000 128.532 636.096 ;
      RECT 0.492 638.400 128.532 638.496 ;
      RECT 0.492 640.800 128.532 640.896 ;
      RECT 0.492 643.200 128.532 643.296 ;
      RECT 0.492 645.600 128.532 645.696 ;
      RECT 0.492 648.000 128.532 648.096 ;
      RECT 0.492 650.400 128.532 650.496 ;
      RECT 0.492 652.800 128.532 652.896 ;
      RECT 0.492 655.200 128.532 655.296 ;
      RECT 0.492 657.600 128.532 657.696 ;
      RECT 0.492 660.000 128.532 660.096 ;
      RECT 0.492 662.400 128.532 662.496 ;
      RECT 0.492 664.800 128.532 664.896 ;
      RECT 0.492 667.200 128.532 667.296 ;
      RECT 0.492 669.600 128.532 669.696 ;
      RECT 0.492 672.000 128.532 672.096 ;
      RECT 0.492 674.400 128.532 674.496 ;
      RECT 0.492 676.800 128.532 676.896 ;
      RECT 0.492 679.200 128.532 679.296 ;
      RECT 0.492 681.600 128.532 681.696 ;
      RECT 0.492 684.000 128.532 684.096 ;
      RECT 0.492 686.400 128.532 686.496 ;
      RECT 0.492 688.800 128.532 688.896 ;
      RECT 0.492 691.200 128.532 691.296 ;
      RECT 0.492 693.600 128.532 693.696 ;
      RECT 0.492 696.000 128.532 696.096 ;
      RECT 0.492 698.400 128.532 698.496 ;
      RECT 0.492 700.800 128.532 700.896 ;
      RECT 0.492 703.200 128.532 703.296 ;
      RECT 0.492 705.600 128.532 705.696 ;
      RECT 0.492 708.000 128.532 708.096 ;
      RECT 0.492 710.400 128.532 710.496 ;
      RECT 0.492 712.800 128.532 712.896 ;
      RECT 0.492 715.200 128.532 715.296 ;
      RECT 0.492 717.600 128.532 717.696 ;
      RECT 0.492 720.000 128.532 720.096 ;
      RECT 0.492 722.400 128.532 722.496 ;
      RECT 0.492 724.800 128.532 724.896 ;
      RECT 0.492 727.200 128.532 727.296 ;
      RECT 0.492 729.600 128.532 729.696 ;
      RECT 0.492 732.000 128.532 732.096 ;
      RECT 0.492 734.400 128.532 734.496 ;
      RECT 0.492 736.800 128.532 736.896 ;
      RECT 0.492 739.200 128.532 739.296 ;
      RECT 0.492 741.600 128.532 741.696 ;
      RECT 0.492 744.000 128.532 744.096 ;
      RECT 0.492 746.400 128.532 746.496 ;
      RECT 0.492 748.800 128.532 748.896 ;
      RECT 0.492 751.200 128.532 751.296 ;
      RECT 0.492 753.600 128.532 753.696 ;
      RECT 0.492 756.000 128.532 756.096 ;
      RECT 0.492 758.400 128.532 758.496 ;
      RECT 0.492 760.800 128.532 760.896 ;
      RECT 0.492 763.200 128.532 763.296 ;
      RECT 0.492 765.600 128.532 765.696 ;
      RECT 0.492 768.000 128.532 768.096 ;
      RECT 0.492 770.400 128.532 770.496 ;
      RECT 0.492 772.800 128.532 772.896 ;
      RECT 0.492 775.200 128.532 775.296 ;
      RECT 0.492 777.600 128.532 777.696 ;
      RECT 0.492 780.000 128.532 780.096 ;
      RECT 0.492 782.400 128.532 782.496 ;
      RECT 0.492 784.800 128.532 784.896 ;
      RECT 0.492 787.200 128.532 787.296 ;
      RECT 0.492 789.600 128.532 789.696 ;
      RECT 0.492 792.000 128.532 792.096 ;
      RECT 0.492 794.400 128.532 794.496 ;
      RECT 0.492 796.800 128.532 796.896 ;
      RECT 0.492 799.200 128.532 799.296 ;
      RECT 0.492 801.600 128.532 801.696 ;
      RECT 0.492 804.000 128.532 804.096 ;
      RECT 0.492 806.400 128.532 806.496 ;
      RECT 0.492 808.800 128.532 808.896 ;
      RECT 0.492 811.200 128.532 811.296 ;
      RECT 0.492 813.600 128.532 813.696 ;
      RECT 0.492 816.000 128.532 816.096 ;
      RECT 0.492 818.400 128.532 818.496 ;
      RECT 0.492 820.800 128.532 820.896 ;
      RECT 0.492 823.200 128.532 823.296 ;
      RECT 0.492 825.600 128.532 825.696 ;
      RECT 0.492 828.000 128.532 828.096 ;
      RECT 0.492 830.400 128.532 830.496 ;
      RECT 0.492 832.800 128.532 832.896 ;
      RECT 0.492 835.200 128.532 835.296 ;
      RECT 0.492 837.600 128.532 837.696 ;
      RECT 0.492 840.000 128.532 840.096 ;
      RECT 0.492 842.400 128.532 842.496 ;
      RECT 0.492 844.800 128.532 844.896 ;
      RECT 0.492 847.200 128.532 847.296 ;
      RECT 0.492 849.600 128.532 849.696 ;
      RECT 0.492 852.000 128.532 852.096 ;
      RECT 0.492 854.400 128.532 854.496 ;
      RECT 0.492 856.800 128.532 856.896 ;
      RECT 0.492 859.200 128.532 859.296 ;
      RECT 0.492 861.600 128.532 861.696 ;
      RECT 0.492 864.000 128.532 864.096 ;
      RECT 0.492 866.400 128.532 866.496 ;
      RECT 0.492 868.800 128.532 868.896 ;
      RECT 0.492 871.200 128.532 871.296 ;
      RECT 0.492 873.600 128.532 873.696 ;
      RECT 0.492 876.000 128.532 876.096 ;
      RECT 0.492 878.400 128.532 878.496 ;
      RECT 0.492 880.800 128.532 880.896 ;
      RECT 0.492 883.200 128.532 883.296 ;
      RECT 0.492 885.600 128.532 885.696 ;
      RECT 0.492 888.000 128.532 888.096 ;
      RECT 0.492 890.400 128.532 890.496 ;
      RECT 0.492 892.800 128.532 892.896 ;
      RECT 0.492 895.200 128.532 895.296 ;
      RECT 0.492 897.600 128.532 897.696 ;
      RECT 0.492 900.000 128.532 900.096 ;
      RECT 0.492 902.400 128.532 902.496 ;
      RECT 0.492 904.800 128.532 904.896 ;
      RECT 0.492 907.200 128.532 907.296 ;
      RECT 0.492 909.600 128.532 909.696 ;
      RECT 0.492 912.000 128.532 912.096 ;
      RECT 0.492 914.400 128.532 914.496 ;
      RECT 0.492 916.800 128.532 916.896 ;
      RECT 0.492 919.200 128.532 919.296 ;
      RECT 0.492 921.600 128.532 921.696 ;
      RECT 0.492 924.000 128.532 924.096 ;
      RECT 0.492 926.400 128.532 926.496 ;
      RECT 0.492 928.800 128.532 928.896 ;
      RECT 0.492 931.200 128.532 931.296 ;
      RECT 0.492 933.600 128.532 933.696 ;
      RECT 0.492 936.000 128.532 936.096 ;
      RECT 0.492 938.400 128.532 938.496 ;
      RECT 0.492 940.800 128.532 940.896 ;
      RECT 0.492 943.200 128.532 943.296 ;
      RECT 0.492 945.600 128.532 945.696 ;
      RECT 0.492 948.000 128.532 948.096 ;
      RECT 0.492 950.400 128.532 950.496 ;
      RECT 0.492 952.800 128.532 952.896 ;
      RECT 0.492 955.200 128.532 955.296 ;
      RECT 0.492 957.600 128.532 957.696 ;
      RECT 0.492 960.000 128.532 960.096 ;
      RECT 0.492 962.400 128.532 962.496 ;
      RECT 0.492 964.800 128.532 964.896 ;
      RECT 0.492 967.200 128.532 967.296 ;
      RECT 0.492 969.600 128.532 969.696 ;
      RECT 0.492 972.000 128.532 972.096 ;
      RECT 0.492 974.400 128.532 974.496 ;
      RECT 0.492 976.800 128.532 976.896 ;
      RECT 0.492 979.200 128.532 979.296 ;
      RECT 0.492 981.600 128.532 981.696 ;
      RECT 0.492 984.000 128.532 984.096 ;
      RECT 0.492 986.400 128.532 986.496 ;
      RECT 0.492 988.800 128.532 988.896 ;
      RECT 0.492 991.200 128.532 991.296 ;
      RECT 0.492 993.600 128.532 993.696 ;
      RECT 0.492 996.000 128.532 996.096 ;
      RECT 0.492 998.400 128.532 998.496 ;
      RECT 0.492 1000.800 128.532 1000.896 ;
      RECT 0.492 1003.200 128.532 1003.296 ;
      RECT 0.492 1005.600 128.532 1005.696 ;
      RECT 0.492 1008.000 128.532 1008.096 ;
      RECT 0.492 1010.400 128.532 1010.496 ;
      RECT 0.492 1012.800 128.532 1012.896 ;
      RECT 0.492 1015.200 128.532 1015.296 ;
      RECT 0.492 1017.600 128.532 1017.696 ;
      RECT 0.492 1020.000 128.532 1020.096 ;
      RECT 0.492 1022.400 128.532 1022.496 ;
      RECT 0.492 1024.800 128.532 1024.896 ;
      RECT 0.492 1027.200 128.532 1027.296 ;
      RECT 0.492 1029.600 128.532 1029.696 ;
      RECT 0.492 1032.000 128.532 1032.096 ;
      RECT 0.492 1034.400 128.532 1034.496 ;
      RECT 0.492 1036.800 128.532 1036.896 ;
      RECT 0.492 1039.200 128.532 1039.296 ;
      RECT 0.492 1041.600 128.532 1041.696 ;
      RECT 0.492 1044.000 128.532 1044.096 ;
      RECT 0.492 1046.400 128.532 1046.496 ;
      RECT 0.492 1048.800 128.532 1048.896 ;
      RECT 0.492 1051.200 128.532 1051.296 ;
      RECT 0.492 1053.600 128.532 1053.696 ;
      RECT 0.492 1056.000 128.532 1056.096 ;
      RECT 0.492 1058.400 128.532 1058.496 ;
      RECT 0.492 1060.800 128.532 1060.896 ;
      RECT 0.492 1063.200 128.532 1063.296 ;
      RECT 0.492 1065.600 128.532 1065.696 ;
      RECT 0.492 1068.000 128.532 1068.096 ;
      RECT 0.492 1070.400 128.532 1070.496 ;
      RECT 0.492 1072.800 128.532 1072.896 ;
      RECT 0.492 1075.200 128.532 1075.296 ;
      RECT 0.492 1077.600 128.532 1077.696 ;
      RECT 0.492 1080.000 128.532 1080.096 ;
      RECT 0.492 1082.400 128.532 1082.496 ;
      RECT 0.492 1084.800 128.532 1084.896 ;
      RECT 0.492 1087.200 128.532 1087.296 ;
      RECT 0.492 1089.600 128.532 1089.696 ;
      RECT 0.492 1092.000 128.532 1092.096 ;
      RECT 0.492 1094.400 128.532 1094.496 ;
      RECT 0.492 1096.800 128.532 1096.896 ;
      RECT 0.492 1099.200 128.532 1099.296 ;
      RECT 0.492 1101.600 128.532 1101.696 ;
      RECT 0.492 1104.000 128.532 1104.096 ;
      RECT 0.492 1106.400 128.532 1106.496 ;
      RECT 0.492 1108.800 128.532 1108.896 ;
      RECT 0.492 1111.200 128.532 1111.296 ;
      RECT 0.492 1113.600 128.532 1113.696 ;
      RECT 0.492 1116.000 128.532 1116.096 ;
      RECT 0.492 1118.400 128.532 1118.496 ;
      RECT 0.492 1120.800 128.532 1120.896 ;
      RECT 0.492 1123.200 128.532 1123.296 ;
      RECT 0.492 1125.600 128.532 1125.696 ;
      RECT 0.492 1128.000 128.532 1128.096 ;
      RECT 0.492 1130.400 128.532 1130.496 ;
      RECT 0.492 1132.800 128.532 1132.896 ;
      RECT 0.492 1135.200 128.532 1135.296 ;
      RECT 0.492 1137.600 128.532 1137.696 ;
      RECT 0.492 1140.000 128.532 1140.096 ;
      RECT 0.492 1142.400 128.532 1142.496 ;
      RECT 0.492 1144.800 128.532 1144.896 ;
      RECT 0.492 1147.200 128.532 1147.296 ;
      RECT 0.492 1149.600 128.532 1149.696 ;
      RECT 0.492 1152.000 128.532 1152.096 ;
      RECT 0.492 1154.400 128.532 1154.496 ;
      RECT 0.492 1156.800 128.532 1156.896 ;
      RECT 0.492 1159.200 128.532 1159.296 ;
      RECT 0.492 1161.600 128.532 1161.696 ;
      RECT 0.492 1164.000 128.532 1164.096 ;
      RECT 0.492 1166.400 128.532 1166.496 ;
      RECT 0.492 1168.800 128.532 1168.896 ;
      RECT 0.492 1171.200 128.532 1171.296 ;
      RECT 0.492 1173.600 128.532 1173.696 ;
      RECT 0.492 1176.000 128.532 1176.096 ;
      RECT 0.492 1178.400 128.532 1178.496 ;
      RECT 0.492 1180.800 128.532 1180.896 ;
      RECT 0.492 1183.200 128.532 1183.296 ;
      RECT 0.492 1185.600 128.532 1185.696 ;
      RECT 0.492 1188.000 128.532 1188.096 ;
      RECT 0.492 1190.400 128.532 1190.496 ;
      RECT 0.492 1192.800 128.532 1192.896 ;
      RECT 0.492 1195.200 128.532 1195.296 ;
      RECT 0.492 1197.600 128.532 1197.696 ;
      RECT 0.492 1200.000 128.532 1200.096 ;
      RECT 0.492 1202.400 128.532 1202.496 ;
      RECT 0.492 1204.800 128.532 1204.896 ;
      RECT 0.492 1207.200 128.532 1207.296 ;
      RECT 0.492 1209.600 128.532 1209.696 ;
      RECT 0.492 1212.000 128.532 1212.096 ;
      RECT 0.492 1214.400 128.532 1214.496 ;
      RECT 0.492 1216.800 128.532 1216.896 ;
      RECT 0.492 1219.200 128.532 1219.296 ;
      RECT 0.492 1221.600 128.532 1221.696 ;
      RECT 0.492 1224.000 128.532 1224.096 ;
      RECT 0.492 1226.400 128.532 1226.496 ;
      RECT 0.492 1228.800 128.532 1228.896 ;
      RECT 0.492 1231.200 128.532 1231.296 ;
      RECT 0.492 1233.600 128.532 1233.696 ;
      RECT 0.492 1236.000 128.532 1236.096 ;
      RECT 0.492 1238.400 128.532 1238.496 ;
      RECT 0.492 1240.800 128.532 1240.896 ;
      RECT 0.492 1243.200 128.532 1243.296 ;
      RECT 0.492 1245.600 128.532 1245.696 ;
      RECT 0.492 1248.000 128.532 1248.096 ;
      RECT 0.492 1250.400 128.532 1250.496 ;
      RECT 0.492 1252.800 128.532 1252.896 ;
      RECT 0.492 1255.200 128.532 1255.296 ;
      RECT 0.492 1257.600 128.532 1257.696 ;
      RECT 0.492 1260.000 128.532 1260.096 ;
      RECT 0.492 1262.400 128.532 1262.496 ;
      RECT 0.492 1264.800 128.532 1264.896 ;
      RECT 0.492 1267.200 128.532 1267.296 ;
      RECT 0.492 1269.600 128.532 1269.696 ;
      RECT 0.492 1272.000 128.532 1272.096 ;
      RECT 0.492 1274.400 128.532 1274.496 ;
      RECT 0.492 1276.800 128.532 1276.896 ;
      RECT 0.492 1279.200 128.532 1279.296 ;
      RECT 0.492 1281.600 128.532 1281.696 ;
      RECT 0.492 1284.000 128.532 1284.096 ;
      RECT 0.492 1286.400 128.532 1286.496 ;
      RECT 0.492 1288.800 128.532 1288.896 ;
      RECT 0.492 1291.200 128.532 1291.296 ;
      RECT 0.492 1293.600 128.532 1293.696 ;
      RECT 0.492 1296.000 128.532 1296.096 ;
      RECT 0.492 1298.400 128.532 1298.496 ;
      RECT 0.492 1300.800 128.532 1300.896 ;
      RECT 0.492 1303.200 128.532 1303.296 ;
      RECT 0.492 1305.600 128.532 1305.696 ;
      RECT 0.492 1308.000 128.532 1308.096 ;
      RECT 0.492 1310.400 128.532 1310.496 ;
      RECT 0.492 1312.800 128.532 1312.896 ;
      RECT 0.492 1315.200 128.532 1315.296 ;
      RECT 0.492 1317.600 128.532 1317.696 ;
      RECT 0.492 1320.000 128.532 1320.096 ;
      RECT 0.492 1322.400 128.532 1322.496 ;
      RECT 0.492 1324.800 128.532 1324.896 ;
      RECT 0.492 1327.200 128.532 1327.296 ;
      RECT 0.492 1329.600 128.532 1329.696 ;
      RECT 0.492 1332.000 128.532 1332.096 ;
      RECT 0.492 1334.400 128.532 1334.496 ;
      RECT 0.492 1336.800 128.532 1336.896 ;
      RECT 0.492 1339.200 128.532 1339.296 ;
      RECT 0.492 1341.600 128.532 1341.696 ;
      RECT 0.492 1344.000 128.532 1344.096 ;
      RECT 0.492 1346.400 128.532 1346.496 ;
      RECT 0.492 1348.800 128.532 1348.896 ;
      RECT 0.492 1351.200 128.532 1351.296 ;
      RECT 0.492 1353.600 128.532 1353.696 ;
      RECT 0.492 1356.000 128.532 1356.096 ;
      RECT 0.492 1358.400 128.532 1358.496 ;
      RECT 0.492 1360.800 128.532 1360.896 ;
      RECT 0.492 1363.200 128.532 1363.296 ;
      RECT 0.492 1365.600 128.532 1365.696 ;
      RECT 0.492 1368.000 128.532 1368.096 ;
      RECT 0.492 1370.400 128.532 1370.496 ;
      RECT 0.492 1372.800 128.532 1372.896 ;
      RECT 0.492 1375.200 128.532 1375.296 ;
      RECT 0.492 1377.600 128.532 1377.696 ;
      RECT 0.492 1380.000 128.532 1380.096 ;
      RECT 0.492 1382.400 128.532 1382.496 ;
      RECT 0.492 1384.800 128.532 1384.896 ;
      RECT 0.492 1387.200 128.532 1387.296 ;
      RECT 0.492 1389.600 128.532 1389.696 ;
      RECT 0.492 1392.000 128.532 1392.096 ;
      RECT 0.492 1394.400 128.532 1394.496 ;
      RECT 0.492 1396.800 128.532 1396.896 ;
      RECT 0.492 1399.200 128.532 1399.296 ;
      RECT 0.492 1401.600 128.532 1401.696 ;
      RECT 0.492 1404.000 128.532 1404.096 ;
      RECT 0.492 1406.400 128.532 1406.496 ;
      RECT 0.492 1408.800 128.532 1408.896 ;
      RECT 0.492 1411.200 128.532 1411.296 ;
      RECT 0.492 1413.600 128.532 1413.696 ;
      RECT 0.492 1416.000 128.532 1416.096 ;
      RECT 0.492 1418.400 128.532 1418.496 ;
      RECT 0.492 1420.800 128.532 1420.896 ;
      RECT 0.492 1423.200 128.532 1423.296 ;
      RECT 0.492 1425.600 128.532 1425.696 ;
      RECT 0.492 1428.000 128.532 1428.096 ;
      RECT 0.492 1430.400 128.532 1430.496 ;
      RECT 0.492 1432.800 128.532 1432.896 ;
      RECT 0.492 1435.200 128.532 1435.296 ;
      RECT 0.492 1437.600 128.532 1437.696 ;
      RECT 0.492 1440.000 128.532 1440.096 ;
      RECT 0.492 1442.400 128.532 1442.496 ;
      RECT 0.492 1444.800 128.532 1444.896 ;
      RECT 0.492 1447.200 128.532 1447.296 ;
      RECT 0.492 1449.600 128.532 1449.696 ;
      RECT 0.492 1452.000 128.532 1452.096 ;
      RECT 0.492 1454.400 128.532 1454.496 ;
      RECT 0.492 1456.800 128.532 1456.896 ;
      RECT 0.492 1459.200 128.532 1459.296 ;
      RECT 0.492 1461.600 128.532 1461.696 ;
      RECT 0.492 1464.000 128.532 1464.096 ;
      RECT 0.492 1466.400 128.532 1466.496 ;
      RECT 0.492 1468.800 128.532 1468.896 ;
      RECT 0.492 1471.200 128.532 1471.296 ;
      RECT 0.492 1473.600 128.532 1473.696 ;
      RECT 0.492 1476.000 128.532 1476.096 ;
      RECT 0.492 1478.400 128.532 1478.496 ;
      RECT 0.492 1480.800 128.532 1480.896 ;
      RECT 0.492 1483.200 128.532 1483.296 ;
      RECT 0.492 1485.600 128.532 1485.696 ;
      RECT 0.492 1488.000 128.532 1488.096 ;
      RECT 0.492 1490.400 128.532 1490.496 ;
      RECT 0.492 1492.800 128.532 1492.896 ;
      RECT 0.492 1495.200 128.532 1495.296 ;
      RECT 0.492 1497.600 128.532 1497.696 ;
      RECT 0.492 1500.000 128.532 1500.096 ;
      RECT 0.492 1502.400 128.532 1502.496 ;
      RECT 0.492 1504.800 128.532 1504.896 ;
      RECT 0.492 1507.200 128.532 1507.296 ;
      RECT 0.492 1509.600 128.532 1509.696 ;
      RECT 0.492 1512.000 128.532 1512.096 ;
      RECT 0.492 1514.400 128.532 1514.496 ;
      RECT 0.492 1516.800 128.532 1516.896 ;
      RECT 0.492 1519.200 128.532 1519.296 ;
      RECT 0.492 1521.600 128.532 1521.696 ;
      RECT 0.492 1524.000 128.532 1524.096 ;
      RECT 0.492 1526.400 128.532 1526.496 ;
      RECT 0.492 1528.800 128.532 1528.896 ;
      RECT 0.492 1531.200 128.532 1531.296 ;
      RECT 0.492 1533.600 128.532 1533.696 ;
      RECT 0.492 1536.000 128.532 1536.096 ;
      RECT 0.492 1538.400 128.532 1538.496 ;
      RECT 0.492 1540.800 128.532 1540.896 ;
      RECT 0.492 1543.200 128.532 1543.296 ;
      RECT 0.492 1545.600 128.532 1545.696 ;
      RECT 0.492 1548.000 128.532 1548.096 ;
      RECT 0.492 1550.400 128.532 1550.496 ;
      RECT 0.492 1552.800 128.532 1552.896 ;
      RECT 0.492 1555.200 128.532 1555.296 ;
      RECT 0.492 1557.600 128.532 1557.696 ;
      RECT 0.492 1560.000 128.532 1560.096 ;
      RECT 0.492 1562.400 128.532 1562.496 ;
      RECT 0.492 1564.800 128.532 1564.896 ;
      RECT 0.492 1567.200 128.532 1567.296 ;
      RECT 0.492 1569.600 128.532 1569.696 ;
      RECT 0.492 1572.000 128.532 1572.096 ;
      RECT 0.492 1574.400 128.532 1574.496 ;
      RECT 0.492 1576.800 128.532 1576.896 ;
      RECT 0.492 1579.200 128.532 1579.296 ;
      RECT 0.492 1581.600 128.532 1581.696 ;
      RECT 0.492 1584.000 128.532 1584.096 ;
      RECT 0.492 1586.400 128.532 1586.496 ;
      RECT 0.492 1588.800 128.532 1588.896 ;
      RECT 0.492 1591.200 128.532 1591.296 ;
      RECT 0.492 1593.600 128.532 1593.696 ;
      RECT 0.492 1596.000 128.532 1596.096 ;
      RECT 0.492 1598.400 128.532 1598.496 ;
      RECT 0.492 1600.800 128.532 1600.896 ;
      RECT 0.492 1603.200 128.532 1603.296 ;
      RECT 0.492 1605.600 128.532 1605.696 ;
      RECT 0.492 1608.000 128.532 1608.096 ;
      RECT 0.492 1610.400 128.532 1610.496 ;
      RECT 0.492 1612.800 128.532 1612.896 ;
      RECT 0.492 1615.200 128.532 1615.296 ;
      RECT 0.492 1617.600 128.532 1617.696 ;
      RECT 0.492 1620.000 128.532 1620.096 ;
      RECT 0.492 1622.400 128.532 1622.496 ;
      RECT 0.492 1624.800 128.532 1624.896 ;
      RECT 0.492 1627.200 128.532 1627.296 ;
      RECT 0.492 1629.600 128.532 1629.696 ;
      RECT 0.492 1632.000 128.532 1632.096 ;
      RECT 0.492 1634.400 128.532 1634.496 ;
      RECT 0.492 1636.800 128.532 1636.896 ;
      RECT 0.492 1639.200 128.532 1639.296 ;
      RECT 0.492 1641.600 128.532 1641.696 ;
      RECT 0.492 1644.000 128.532 1644.096 ;
      RECT 0.492 1646.400 128.532 1646.496 ;
      RECT 0.492 1648.800 128.532 1648.896 ;
      RECT 0.492 1651.200 128.532 1651.296 ;
      RECT 0.492 1653.600 128.532 1653.696 ;
      RECT 0.492 1656.000 128.532 1656.096 ;
      RECT 0.492 1658.400 128.532 1658.496 ;
      RECT 0.492 1660.800 128.532 1660.896 ;
      RECT 0.492 1663.200 128.532 1663.296 ;
      RECT 0.492 1665.600 128.532 1665.696 ;
      RECT 0.492 1668.000 128.532 1668.096 ;
      RECT 0.492 1670.400 128.532 1670.496 ;
      RECT 0.492 1672.800 128.532 1672.896 ;
      RECT 0.492 1675.200 128.532 1675.296 ;
      RECT 0.492 1677.600 128.532 1677.696 ;
      RECT 0.492 1680.000 128.532 1680.096 ;
      RECT 0.492 1682.400 128.532 1682.496 ;
      RECT 0.492 1684.800 128.532 1684.896 ;
      RECT 0.492 1687.200 128.532 1687.296 ;
      RECT 0.492 1689.600 128.532 1689.696 ;
      RECT 0.492 1692.000 128.532 1692.096 ;
      RECT 0.492 1694.400 128.532 1694.496 ;
      RECT 0.492 1696.800 128.532 1696.896 ;
      RECT 0.492 1699.200 128.532 1699.296 ;
      RECT 0.492 1701.600 128.532 1701.696 ;
      RECT 0.492 1704.000 128.532 1704.096 ;
      RECT 0.492 1706.400 128.532 1706.496 ;
      RECT 0.492 1708.800 128.532 1708.896 ;
      RECT 0.492 1711.200 128.532 1711.296 ;
      RECT 0.492 1713.600 128.532 1713.696 ;
      RECT 0.492 1716.000 128.532 1716.096 ;
      RECT 0.492 1718.400 128.532 1718.496 ;
      RECT 0.492 1720.800 128.532 1720.896 ;
      RECT 0.492 1723.200 128.532 1723.296 ;
      RECT 0.492 1725.600 128.532 1725.696 ;
      RECT 0.492 1728.000 128.532 1728.096 ;
      RECT 0.492 1730.400 128.532 1730.496 ;
      RECT 0.492 1732.800 128.532 1732.896 ;
      RECT 0.492 1735.200 128.532 1735.296 ;
      RECT 0.492 1737.600 128.532 1737.696 ;
      RECT 0.492 1740.000 128.532 1740.096 ;
      RECT 0.492 1742.400 128.532 1742.496 ;
      RECT 0.492 1744.800 128.532 1744.896 ;
      RECT 0.492 1747.200 128.532 1747.296 ;
      RECT 0.492 1749.600 128.532 1749.696 ;
      RECT 0.492 1752.000 128.532 1752.096 ;
      RECT 0.492 1754.400 128.532 1754.496 ;
      RECT 0.492 1756.800 128.532 1756.896 ;
      RECT 0.492 1759.200 128.532 1759.296 ;
      RECT 0.492 1761.600 128.532 1761.696 ;
      RECT 0.492 1764.000 128.532 1764.096 ;
      RECT 0.492 1766.400 128.532 1766.496 ;
      RECT 0.492 1768.800 128.532 1768.896 ;
      RECT 0.492 1771.200 128.532 1771.296 ;
      RECT 0.492 1773.600 128.532 1773.696 ;
      RECT 0.492 1776.000 128.532 1776.096 ;
      RECT 0.492 1778.400 128.532 1778.496 ;
      RECT 0.492 1780.800 128.532 1780.896 ;
      RECT 0.492 1783.200 128.532 1783.296 ;
      RECT 0.492 1785.600 128.532 1785.696 ;
      RECT 0.492 1788.000 128.532 1788.096 ;
      RECT 0.492 1790.400 128.532 1790.496 ;
      RECT 0.492 1792.800 128.532 1792.896 ;
      RECT 0.492 1795.200 128.532 1795.296 ;
      RECT 0.492 1797.600 128.532 1797.696 ;
      RECT 0.492 1800.000 128.532 1800.096 ;
      RECT 0.492 1802.400 128.532 1802.496 ;
      RECT 0.492 1804.800 128.532 1804.896 ;
      RECT 0.492 1807.200 128.532 1807.296 ;
      RECT 0.492 1809.600 128.532 1809.696 ;
      RECT 0.492 1812.000 128.532 1812.096 ;
      RECT 0.492 1814.400 128.532 1814.496 ;
      RECT 0.492 1816.800 128.532 1816.896 ;
      RECT 0.492 1819.200 128.532 1819.296 ;
      RECT 0.492 1821.600 128.532 1821.696 ;
      RECT 0.492 1824.000 128.532 1824.096 ;
      RECT 0.492 1826.400 128.532 1826.496 ;
      RECT 0.492 1828.800 128.532 1828.896 ;
      RECT 0.492 1831.200 128.532 1831.296 ;
      RECT 0.492 1833.600 128.532 1833.696 ;
      RECT 0.492 1836.000 128.532 1836.096 ;
      RECT 0.492 1838.400 128.532 1838.496 ;
      RECT 0.492 1840.800 128.532 1840.896 ;
      RECT 0.492 1843.200 128.532 1843.296 ;
      RECT 0.492 1845.600 128.532 1845.696 ;
      RECT 0.492 1848.000 128.532 1848.096 ;
      RECT 0.492 1850.400 128.532 1850.496 ;
      RECT 0.492 1852.800 128.532 1852.896 ;
      RECT 0.492 1855.200 128.532 1855.296 ;
      RECT 0.492 1857.600 128.532 1857.696 ;
      RECT 0.492 1860.000 128.532 1860.096 ;
      RECT 0.492 1862.400 128.532 1862.496 ;
      RECT 0.492 1864.800 128.532 1864.896 ;
      RECT 0.492 1867.200 128.532 1867.296 ;
      RECT 0.492 1869.600 128.532 1869.696 ;
      RECT 0.492 1872.000 128.532 1872.096 ;
      RECT 0.492 1874.400 128.532 1874.496 ;
      RECT 0.492 1876.800 128.532 1876.896 ;
      RECT 0.492 1879.200 128.532 1879.296 ;
      RECT 0.492 1881.600 128.532 1881.696 ;
      RECT 0.492 1884.000 128.532 1884.096 ;
      RECT 0.492 1886.400 128.532 1886.496 ;
      RECT 0.492 1888.800 128.532 1888.896 ;
      RECT 0.492 1891.200 128.532 1891.296 ;
      RECT 0.492 1893.600 128.532 1893.696 ;
      RECT 0.492 1896.000 128.532 1896.096 ;
      RECT 0.492 1898.400 128.532 1898.496 ;
      RECT 0.492 1900.800 128.532 1900.896 ;
      RECT 0.492 1903.200 128.532 1903.296 ;
      RECT 0.492 1905.600 128.532 1905.696 ;
      RECT 0.492 1908.000 128.532 1908.096 ;
      RECT 0.492 1910.400 128.532 1910.496 ;
      RECT 0.492 1912.800 128.532 1912.896 ;
      RECT 0.492 1915.200 128.532 1915.296 ;
      RECT 0.492 1917.600 128.532 1917.696 ;
      RECT 0.492 1920.000 128.532 1920.096 ;
      RECT 0.492 1922.400 128.532 1922.496 ;
      RECT 0.492 1924.800 128.532 1924.896 ;
      RECT 0.492 1927.200 128.532 1927.296 ;
      RECT 0.492 1929.600 128.532 1929.696 ;
      RECT 0.492 1932.000 128.532 1932.096 ;
      RECT 0.492 1934.400 128.532 1934.496 ;
      RECT 0.492 1936.800 128.532 1936.896 ;
      RECT 0.492 1939.200 128.532 1939.296 ;
      RECT 0.492 1941.600 128.532 1941.696 ;
      RECT 0.492 1944.000 128.532 1944.096 ;
      RECT 0.492 1946.400 128.532 1946.496 ;
      RECT 0.492 1948.800 128.532 1948.896 ;
      RECT 0.492 1951.200 128.532 1951.296 ;
      RECT 0.492 1953.600 128.532 1953.696 ;
      RECT 0.492 1956.000 128.532 1956.096 ;
      RECT 0.492 1958.400 128.532 1958.496 ;
      RECT 0.492 1960.800 128.532 1960.896 ;
      RECT 0.492 1963.200 128.532 1963.296 ;
      RECT 0.492 1965.600 128.532 1965.696 ;
      RECT 0.492 1968.000 128.532 1968.096 ;
      RECT 0.492 1970.400 128.532 1970.496 ;
      RECT 0.492 1972.800 128.532 1972.896 ;
      RECT 0.492 1975.200 128.532 1975.296 ;
      RECT 0.492 1977.600 128.532 1977.696 ;
      RECT 0.492 1980.000 128.532 1980.096 ;
      RECT 0.492 1982.400 128.532 1982.496 ;
      RECT 0.492 1984.800 128.532 1984.896 ;
      RECT 0.492 1987.200 128.532 1987.296 ;
      RECT 0.492 1989.600 128.532 1989.696 ;
      RECT 0.492 1992.000 128.532 1992.096 ;
      RECT 0.492 1994.400 128.532 1994.496 ;
      RECT 0.492 1996.800 128.532 1996.896 ;
      RECT 0.492 1999.200 128.532 1999.296 ;
      RECT 0.492 2001.600 128.532 2001.696 ;
      RECT 0.492 2004.000 128.532 2004.096 ;
      RECT 0.492 2006.400 128.532 2006.496 ;
      RECT 0.492 2008.800 128.532 2008.896 ;
      RECT 0.492 2011.200 128.532 2011.296 ;
      RECT 0.492 2013.600 128.532 2013.696 ;
      RECT 0.492 2016.000 128.532 2016.096 ;
      RECT 0.492 2018.400 128.532 2018.496 ;
      RECT 0.492 2020.800 128.532 2020.896 ;
      RECT 0.492 2023.200 128.532 2023.296 ;
      RECT 0.492 2025.600 128.532 2025.696 ;
      RECT 0.492 2028.000 128.532 2028.096 ;
      RECT 0.492 2030.400 128.532 2030.496 ;
      RECT 0.492 2032.800 128.532 2032.896 ;
      RECT 0.492 2035.200 128.532 2035.296 ;
      RECT 0.492 2037.600 128.532 2037.696 ;
      RECT 0.492 2040.000 128.532 2040.096 ;
      RECT 0.492 2042.400 128.532 2042.496 ;
      RECT 0.492 2044.800 128.532 2044.896 ;
      RECT 0.492 2047.200 128.532 2047.296 ;
      RECT 0.492 2049.600 128.532 2049.696 ;
      RECT 0.492 2052.000 128.532 2052.096 ;
      RECT 0.492 2054.400 128.532 2054.496 ;
      RECT 0.492 2056.800 128.532 2056.896 ;
      RECT 0.492 2059.200 128.532 2059.296 ;
      RECT 0.492 2061.600 128.532 2061.696 ;
      RECT 0.492 2064.000 128.532 2064.096 ;
      RECT 0.492 2066.400 128.532 2066.496 ;
      RECT 0.492 2068.800 128.532 2068.896 ;
      RECT 0.492 2071.200 128.532 2071.296 ;
      RECT 0.492 2073.600 128.532 2073.696 ;
      RECT 0.492 2076.000 128.532 2076.096 ;
      RECT 0.492 2078.400 128.532 2078.496 ;
      RECT 0.492 2080.800 128.532 2080.896 ;
      RECT 0.492 2083.200 128.532 2083.296 ;
      RECT 0.492 2085.600 128.532 2085.696 ;
      RECT 0.492 2088.000 128.532 2088.096 ;
      RECT 0.492 2090.400 128.532 2090.496 ;
      RECT 0.492 2092.800 128.532 2092.896 ;
      RECT 0.492 2095.200 128.532 2095.296 ;
      RECT 0.492 2097.600 128.532 2097.696 ;
      RECT 0.492 2100.000 128.532 2100.096 ;
      RECT 0.492 2102.400 128.532 2102.496 ;
      RECT 0.492 2104.800 128.532 2104.896 ;
      RECT 0.492 2107.200 128.532 2107.296 ;
      RECT 0.492 2109.600 128.532 2109.696 ;
      RECT 0.492 2112.000 128.532 2112.096 ;
      RECT 0.492 2114.400 128.532 2114.496 ;
      RECT 0.492 2116.800 128.532 2116.896 ;
      RECT 0.492 2119.200 128.532 2119.296 ;
      RECT 0.492 2121.600 128.532 2121.696 ;
      RECT 0.492 2124.000 128.532 2124.096 ;
      RECT 0.492 2126.400 128.532 2126.496 ;
      RECT 0.492 2128.800 128.532 2128.896 ;
      RECT 0.492 2131.200 128.532 2131.296 ;
      RECT 0.492 2133.600 128.532 2133.696 ;
      RECT 0.492 2136.000 128.532 2136.096 ;
      RECT 0.492 2138.400 128.532 2138.496 ;
      RECT 0.492 2140.800 128.532 2140.896 ;
      RECT 0.492 2143.200 128.532 2143.296 ;
      RECT 0.492 2145.600 128.532 2145.696 ;
      RECT 0.492 2148.000 128.532 2148.096 ;
      RECT 0.492 2150.400 128.532 2150.496 ;
      RECT 0.492 2152.800 128.532 2152.896 ;
      RECT 0.492 2155.200 128.532 2155.296 ;
      RECT 0.492 2157.600 128.532 2157.696 ;
      RECT 0.492 2160.000 128.532 2160.096 ;
      RECT 0.492 2162.400 128.532 2162.496 ;
      RECT 0.492 2164.800 128.532 2164.896 ;
      RECT 0.492 2167.200 128.532 2167.296 ;
      RECT 0.492 2169.600 128.532 2169.696 ;
      RECT 0.492 2172.000 128.532 2172.096 ;
      RECT 0.492 2174.400 128.532 2174.496 ;
      RECT 0.492 2176.800 128.532 2176.896 ;
      RECT 0.492 2179.200 128.532 2179.296 ;
      RECT 0.492 2181.600 128.532 2181.696 ;
      RECT 0.492 2184.000 128.532 2184.096 ;
      RECT 0.492 2186.400 128.532 2186.496 ;
      RECT 0.492 2188.800 128.532 2188.896 ;
      RECT 0.492 2191.200 128.532 2191.296 ;
      RECT 0.492 2193.600 128.532 2193.696 ;
      RECT 0.492 2196.000 128.532 2196.096 ;
      RECT 0.492 2198.400 128.532 2198.496 ;
      RECT 0.492 2200.800 128.532 2200.896 ;
      RECT 0.492 2203.200 128.532 2203.296 ;
      RECT 0.492 2205.600 128.532 2205.696 ;
      RECT 0.492 2208.000 128.532 2208.096 ;
      RECT 0.492 2210.400 128.532 2210.496 ;
      RECT 0.492 2212.800 128.532 2212.896 ;
      RECT 0.492 2215.200 128.532 2215.296 ;
      RECT 0.492 2217.600 128.532 2217.696 ;
      RECT 0.492 2220.000 128.532 2220.096 ;
      RECT 0.492 2222.400 128.532 2222.496 ;
      RECT 0.492 2224.800 128.532 2224.896 ;
      RECT 0.492 2227.200 128.532 2227.296 ;
      RECT 0.492 2229.600 128.532 2229.696 ;
      RECT 0.492 2232.000 128.532 2232.096 ;
      RECT 0.492 2234.400 128.532 2234.496 ;
      RECT 0.492 2236.800 128.532 2236.896 ;
      RECT 0.492 2239.200 128.532 2239.296 ;
      RECT 0.492 2241.600 128.532 2241.696 ;
      RECT 0.492 2244.000 128.532 2244.096 ;
      RECT 0.492 2246.400 128.532 2246.496 ;
      RECT 0.492 2248.800 128.532 2248.896 ;
    END
  END VDD
  OBS
    LAYER M1 ;
    RECT 0 0 129.024 2250.216 ;
    LAYER M2 ;
    RECT 0 0 129.024 2250.216 ;
    LAYER M3 ;
    RECT 0 0 129.024 2250.216 ;
    LAYER M4 ;
    RECT 0 0 129.024 2250.216 ;
  END
END ot_s81_pma_txm

END LIBRARY
